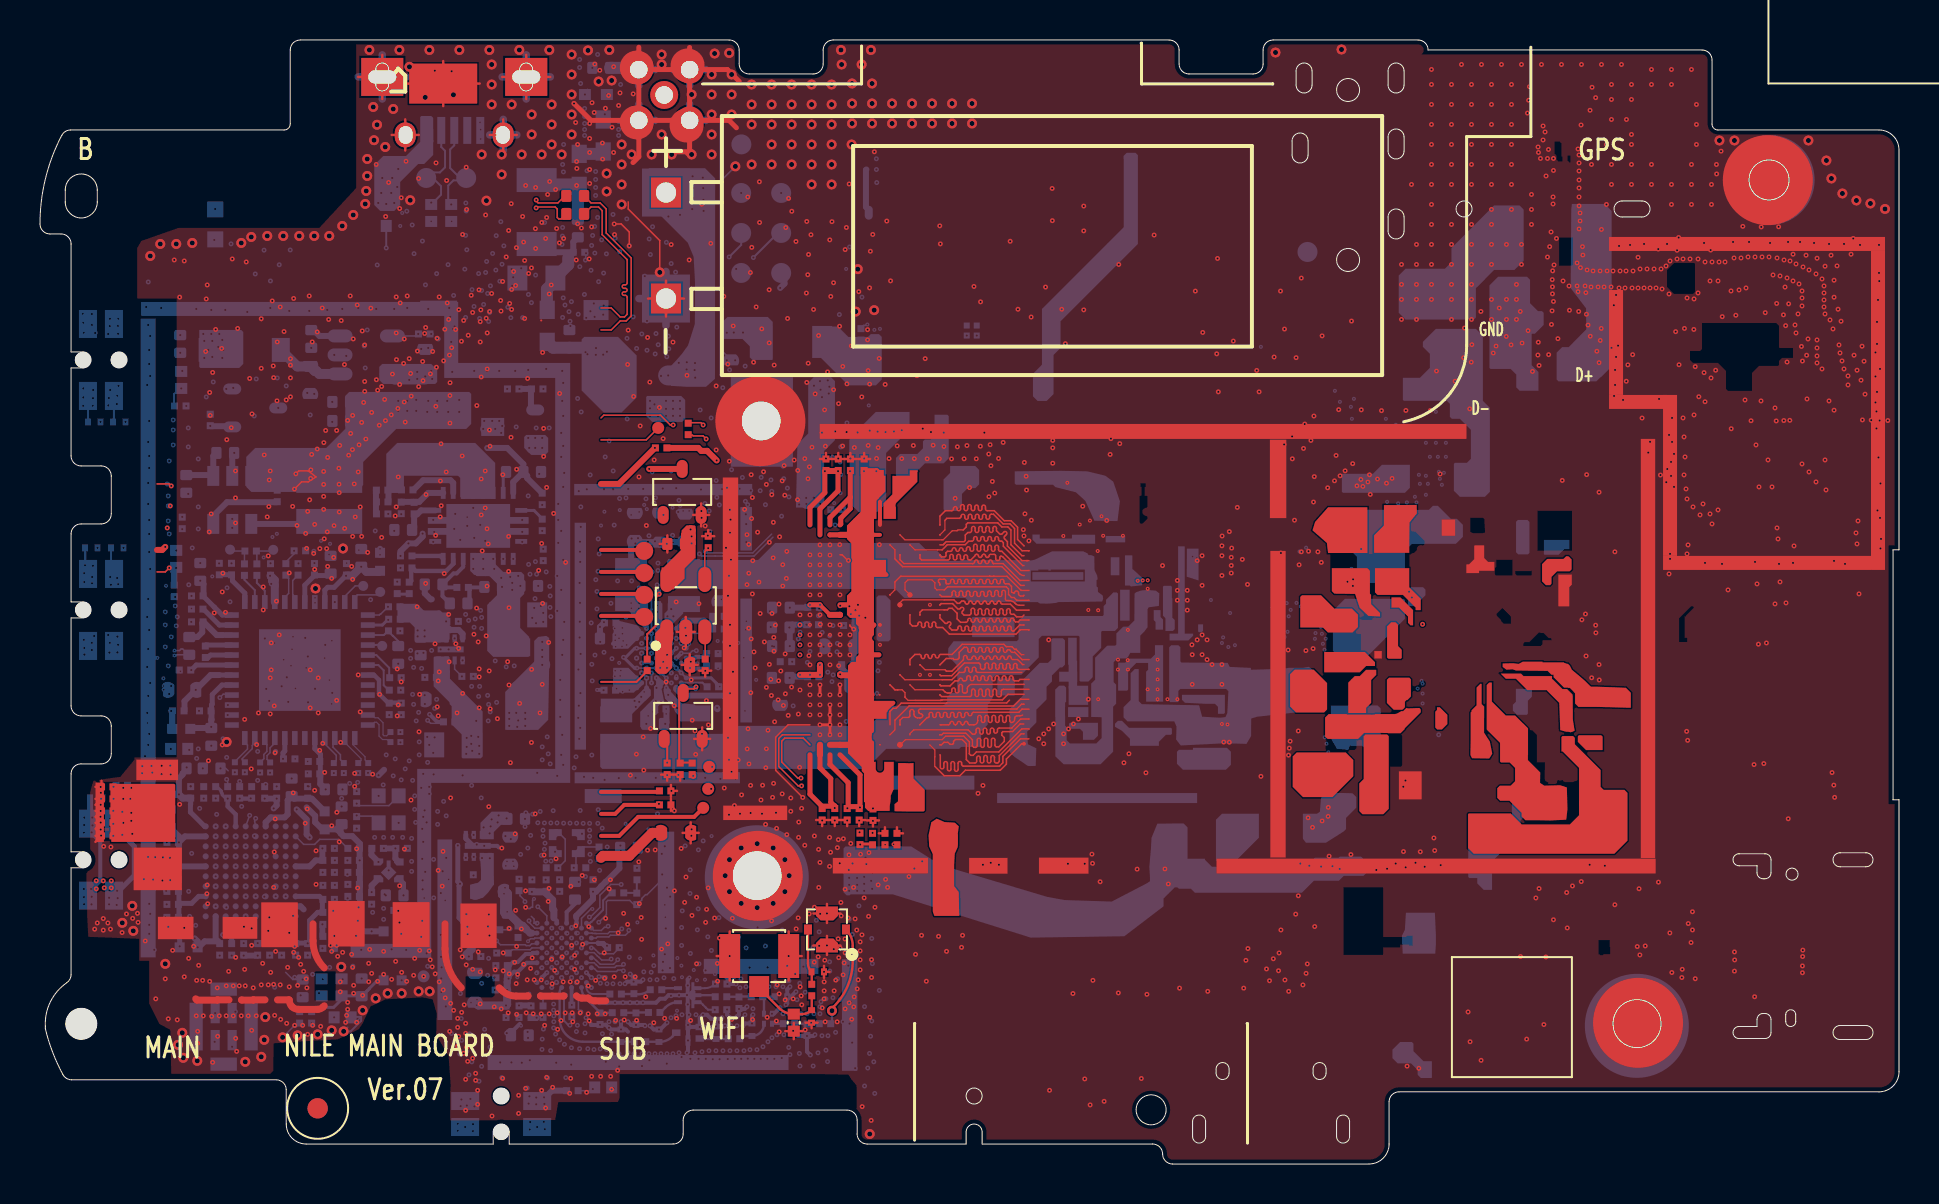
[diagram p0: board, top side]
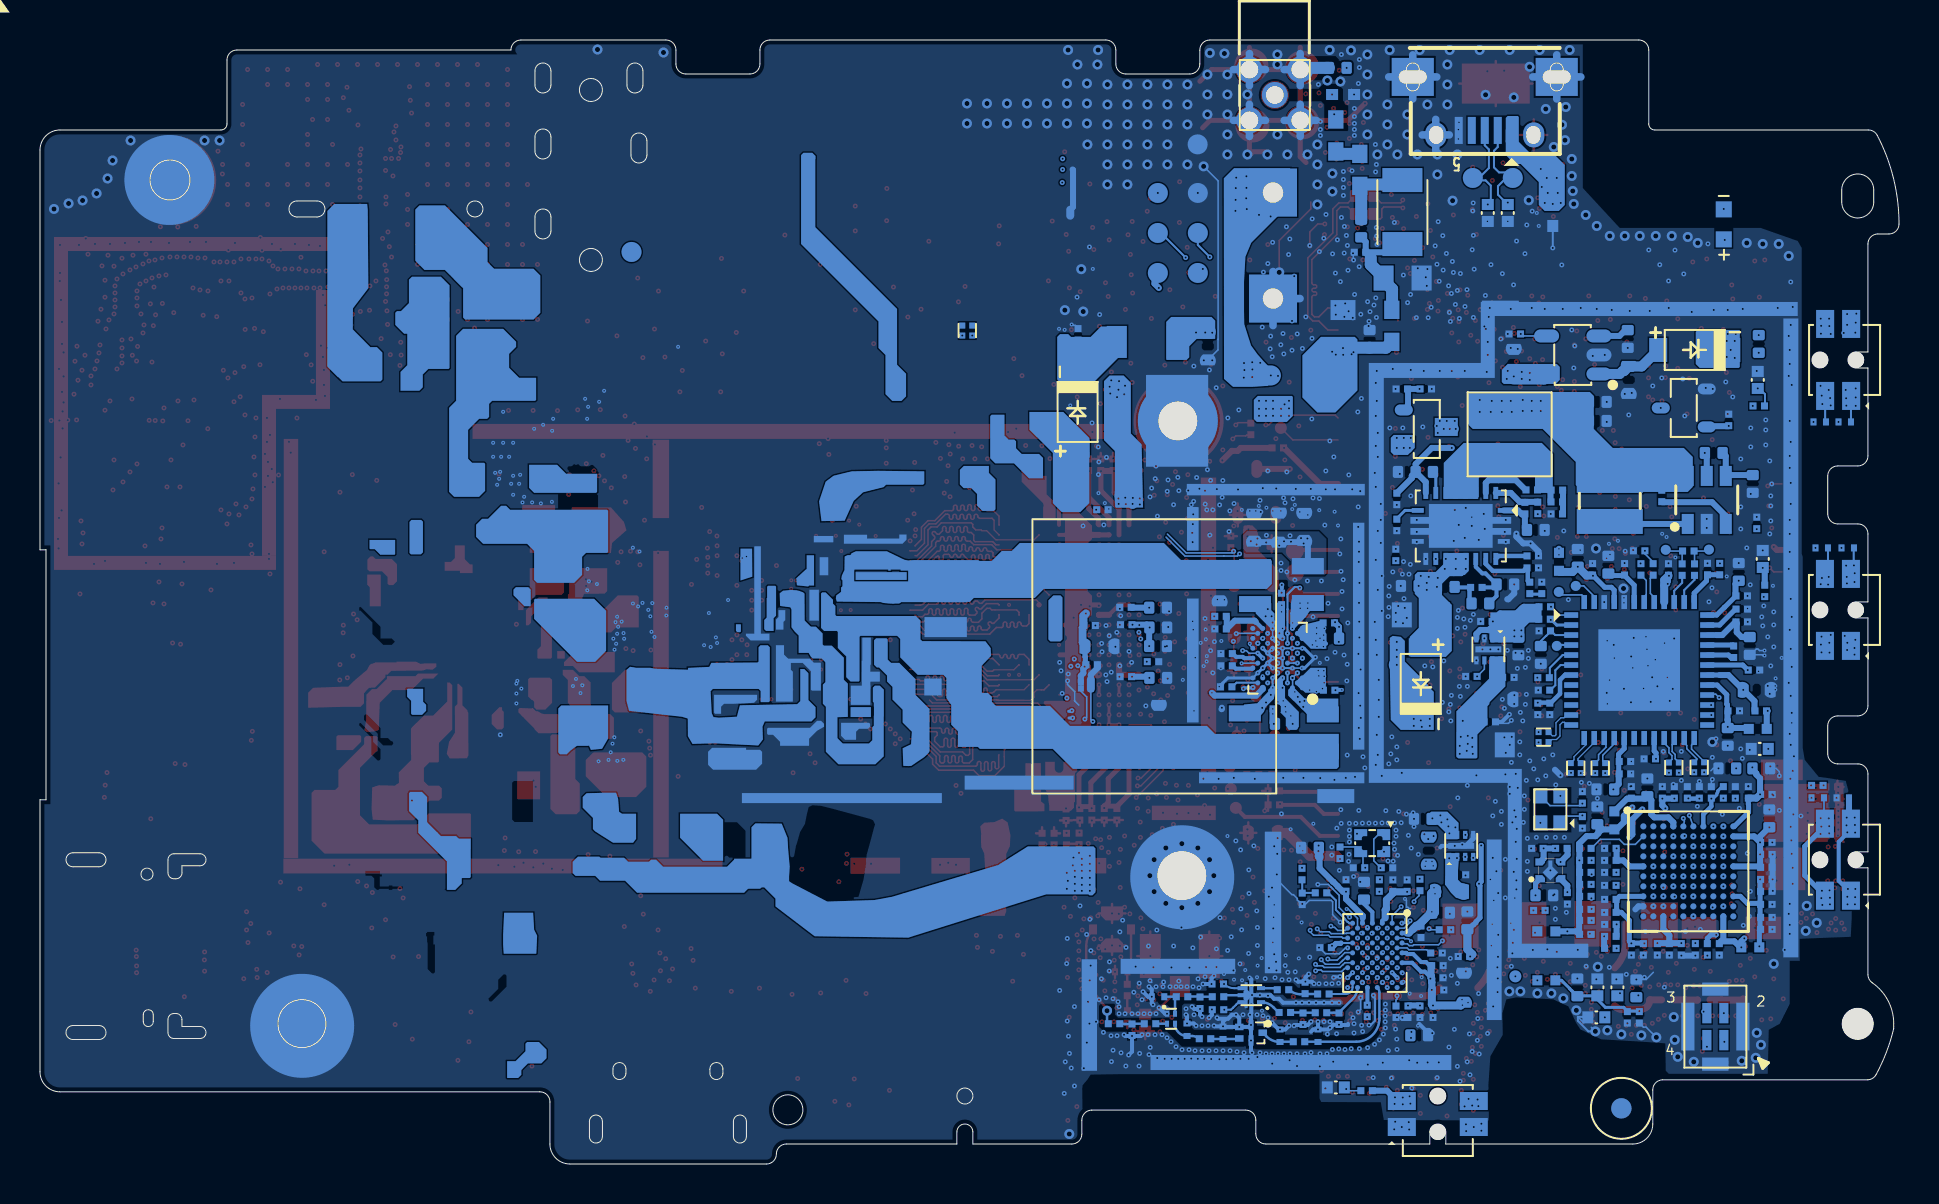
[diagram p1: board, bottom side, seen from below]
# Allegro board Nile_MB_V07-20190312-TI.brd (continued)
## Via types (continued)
v9: diameter 0.25, hole 0.1, INNER LAYER 8 to BOTTOM, 186 vias
v10: diameter 0.25, hole 0.1, TOP to INNER LAYER 3, 1406 vias
v11: diameter 0.5, hole 0.254, TOP to BOTTOM, 186 vias
v12: diameter 0.203, hole 0.076, TOP to INNER LAYER 3, 25 vias
v13: diameter 0.203, hole 0.076, TOP to INNER LAYER 2, 14 vias
v14: diameter 0.203, hole 0.076, INNER LAYER 8 to INNER LAYER 9, 26 vias
v15: diameter 0.203, hole 0.076, INNER LAYER 2 to INNER LAYER 3, 2 vias

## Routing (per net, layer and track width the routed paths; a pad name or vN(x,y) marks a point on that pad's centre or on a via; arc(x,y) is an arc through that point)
GND: length 2793.9
  TOP w0.06: 44.77,19.86 44.74,19.89 44.74,20.36 44.75,20.36 44.75,20.71 44.5,20.95 44.5,20.96
  TOP w0.064: 43.02,20.96 43.27,21.22 45.11,21.22 45.29,21.4 ; 45.11,30.71 44.9,30.71 44.89,30.71 43.76,30.71 43.5,30.96 ; 45.26,24.72 44.26,24.72 44.02,24.96 44,24.96 ; 45.15,23.72 43.75,23.72 43.5,23.96 ; 45.11,21.71 43.69,21.71 43.5,21.53 43.5,21.46 ; 42.75,30.26 42.75,30.72 42.5,30.96 ; 49.08,25.47 49.2,25.47 ; 43,24.46 43.25,24.22 45.11,24.22 ; 44.11,27.69 44.13,27.71 45.2,27.71 ; 42.5,21.46 42.75,21.71 42.75,22.2 42.76,22.21 ; 43.76,23.19 43.41,23.19 43.26,23.34 43.26,23.36 43.26,23.36 43.26,23.57 43.11,23.71 42.9,23.71 42.89,23.71 ; 43.5,28.46 43.26,28.71 43.26,29.07 43.4,29.21 44.61,29.21 44.75,29.07 44.75,28.81 44.85,28.71 45.23,28.71 ; 42.75,29.11 42.75,28.71 42.5,28.46 ; 46.17,31.71 45.9,31.71 45.86,31.67 45.62,31.67 45.17,31.22 45.11,31.22 45.11,31.22 43.25,31.22 43,31.46 ; 45.22,28.21 43.15,28.21 43,28.07 43,27.96 ; 45.25,32.19 45.25,31.71 45,31.46
  TOP w0.076: 29.41,48.11 29.41,47.76 30.99,46.18 v11(30.99,44.59) ; 49.45,21.76 49.1,21.76 47.95,20.61 46.83,20.61 46.66,20.44 46.55,20.44 46.47,20.51 46.47,21.11 46.19,21.4 45.29,21.4 ; 38.5,21.96 37.41,21.96 36.79,21.35 36.79,19.68 v5(38.14,18.33) ; v6(31.72,17.66) 31.72,17.77 31.69,17.8 31.58,17.96 ; 42.5,21.96 42.5,22.63 42.66,22.79 42.81,22.79 43.07,23.05 45.33,23.05 45.34,23.06 48.34,23.06 48.48,23.2 ; 49.45,29.18 49.01,29.18 48.17,30.02 47.68,30.02 47.67,30.03 arc(47.64,30.07) 47.62,30.11 47.62,30.12 arc(47.53,30.21) 47.45,30.12 47.45,30.11 arc(47.36,30.02) 47.27,30.11 47.27,30.12 arc(47.18,30.21) 47.09,30.12 47.09,30.11 arc(47,30.02) 46.91,30.11 46.91,30.12 arc(46.82,30.21) 46.73,30.12 46.73,30.11 arc(46.71,30.05) 46.65,30.02 43.2,30.02 43,30.22 43,30.46 ; 49.45,24.73 49.44,24.74 48.95,24.74 arc(48.89,24.76) 48.86,24.83 48.86,24.94 arc(48.77,25.03) 48.68,24.94 48.68,24.83 arc(48.59,24.74) 48.5,24.83 48.5,24.94 arc(48.41,25.03) 48.33,24.94 48.33,24.83 arc(48.24,24.74) 48.15,24.83 48.15,24.94 arc(48.06,25.03) 47.97,24.94 47.97,24.83 arc(47.88,24.74) 47.79,24.83 47.79,24.96 arc(47.7,25.05) 47.61,24.96 47.61,24.83 arc(47.53,24.74) 47.44,24.83 47.44,24.97 arc(47.35,25.06) 47.26,24.97 47.26,24.82 arc(47.23,24.76) 47.18,24.74 47.09,24.74 47.03,24.8 47.03,24.98 46.96,25.05 46.22,25.05 45.59,24.42 45.05,24.42 45,24.46 ; v6(40.69,26.75) 40.67,26.75 40.5,26.91 40.5,26.96 ; 49.2,27.45 49.12,27.36 48.83,27.36 48.71,27.49 48.59,27.49 arc(48.54,27.51) 48.52,27.57 48.52,27.68 arc(48.43,27.77) 48.34,27.68 48.34,27.54 arc(48.25,27.45) 48.16,27.54 48.16,27.68 arc(48.07,27.77) 47.98,27.68 47.98,27.54 arc(47.89,27.45) 47.81,27.54 47.81,27.68 arc(47.72,27.77) 47.63,27.68 47.63,27.54 arc(47.54,27.45) 47.45,27.54 47.45,27.68 arc(47.36,27.77) 47.27,27.68 47.27,27.54 arc(47.18,27.45) 47.09,27.54 47.09,27.68 arc(47.01,27.77) 46.92,27.68 46.92,27.54 arc(46.83,27.45) 46.74,27.54 46.74,27.71 arc(46.65,27.8) 46.56,27.71 46.56,27.54 arc(46.54,27.48) 46.47,27.45 46.21,27.45 46.13,27.53 arc(46.1,27.59) 46.13,27.64 46.17,27.69 arc(46.17,27.81) 46.05,27.81 46.01,27.78 arc(45.95,27.75) 45.88,27.78 45.63,28.02 45.07,28.02 45,27.96 ; v10(29.46,45.91) 29.46,46.61 29.06,47.01 v10(28.71,47.01) ; 46.17,31.71 46.32,31.86 46.32,31.99 46.4,32.06 47.89,32.06 48.1,31.86 48.4,31.86 48.56,31.71 48.56,30.97 49.11,30.42 49.2,30.42 ; 49.45,22.25 49.05,22.25 48.6,21.8 47.97,21.8 arc(47.91,21.78) 47.88,21.71 47.88,21.63 arc(47.79,21.55) 47.7,21.63 47.7,21.71 arc(47.61,21.8) 47.52,21.71 47.52,21.58 arc(47.43,21.5) 47.34,21.58 47.34,21.71 arc(47.26,21.8) 47.17,21.71 47.17,21.58 arc(47.08,21.5) 46.99,21.58 46.99,21.71 arc(46.9,21.8) 46.81,21.71 46.81,21.58 arc(46.79,21.52) 46.72,21.5 46.62,21.5 46.41,21.71 45.11,21.71 ; 49.1,24.59 46.89,24.59 arc(46.83,24.61) 46.8,24.67 46.8,24.76 arc(46.71,24.85) 46.62,24.76 46.62,24.67 arc(46.54,24.59) 46.45,24.67 46.45,24.76 arc(46.36,24.85) 46.27,24.76 46.27,24.67 arc(46.24,24.61) 46.18,24.59 45.97,24.59 45.6,24.22 45.11,24.22 ; 49.45,28.69 49.06,28.69 48.35,29.4 47.69,29.4 47.69,29.39 47.49,29.39 47.49,29.4 43.04,29.4 42.75,29.11 ; v6(14.83,10.93) 14.75,11.02 14.75,12.01 ; 45,24.96 45.32,25.28 45.66,25.28 45.71,25.23 45.89,25.23 45.96,25.31 45.96,25.59 46.22,25.84 46.32,25.84 arc(46.38,25.81) 46.4,25.75 46.4,25.67 arc(46.49,25.59) 46.58,25.67 46.58,25.75 arc(46.67,25.84) 46.75,25.75 46.75,25.67 arc(46.84,25.59) 46.93,25.67 46.93,25.75 arc(47.02,25.84) 47.11,25.75 47.11,25.67 arc(47.2,25.59) 47.29,25.67 47.29,25.75 arc(47.38,25.84) 47.47,25.75 47.47,25.67 arc(47.55,25.59) 47.64,25.67 47.64,25.75 arc(47.73,25.84) 47.82,25.75 47.82,25.67 arc(47.91,25.59) 48,25.67 48,25.75 arc(48.09,25.84) 48.18,25.75 48.18,25.67 arc(48.27,25.59) 48.35,25.67 48.39,25.72 48.49,25.72 48.53,25.67 arc(48.56,25.61) 48.62,25.59 48.74,25.59 48.75,25.58 49.12,25.22 49.45,25.22 ; 45.11,30.71 45.37,30.97 46.27,30.97 46.45,31.15 46.6,31.15 arc(46.66,31.17) 46.69,31.24 46.69,31.29 arc(46.78,31.38) 46.87,31.29 46.87,31.24 arc(46.96,31.15) 47.04,31.24 47.04,31.29 arc(47.13,31.38) 47.22,31.29 47.22,31.24 arc(47.31,31.15) 47.4,31.24 47.4,31.29 arc(47.49,31.38) 47.58,31.29 47.58,31.24 arc(47.67,31.15) 47.76,31.24 47.76,31.29 arc(47.84,31.38) 47.93,31.29 47.93,31.24 arc(47.96,31.17) 48.02,31.15 48.1,31.15 48.17,31.07 48.17,30.89 49.14,29.93 49.2,29.93 ; 49.45,30.67 49.12,30.67 48.73,31.05 48.73,31.78 48.5,32.01 48.16,32.01 47.68,32.49 47.58,32.49 arc(47.52,32.47) 47.49,32.41 47.49,32.33 arc(47.4,32.24) 47.31,32.33 47.31,32.41 arc(47.22,32.49) 47.13,32.41 47.13,32.33 arc(47.04,32.24) 46.96,32.33 46.96,32.41 arc(46.87,32.49) 46.78,32.41 46.78,32.33 arc(46.69,32.24) 46.6,32.33 46.6,32.41 arc(46.51,32.49) 46.42,32.41 46.42,32.33 arc(46.33,32.24) 46.24,32.33 46.24,32.41 arc(46.16,32.49) 46.07,32.41 46.07,32.37 45.99,32.29 45.35,32.29 45.25,32.19 ; 45,20.96 45.08,20.96 45.2,21.09 45.41,21.09 45.51,20.99 45.63,20.99 45.69,21.04 45.69,21.14 45.77,21.23 46.11,21.23 46.32,21.02 46.32,20.22 46.49,20.05 46.75,20.05 arc(46.81,20.08) 46.84,20.14 46.84,20.32 arc(46.93,20.41) 47.02,20.32 47.02,20.14 arc(47.11,20.05) 47.2,20.14 47.2,20.34 arc(47.29,20.43) 47.37,20.34 47.37,20.14 arc(47.46,20.05) 47.55,20.14 47.55,20.34 arc(47.64,20.43) 47.73,20.34 47.73,20.14 arc(47.76,20.08) 47.82,20.05 47.89,20.05 47.97,20.13 47.97,20.42 49.06,21.51 49.2,21.51 ; v10(12.79,34.51) 12.94,34.66 13.41,34.66 13.8,34.36 13.41,34.11 13.08,34.11 v10(12.72,33.75) ; 45,21.46 45.09,21.46 45.18,21.55 46.29,21.55 46.62,21.22 46.62,20.91 46.7,20.84 46.78,20.84 arc(46.84,20.86) 46.87,20.92 46.87,21.2 arc(46.96,21.29) 47.04,21.2 47.04,20.92 arc(47.13,20.84) 47.22,20.92 47.22,21.21 arc(47.31,21.3) 47.4,21.21 47.4,20.92 arc(47.49,20.84) 47.58,20.92 47.58,21.21 arc(47.67,21.3) 47.76,21.21 47.76,20.94 arc(47.78,20.88) 47.83,20.86 47.95,20.86 48.22,21.14 48.22,21.32 48.1,21.45 48.1,21.57 48.15,21.62 48.63,21.62 49.01,22.01 49.2,22.01 ; 49.45,27.7 48.83,27.7 48.53,28 48.12,28 arc(48.07,28.02) 48.04,28.07 arc(48.02,28.13) 47.97,28.15 47.94,28.15 arc(47.89,28.13) 47.86,28.07 arc(47.84,28.02) 47.79,28 47.76,28 arc(47.71,28.02) 47.69,28.07 arc(47.66,28.13) 47.61,28.15 47.59,28.15 arc(47.53,28.13) 47.51,28.07 arc(47.49,28.02) 47.43,28 47.41,28 arc(47.35,28.02) 47.33,28.07 arc(47.31,28.13) 47.26,28.15 47.23,28.15 arc(47.18,28.13) 47.15,28.07 arc(47.13,28.02) 47.08,28 47.05,28 arc(47,28.02) 46.98,28.07 arc(46.95,28.13) 46.9,28.15 46.87,28.15 arc(46.82,28.13) 46.8,28.07 arc(46.78,28.02) 46.72,28 46.7,28 arc(46.64,28.02) 46.62,28.07 arc(46.6,28.13) 46.54,28.15 46.52,28.15 arc(46.46,28.13) 46.44,28.07 arc(46.42,28.02) 46.37,28 46.34,28 arc(46.29,28.02) 46.26,28.07 arc(46.24,28.13) 46.19,28.15 46.09,28.15 45.98,28.04 45.87,28.04 45.7,28.21 45.22,28.21 ; 49.45,26.71 49.44,26.72 49.01,26.72 49.01,26.7 48.81,26.5 45.47,26.5 45.14,26.83 44.88,26.83 arc(44.82,26.86) 44.79,26.92 44.79,27.02 arc(44.71,27.11) 44.62,27.02 44.62,26.92 arc(44.53,26.83) 44.44,26.92 44.44,27.02 arc(44.35,27.11) 44.26,27.02 44.26,26.92 arc(44.17,26.83) 44.08,26.92 44.08,27.02 arc(43.99,27.11) 43.91,27.02 43.91,27.01 arc(43.88,26.94) 43.8,26.91 43.63,26.91 43.5,27.03 43.5,27.46 ; 42.76,22.21 43.46,22.91 48.7,22.91 49.03,23.24 49.45,23.24 ; 40,30.96 40,30.97 v10(39.99,30.97) ; 45.2,27.71 45.38,27.71 45.46,27.79 45.61,27.79 45.86,27.54 45.86,27.26 46.04,27.09 46.3,27.09 arc(46.37,27.11) 46.39,27.18 46.39,27.2 arc(46.48,27.29) 46.57,27.2 46.57,27.18 arc(46.66,27.09) 46.75,27.18 46.75,27.2 arc(46.84,27.29) 46.92,27.2 46.92,27.18 arc(47.01,27.09) 47.1,27.18 47.1,27.2 arc(47.19,27.29) 47.28,27.2 47.28,27.18 arc(47.37,27.09) 47.46,27.18 47.46,27.2 arc(47.55,27.29) 47.64,27.2 47.64,27.18 arc(47.72,27.09) 47.81,27.18 47.81,27.2 arc(47.9,27.29) 47.99,27.2 47.99,27.18 arc(48.08,27.09) 48.17,27.18 48.17,27.2 arc(48.26,27.29) 48.35,27.2 48.35,27.18 arc(48.44,27.09) 48.53,27.18 48.53,27.2 arc(48.62,27.29) 48.71,27.2 48.71,27.19 48.78,27.11 48.92,27.11 49.01,27.2 49.45,27.2 ; 49.2,30.92 48.89,31.23 48.89,31.84 48.56,32.17 48.22,32.17 47.72,32.67 47.37,32.67 arc(47.31,32.7) 47.28,32.76 47.28,32.86 arc(47.19,32.95) 47.1,32.86 47.1,32.76 arc(47.01,32.67) 46.93,32.76 46.93,32.86 arc(46.84,32.95) 46.75,32.86 46.75,32.76 arc(46.66,32.67) 46.57,32.76 46.57,32.89 arc(46.48,32.98) 46.39,32.89 46.39,32.76 arc(46.3,32.67) 46.21,32.76 46.21,32.89 arc(46.12,32.98) 46.04,32.89 46.04,32.76 arc(45.95,32.67) 45.86,32.76 45.86,32.79 arc(45.77,32.88) 45.68,32.79 45.68,32.76 arc(45.65,32.7) 45.59,32.67 45.28,32.67 45,32.4 45,31.96 ; 45,30.46 45,30.43 45.08,30.36 45.25,30.36 45.31,30.41 45.31,30.56 45.3,30.56 45.38,30.64 45.53,30.64 arc(45.6,30.67) 45.62,30.73 arc(45.71,30.82) 45.8,30.73 arc(45.89,30.64) 45.98,30.73 arc(46.07,30.82) 46.16,30.73 arc(46.24,30.64) 46.33,30.73 46.33,30.78 arc(46.42,30.87) 46.51,30.78 46.51,30.73 arc(46.6,30.64) 46.69,30.73 46.69,30.91 arc(46.78,31) 46.87,30.91 46.87,30.73 arc(46.96,30.64) 47.04,30.73 47.04,30.88 arc(47.13,30.97) 47.22,30.88 47.22,30.73 arc(47.31,30.64) 47.4,30.73 47.4,30.86 arc(47.49,30.95) 47.58,30.86 47.58,30.73 arc(47.67,30.64) 47.76,30.73 47.76,30.86 arc(47.84,30.94) 47.93,30.86 47.93,30.73 arc(47.96,30.67) 48.02,30.64 48.1,30.64 49.06,29.68 49.45,29.68 ; 12.46,8.22 12.45,8.21 ; 43,21.96 43,22.19 43.15,22.33 43.42,22.33 arc(43.48,22.36) 43.5,22.41 43.5,22.63 arc(43.6,22.73) 43.7,22.63 43.7,22.49 arc(43.71,22.45) 43.73,22.41 43.78,22.35 arc(43.83,22.32) 43.88,22.31 43.99,22.31 arc(44.01,22.31) 44.04,22.32 arc(44.11,22.34) 44.14,22.41 44.14,22.44 arc(44.11,22.49) 44.06,22.51 arc(44.01,22.52) 43.97,22.55 43.96,22.56 arc(43.94,22.59) 43.93,22.62 43.93,22.66 arc(43.96,22.73) 44.03,22.76 48.85,22.76 49.09,23 49.2,23 ; 49.2,23.99 46.6,23.99 arc(46.53,23.97) 46.47,23.93 46.4,23.86 arc(46.38,23.83) 46.37,23.8 46.37,23.63 arc(46.35,23.58) 46.29,23.55 46.22,23.55 arc(46.16,23.58) 46.13,23.64 46.13,23.9 arc(46.04,23.99) 45.95,23.9 45.95,23.64 arc(45.86,23.55) 45.77,23.64 45.77,23.72 arc(45.68,23.81) 45.6,23.72 45.6,23.64 arc(45.57,23.58) 45.51,23.55 45.41,23.55 arc(45.32,23.57) 45.25,23.62 45.15,23.72 ; 8.86,8.22 8.88,8.21 ; 45,28.46 45.09,28.38 45.52,28.38 arc(45.58,28.41) 45.61,28.47 45.61,28.58 arc(45.7,28.67) 45.79,28.58 45.79,28.47 arc(45.88,28.38) 45.97,28.47 45.97,28.57 arc(46.06,28.66) 46.14,28.57 46.14,28.47 arc(46.23,28.38) 46.32,28.47 46.32,28.57 arc(46.41,28.66) 46.5,28.57 46.5,28.47 arc(46.59,28.38) 46.68,28.47 46.68,28.55 arc(46.77,28.64) 46.86,28.55 46.86,28.47 arc(46.94,28.38) 47.03,28.47 47.03,28.55 arc(47.12,28.64) 47.21,28.55 47.21,28.47 arc(47.3,28.38) 47.39,28.47 47.39,28.57 arc(47.48,28.66) 47.57,28.57 47.57,28.47 arc(47.66,28.38) 47.74,28.47 47.74,28.6 arc(47.83,28.68) 47.92,28.6 47.92,28.47 arc(48.01,28.38) 48.1,28.47 48.1,28.6 arc(48.19,28.69) 48.28,28.6 48.28,28.25 arc(48.3,28.2) 48.35,28.18 48.45,28.18 arc(48.62,28.14) 48.76,28.05 48.79,28.02 arc(48.87,27.96) 48.96,27.95 49.2,27.95 ; 44,27.46 44,27.59 44.11,27.69 ; v10(40.43,30.18) 40.39,30.18 40.11,30.46 40,30.46 ; 10.05,8.21 10.08,8.21 ; 49.2,28.94 49.04,28.94 48.1,29.87 43.14,29.87 42.75,30.26 ; 27.41,8.32 27.41,8.3 ; 24.43,8.41 24.41,8.41 24.4,8.4 ; 11.28,8.21 11.25,8.21 ; 43,20.96 43.02,20.96 ; 49.45,24.23 49.01,24.23 48.94,24.16 48.75,24.16 arc(48.68,24.19) 48.66,24.25 48.66,24.33 arc(48.57,24.42) 48.48,24.33 48.48,24.25 arc(48.39,24.16) 48.3,24.25 48.3,24.33 arc(48.21,24.42) 48.12,24.33 48.12,24.25 arc(48.04,24.16) 47.95,24.25 47.95,24.33 arc(47.86,24.42) 47.77,24.33 47.77,24.25 arc(47.68,24.16) 47.59,24.25 47.59,24.33 arc(47.5,24.42) 47.41,24.33 47.41,24.25 arc(47.32,24.16) 47.24,24.25 47.24,24.33 arc(47.15,24.42) 47.06,24.33 47.06,24.25 arc(46.97,24.16) 46.88,24.25 46.88,24.33 arc(46.79,24.42) 46.7,24.33 46.7,24.25 arc(46.61,24.16) 46.52,24.25 46.52,24.33 arc(46.44,24.42) 46.35,24.33 46.35,24.25 arc(46.32,24.19) 46.26,24.16 46.18,24.16 arc(46.15,24.18) 46.13,24.21 arc(46.04,24.3) 45.95,24.21 arc(45.94,24.18) 45.9,24.16 45.76,24.16 45.51,23.91 45.06,23.91 45,23.96 ; 49.2,28.44 49.17,28.4 49.04,28.4 arc(48.97,28.44) 48.93,28.52 48.93,28.56 arc(48.83,28.66) 48.73,28.56 48.7,28.56 arc(48.64,28.57) 48.59,28.6 48.59,28.88 48.45,29.01 48.29,29.01 arc(48.23,29.04) 48.2,29.1 48.2,29.16 arc(48.11,29.24) 48.02,29.16 48.02,29.1 arc(47.93,29.01) 47.85,29.1 47.85,29.16 arc(47.76,29.24) 47.67,29.16 47.67,29.1 arc(47.58,29.01) 47.49,29.1 47.49,29.16 arc(47.4,29.24) 47.31,29.16 47.31,29.1 arc(47.22,29.01) 47.13,29.1 47.13,29.16 arc(47.05,29.24) 46.96,29.16 46.96,29.1 arc(46.87,29.01) 46.78,29.1 46.78,29.16 arc(46.69,29.24) 46.6,29.16 46.6,29.1 arc(46.51,29.01) 46.42,29.1 46.42,29.16 arc(46.33,29.24) 46.24,29.16 46.24,29.1 arc(46.16,29.01) 46.07,29.1 46.07,29.16 arc(45.98,29.24) 45.89,29.16 45.89,29.1 arc(45.8,29.01) 45.71,29.1 45.71,29.16 arc(45.62,29.24) 45.53,29.16 45.53,29.1 arc(45.51,29.04) 45.44,29.01 45.33,29.01 arc(45.31,29.04) 45.3,29.07 45.3,29.17 arc(45.28,29.22) 45.23,29.24 45.01,29.24 arc(44.98,29.24) 44.95,29.22 44.94,29.21 arc(44.92,29.15) 44.94,29.1 44.97,29.07 arc(45,29.03) 45,28.99 45,28.96 ; 10.66,8.22 10.68,8.21 ; 49.08,25.47 48.82,25.74 48.8,25.74 48.73,25.74 48.6,25.87 48.32,25.87 48.2,25.99 46.12,25.99 45.61,25.48 45.05,25.48 arc(44.98,25.46) 44.96,25.39 arc(44.87,25.31) 44.78,25.39 arc(44.69,25.48) 44.6,25.39 44.6,25.37 arc(44.51,25.28) 44.42,25.37 44.42,25.39 arc(44.34,25.48) 44.25,25.39 44.25,25.36 arc(44.16,25.27) 44.07,25.36 44.07,25.39 arc(44.04,25.46) 43.98,25.48 43.75,25.48 43.5,25.23 43.5,24.96 ; 41.97,23.46 42,23.46 ; 45,23.46 45.09,23.38 46.5,23.38 arc(46.56,23.4) 46.59,23.46 46.59,23.67 arc(46.68,23.76) 46.76,23.67 46.76,23.46 arc(46.85,23.38) 46.94,23.46 46.94,23.67 arc(47.03,23.76) 47.12,23.67 47.12,23.46 arc(47.21,23.38) 47.3,23.46 47.3,23.67 arc(47.39,23.76) 47.48,23.67 47.48,23.46 arc(47.56,23.38) 47.65,23.46 47.65,23.67 arc(47.74,23.76) 47.83,23.67 47.83,23.46 arc(47.86,23.4) 47.92,23.38 48,23.38 arc(48.05,23.4) 48.07,23.45 48.07,23.64 arc(48.08,23.68) 48.1,23.71 arc(48.13,23.73) 48.18,23.74 49.45,23.74 ; 49.2,23.49 48.41,23.49 48.12,23.21 45.11,23.21 45.1,23.2 45.06,23.2 45.05,23.19 43.76,23.19 ; 23.81,8.42 23.81,8.4 ; 11.85,8.21 11.88,8.21 ; 9.48,8.21 9.45,8.21 ; v10(39,29.47) 39,29.46 ; 11.06,42.18 v5(11.06,42.27) ; 26.8,8.41 26.83,8.41 ; 49.45,22.75 49.11,22.75 48.95,22.59 46.69,22.59 arc(46.63,22.56) 46.6,22.5 arc(46.51,22.41) 46.42,22.5 arc(46.33,22.59) 46.24,22.5 46.24,22.42 arc(46.15,22.33) 46.07,22.42 46.07,22.5 arc(45.98,22.59) 45.89,22.5 45.89,22.42 arc(45.8,22.33) 45.71,22.42 45.71,22.5 arc(45.62,22.59) 45.53,22.5 45.53,22.42 arc(45.44,22.33) 45.35,22.42 45.35,22.5 arc(45.27,22.59) 45.18,22.5 45.18,22.42 arc(45.09,22.33) 45,22.42 45,22.5 arc(44.91,22.59) 44.82,22.5 44.82,22.42 arc(44.73,22.33) 44.64,22.42 44.64,22.5 arc(44.55,22.59) 44.46,22.5 44.46,22.38 arc(44.45,22.34) 44.42,22.33 44.37,22.33 44,21.96 ; 45,27.46 45,27.3 45.26,27.05 arc(45.31,27.03) 45.36,27.05 45.4,27.09 arc(45.53,27.09) 45.53,26.96 45.49,26.92 arc(45.47,26.87) 45.49,26.82 45.6,26.7 45.82,26.7 arc(45.88,26.73) 45.9,26.78 45.9,26.82 arc(45.99,26.91) 46.08,26.82 46.08,26.74 arc(46.17,26.65) 46.26,26.74 46.26,26.82 arc(46.35,26.91) 46.43,26.82 46.43,26.74 arc(46.52,26.65) 46.61,26.74 46.61,26.82 arc(46.7,26.91) 46.79,26.82 46.79,26.74 arc(46.88,26.65) 46.97,26.74 46.97,26.82 arc(47.06,26.91) 47.15,26.82 47.15,26.74 arc(47.23,26.65) 47.32,26.74 47.32,26.82 arc(47.41,26.91) 47.5,26.82 47.5,26.74 arc(47.59,26.65) 47.68,26.74 47.68,26.82 arc(47.77,26.91) 47.86,26.82 47.86,26.74 arc(47.95,26.65) 48.03,26.74 48.03,26.82 arc(48.12,26.91) 48.21,26.82 48.21,26.74 arc(48.3,26.65) 48.39,26.74 48.39,26.82 arc(48.48,26.91) 48.57,26.82 48.57,26.74 arc(48.59,26.68) 48.66,26.65 48.69,26.65 49,26.96 49.2,26.96 ; 49.45,30.17 49.36,30.17 49.11,30.17 48.38,30.9 48.38,31.12 48.24,31.26 arc(48.21,31.33) 48.24,31.39 48.33,31.48 arc(48.33,31.61) 48.2,31.61 48.11,31.52 arc(48.05,31.49) 47.98,31.52 47.83,31.67 47.83,31.8 arc(47.74,31.88) 47.65,31.8 47.65,31.67 arc(47.56,31.58) 47.48,31.67 47.48,31.8 arc(47.39,31.88) 47.3,31.8 47.3,31.67 arc(47.21,31.58) 47.12,31.67 47.12,31.8 arc(47.03,31.88) 46.94,31.8 46.94,31.67 arc(46.85,31.58) 46.76,31.67 46.76,31.8 arc(46.68,31.88) 46.59,31.8 46.59,31.67 arc(46.56,31.61) 46.5,31.58 46.4,31.58 46.27,31.45 46.27,31.19 46.21,31.12 45.32,31.12 45.23,31.03 45.23,31.03 45.17,30.96 45,30.96 ; 42.5,23.96 42.76,23.71 42.89,23.71 ; 45.26,24.72 45.33,24.65 45.6,24.65 46.18,25.23 46.18,25.34 arc(46.27,25.43) 46.36,25.34 46.36,25.32 arc(46.39,25.25) 46.45,25.23 46.53,25.23 arc(46.59,25.25) 46.62,25.32 46.62,25.32 arc(46.7,25.41) 46.79,25.32 46.79,25.32 arc(46.88,25.23) 46.97,25.32 46.97,25.32 arc(47.06,25.41) 47.15,25.32 47.15,25.32 arc(47.24,25.23) 47.33,25.32 47.33,25.32 arc(47.42,25.41) 47.5,25.32 47.5,25.32 arc(47.59,25.23) 47.68,25.32 47.68,25.32 arc(47.77,25.41) 47.86,25.32 47.86,25.32 arc(47.95,25.23) 48.04,25.32 48.04,25.32 arc(48.13,25.41) 48.22,25.32 48.22,25.32 arc(48.3,25.23) 48.39,25.32 48.39,25.32 arc(48.48,25.41) 48.57,25.32 48.57,25.32 arc(48.6,25.25) 48.66,25.23 48.89,25.23 49.14,24.98 49.2,24.98 ; 45,20.46 45.02,20.45 45.02,19.85 arc(45.11,19.76) 45.2,19.85 45.2,20.04 arc(45.29,20.13) 45.38,20.04 45.38,19.75 arc(45.47,19.66) 45.56,19.75 45.56,20.04 arc(45.64,20.13) 45.73,20.04 45.73,19.73 arc(45.82,19.64) 45.91,19.73 45.91,20.04 arc(46,20.13) 46.09,20.04 46.09,19.98 arc(46.11,19.92) 46.18,19.9 47.98,19.9 48.15,20.06 48.15,20.38 49.03,21.26 49.45,21.26 ; 25,8.41 25.03,8.41 ; 26.23,8.41 26.2,8.41 ; 44,30.46 44,30.29 44.08,30.21 45.41,30.21 arc(45.47,30.23) 45.49,30.3 45.49,30.4 arc(45.58,30.49) 45.67,30.4 45.67,30.3 arc(45.76,30.21) 45.85,30.3 45.85,30.4 arc(45.94,30.49) 46.03,30.4 46.03,30.3 arc(46.12,30.21) 46.21,30.3 46.21,30.38 arc(46.29,30.46) 46.38,30.38 46.38,30.3 arc(46.41,30.23) 46.47,30.21 46.55,30.21 46.75,30.41 arc(46.77,30.47) 46.83,30.49 46.85,30.49 arc(46.91,30.47) 46.93,30.41 arc(46.95,30.36) 47.01,30.34 47.03,30.34 arc(47.09,30.36) 47.11,30.41 arc(47.13,30.47) 47.18,30.49 47.21,30.49 arc(47.26,30.47) 47.29,30.41 arc(47.31,30.36) 47.36,30.34 47.39,30.34 arc(47.44,30.36) 47.46,30.41 arc(47.49,30.47) 47.54,30.49 47.72,30.49 arc(47.77,30.47) 47.79,30.41 47.79,30.26 arc(47.82,30.21) 47.87,30.18 47.91,30.18 arc(47.97,30.21) 48,30.27 48,30.34 arc(48.01,30.38) 48.06,30.39 arc(48.11,30.38) 48.16,30.35 48.99,29.52 arc(49.09,29.45) 49.2,29.43 ; 45.23,28.71 45.38,28.86 48.33,28.86 48.43,28.75 48.43,28.48 48.59,28.33 48.71,28.33 48.84,28.19 49.45,28.19 ; 44.77,19.86 45.21,19.42 46,19.42 46.28,19.69 48.02,19.69 48.33,20 48.33,20.25 48.81,20.73 49.09,21.02 49.2,21.02 ; 45,21.96 45.05,21.96 45.43,21.96 arc(45.49,21.99) 45.51,22.05 arc(45.54,22.11) 45.6,22.13 45.61,22.13 arc(45.67,22.11) 45.69,22.05 arc(45.72,21.99) 45.78,21.96 45.78,21.96 arc(45.84,21.99) 45.87,22.05 arc(45.89,22.11) 45.95,22.13 45.96,22.13 arc(46.02,22.11) 46.05,22.05 arc(46.07,21.99) 46.13,21.96 46.14,21.96 arc(46.2,21.99) 46.22,22.05 arc(46.25,22.11) 46.31,22.13 46.32,22.13 arc(46.38,22.11) 46.4,22.05 arc(46.43,21.99) 46.49,21.96 46.69,21.96 arc(46.84,22.02) 46.9,22.17 46.9,22.35 arc(46.98,22.44) 47.07,22.35 47.07,22.17 arc(47.16,22.08) 47.25,22.17 47.25,22.35 arc(47.34,22.44) 47.43,22.35 47.43,22.17 arc(47.52,22.08) 47.61,22.17 47.61,22.35 arc(47.7,22.44) 47.79,22.35 47.79,22.17 arc(47.87,22.08) 47.96,22.17 47.96,22.35 arc(48.05,22.44) 48.14,22.35 48.14,22.17 arc(48.23,22.08) 48.32,22.17 48.32,22.35 arc(48.41,22.44) 48.5,22.35 48.5,22.17 arc(48.52,22.11) 48.59,22.08 arc(48.69,22.12) 48.74,22.23 48.74,22.28 arc(48.75,22.33) 48.78,22.38 arc(48.81,22.4) 48.86,22.41 48.99,22.41 arc(49.07,22.42) 49.14,22.45 ; 25.61,8.42 25.61,8.4
  TOP w0.1: 25.06,42.18 25.06,42.19
  TOP w0.12: 23.11,54.36 USB1.9 ; USB1.9 24.32,55.47 ; USB1.9 24.32,53.26 ; USB1.9 25.52,54.36 ; C6277.2 31.3,44.18 ; C6277.2 30.4,43.28 ; C6277.2 32.21,43.28 ; C6277.2 31.3,42.38 ; 37.44,9.17 v5(37.44,10.4) ; v5(37.44,10.4) 38.09,10.4 ; v5(37.44,10.4) 37.44,11.63 ; 2.77,17.06 C6362.1 2.77,16.76 ; 22.49,51.46 USB1.7 ; USB1.7 23.84,51.46 ; USB1.7 23.17,50.69 ; USB1.7 23.17,52.24 ; 31.37,30.58 C4608.2 ; C4608.2 31.37,31.44 ; C4608.2 30.99,31.01 ; 34.49,9.17 v5(34.49,10.4) ; v5(34.49,10.4) 34.49,11.63 ; v5(34.49,10.4) 33.84,10.4 ; USB1.8 18.32,54.36 ; USB1.8 15.91,54.36 ; USB1.8 17.12,53.26 ; USB1.8 17.12,55.47 ; 40.91,35.26 C134.2 ; C134.2 41.52,35.26 ; C134.2 41.21,35.56 ; 33.11,20.68 Q2712.2 ; Q2712.2 33.11,21.84 ; Q2712.2 33.52,21.26 ; Q2712.2 32.71,21.26 ; 31.36,19.17 R6655.1 ; R6655.1 31.67,19.47 ; R6655.1 31.06,19.47 ; 3.08,19.16 C6217.1 2.77,18.86 ; 41.65,16.88 C151.2 ; C151.2 41.96,17.18 ; C151.2 41.35,17.18 ; 20.16,52.9 CN3.1 ; CN3.1 21.99,54.03 ; CN3.1 18.34,54.03 ; CN3.1 20.16,55.16 ; 31.55,17.66 C6365.1 31.55,18.26 ; 39.11,16.9 C122.2 ; C122.2 38.81,17.2 ; C122.2 39.42,17.2 ; C4607.2 32.49,25.49 ; C4607.2 32.49,24.43 ; C4607.2 32.89,24.96 ; C4607.2 32.09,24.96 ; R6657.1 31.85,18.66 ; R6657.1 31.55,18.96 ; R6657.1 31.55,18.36 ; 38.68,12.53 v5(39.35,12.53) ; v5(39.35,12.53) 39.35,13.01 ; v5(39.35,12.53) 39.35,12.05 ; v5(39.35,12.53) 40.03,12.53 ; Q2711.2 33.06,33.04 ; Q2711.2 32.66,32.46 ; Q2711.2 33.47,32.46 ; Q2711.2 33.06,31.88 ; C65.2 39.61,35.26 ; C65.2 39.3,35.56 ; C65.2 39,35.26 ; 43.16,16.54 C6288.2 42.85,16.84 ; 38.58,6.79 L22.1 ; L22.1 38.28,7.07 ; L22.1 38.89,7.07 ; C9.2 40.05,17.2 ; C9.2 39.74,16.9 ; C9.2 39.44,17.2 ; v5(39.21,9.61) 39.21,9.91 ; v5(39.21,9.61) 39.21,9.31 ; v5(39.21,9.61) 39.48,9.61 ; 32.01,19.17 C437.1 31.71,19.47 ; 40.36,16.9 C139.2 40.06,17.2 ; 18.27,50.69 USB1.6 ; USB1.6 17.59,51.46 ; USB1.6 18.94,51.46 ; USB1.6 18.27,52.24 ; C6366.2 32.54,17.09 ; C6366.2 32.54,16.03 ; C6366.2 32.14,16.56 ; C6366.2 32.94,16.56 ; 39.35,10.45 v5(39.35,10.93) ; v5(39.35,10.93) 38.68,10.93 ; v5(39.35,10.93) 40.03,10.93 ; v5(39.35,10.93) 39.35,11.41 ; 40.23,35.26 C138.2 ; C138.2 40.53,35.56 ; C138.2 40.83,35.26 ; R4647.2 33.41,31.7 ; R4647.2 33.72,31.4 ; R4647.2 33.11,31.4 ; 31.84,26.61 U3702.2 ; U3702.2 32.29,27.36 ; U3702.2 32.29,25.86 ; U3702.2 32.75,26.61 ; 39.62,35.26 C123.2 ; C123.2 40.22,35.26 ; C123.2 39.92,35.56 ; 2.77,16.41 C6364.1 2.77,16.11 ; 37.27,6.64 D3865.2 ; D3865.2 37.69,6.24 ; D3865.2 38.12,6.64 ; D3865.2 37.69,7.05 ; 40.97,16.9 C131.2 41.27,17.2 ; 32.96,24.67 R4648.2 ; R4648.2 33.26,24.37 ; R4648.2 33.57,24.67 ; 2.77,18.26 C6361.1 2.77,17.96 ; 2.77,17.36 C6363.1 2.77,17.66 ; 42.25,16.84 C6289.2 41.95,16.54
  TOP w0.15: v5(39,23.96) 39,23.46 ; v6(39.5,22.96) v6(39.5,22.46) v6(39.5,21.96) ; v6(39.5,21.96) v6(39.5,21.46) ; v6(39.5,21.96) v6(39,21.96) ; v5(40,23.96) v5(40,23.46)
  TOP w0.2: 42,33.12 42,31.96
  TOP w0.25: 34.82,51.82 34.45,52.19 CON2.2 ; CON2.2 CON2.1 ; CON2.2 32.48,50.63 32.38,50.53 ; CON2.2 CON2.3 ; CON2.1 27.55,52.19 v10(26.7,53.04) ; CON2.1 CON2.4 ; CON2.1 29.94,50.37 29.65,50.08 ; 31.66,50.62 32.6,50.62 ; CON2.3 34.38,54.73 34.96,54.15 ; CON2.3 32.48,55.84 ; CON2.3 CON2.4 ; CON2.4 29.94,55.84
  TOP w0.35: 26.2,8.41 26.19,8.4 25.04,8.4 25.03,8.41 ; 13.65,12.01 13.65,11.16 arc(13.8,10.43) 14.21,9.81 ; 7.79,8.26 7.85,8.2 8.86,8.2 8.88,8.21 9.45,8.21 ; 22.96,8.81 23.07,8.71 arc(23.41,8.48) 23.81,8.4 24.4,8.4 24.4,8.41 ; 20.25,12.01 20.25,10.77 arc(20.46,9.71) 21.06,8.81 ; 28.29,8.16 27.75,8.16 arc(27.57,8.2) 27.41,8.3 27.1,8.3 arc(26.95,8.33) 26.83,8.41 ; 10.08,8.21 10.09,8.2 10.66,8.2 10.68,8.21 11.25,8.21 ; 14.21,7.91 14.15,7.84 arc(14.03,7.76) 13.88,7.73 12.93,7.73 arc(12.75,7.77) 12.6,7.87 arc(12.5,8.02) 12.46,8.2 12.45,8.21 11.88,8.21
  INNER LAYER 2 w0.076: 69.14,31.88 69.2,31.94 69.2,33.06 69.04,33.21 66.87,33.21 66.81,33.15 66.81,31.9 66.72,31.81 ; v5(16.54,42.8) 16.54,42.63 ; 71.42,29.96 71.42,28.54 71.57,28.39 71.57,27.75 71.67,27.65 71.7,27.65 71.86,27.49 71.86,27.19 71.86,27.19 v6(71.86,26.74) ; 69.64,25.01 69.54,25.11 68.4,25.11 68.22,24.93 67.13,24.93 66.36,24.16
  INNER LAYER 2 w0.376: 31.68,52.19 CON2.2 ; CON2.2 33.29,52.19 ; CON2.2 32.48,52.99 ; CON2.2 32.48,51.39 ; C6277.2 32.35,43.28 ; C6277.2 30.26,43.28 ; C6277.2 31.3,44.32 ; C6277.2 31.3,42.24 ; CON2.4 30.75,54.73 ; CON2.4 29.14,54.73 ; CON2.4 29.94,55.53 ; CON2.4 29.94,53.93 ; 15.91,54.36 USB1.8 ; USB1.8 18.32,54.36 ; USB1.8 17.12,53.26 ; USB1.8 17.12,55.47 ; HOLE1.1 38.02,14.42 ; HOLE1.1 35.86,16.57 ; HOLE1.1 33.71,14.42 ; HOLE1.1 35.86,12.27 ; USB1.6 18.27,52.24 ; USB1.6 18.94,51.46 ; USB1.6 18.27,50.69 ; USB1.6 17.59,51.46 ; 34.41,37.16 HOLE3.1 ; HOLE3.1 36.06,35.51 ; HOLE3.1 37.72,37.16 ; HOLE3.1 36.06,38.81 ; 29.14,52.19 CON2.1 ; CON2.1 29.94,51.39 ; CON2.1 29.94,52.99 ; CON2.1 30.75,52.19 ; CON2.3 33.29,54.73 ; CON2.3 31.68,54.73 ; CON2.3 32.48,55.53 ; CON2.3 32.48,53.93 ; USB1.9 25.52,54.36 ; USB1.9 23.11,54.36 ; USB1.9 24.32,53.26 ; USB1.9 24.32,55.47 ; USB1.7 23.84,51.46 ; USB1.7 23.17,52.24 ; USB1.7 23.17,50.69 ; USB1.7 22.49,51.46
  INNER LAYER 3 w0.06: 49.14,23.36 49.29,23.51 50.21,23.51 50.22,23.52 ; 50.21,23.74 50.02,23.92 49.33,23.92 49.23,23.83 48.9,23.83 48.56,23.49 ; 50.19,22.99 50.16,22.96 49.83,22.96 49.79,23 49.57,23 49.56,22.99 ; 50.44,23.24 50.19,23.24 50.06,23.38 49.4,23.38 49.23,23.21 49.2,23.21 ; 48.68,23.97 49.17,23.97 49.26,24.06 50.18,24.06 50.22,24.02
  INNER LAYER 3 w0.064: 45.99,27.57 45.68,27.26 45.15,27.26 44.95,27.46 ; 50.43,22.74 50.43,22.73 50.43,22.4 50.36,22.34 50.36,22.08 50.31,22.03 ; 41.41,30.72 41.41,30.86 41.8,31.25 42.13,31.25 42.33,31.05 48.25,31.05 48.79,30.5 48.89,30.5
  INNER LAYER 3 w0.07: 77.19,35.9 64.89,35.9 ; 77.27,36.1 64.78,36.1 64.78,36.09 ; 77.53,36.61 77.36,36.61 77.36,36.61 64.59,36.61 64.59,36.61 64.42,36.61 ; 77.45,36.41 64.51,36.41
  INNER LAYER 3 w0.075: v7(34.51,8.64) 34.55,8.64 34.95,9.04 35.12,9.04 35.19,9.11 35.2,9.11 35.35,9.26 ; 34,10.16 v10(33.87,10.03)
  INNER LAYER 3 w0.076: v3(19.55,25.02) 20.11,24.46 20.36,24.46 ; 49.01,30.06 49.01,30.11 48.97,30.11 48.25,30.83 42.19,30.83 42.1,30.74 42.01,30.74 41.95,30.79 41.95,30.94 v10(41.98,30.97) ; v10(8.42,20.17) 8.05,20.54 8.05,23.4 7.95,23.5 7.95,23.63 8.05,23.73 8.05,24.59 8.2,24.74 8.2,30.67 ; 32.01,19.45 v6(31.93,19.45) ; v7(40.36,26.34) 40.33,26.37 40.33,26.45 40.01,26.45 v6(40.01,26.48) ; v3(10.65,16.73) 10.65,16.06 ; 49.6,27.53 49.55,27.53 49.43,27.66 46.42,27.66 45.88,27.12 42.87,27.12 42.45,27.54 42.26,27.54 42,27.8 42,27.96 ; 13.1,19.53 13.29,19.72 13.29,19.91 13.1,20.1 v3(13.1,20.47) ; v3(36.46,22.66) 36.37,22.66 ; 36.37,22.66 36.37,22.74 36.37,22.74 36.37,23.01 35.84,23.01 35.71,22.88 35.71,22.84 35.67,22.8 35.67,22.54 35.71,22.5 35.71,22.38 35.71,22.38 35.71,21.23 35.47,20.99 35.47,20.92 35.3,20.92 35.2,20.83 35.2,20.69 35.3,20.6 35.47,20.6 35.47,20.26 34.15,18.94 34.15,18.61 33.75,18.21 33.66,18.21 33.33,18.55 33.33,20.56 33.18,20.71 32.89,20.71 32.86,20.68 32.93,20.62 32.93,20.58 32.95,20.55 32.95,20.42 32.93,20.39 32.93,18.52 32.91,18.51 33.22,18.21 33.22,17.53 33.03,17.35 33.03,16.75 v7(32.96,16.68) 32.31,17.33 32.31,19.86 34.47,22.01 34.47,22.86 35.01,23.41 35.01,24.33 35.17,24.48 35.17,24.81 35.46,25.11 v7(35.46,25.41) ; 36.37,22.66 36.37,22.33 36.37,22.33 36.37,20.4 36.12,20.15 36.12,20.12 35.84,19.85 35.84,18.54 34.32,17.01 v7(33.97,16.67) ; 48.73,27.9 46.22,27.9 45.99,27.68 45.99,27.57 ; v7(32.93,34.16) 32.79,34.01 32.79,32.58 33,32.37 33,30.45 32.62,30.06 32.51,30.06 32.07,30.51 32.07,33.78 32.06,33.79 32.06,34.52 32.25,34.71 32.25,35.72 32.06,35.91 32.06,37.56 ; 42.66,26.6 42.24,27.02 42.05,27.02 42.03,27.04 40.98,27.04 40.84,27.18 39.85,27.18 39.39,26.72 38.73,26.72 38.5,26.95 v12(38.5,26.96) ; v3(9.95,20.02) 10.31,20.02 v10(10.56,19.76) 10.56,19.61 11.05,19.12 ; 49.73,24.97 49.71,24.99 48.7,24.99 48.64,25.05 48.19,25.05 48.12,24.98 47.41,24.98 47.3,24.87 46.38,24.87 45.9,25.35 44.91,25.35 44.41,24.85 42.3,24.85 42.03,24.58 42.03,24.57 42.01,24.55 42.01,24.46 ; 35.48,8.59 34.87,7.97 31.3,7.97 31.18,8.08 30.52,8.08 30.47,8.13 ; v10(16.23,40.96) 16.23,40.83 16.07,40.67 ; v7(39.16,25.37) 39.23,25.3 39.34,25.3 v6(39.5,25.46) ; v7(41.15,9.59) 41.15,10.06 49.28,18.18 49.39,18.18 49.67,18.46 49.76,18.46 49.96,18.67 49.97,18.67 50.34,19.04 50.34,20.19 50.76,20.6 50.82,20.6 51.29,21.08 51.29,21.13 51.48,21.31 51.48,21.58 51.71,21.81 51.71,21.85 51.84,21.97 51.93,21.97 51.93,22.2 ; v1(17.86,29.12) 17.53,29.12 v3(17.46,29.06) ; v10(11.75,20.57) 12,20.32 12,19.92 11.2,19.12 11.05,19.12 ; 50.44,22.75 50.43,22.74 ; 42,27.46 42.05,27.46 42.18,27.34 42.37,27.34 42.79,26.92 45.97,26.92 46.51,27.46 49.34,27.46 49.5,27.3 49.7,27.3 49.85,27.44 50.19,27.44 50.19,27.45 ; 33.56,22.69 33.41,22.54 33.41,22.28 33.59,22.11 33.67,22.11 33.52,21.96 v10(33.43,21.96) 32.51,21.05 32.51,21.42 v10(32.75,21.66) ; v10(32.56,24.21) 32.56,23.61 32.26,23.31 ; 49.7,30.42 49.53,30.59 49.53,30.64 49.52,30.64 49.52,30.66 48.48,31.7 39.15,31.7 38.67,31.22 38.67,30.79 v10(39,30.46) ; 50.31,22.03 48.9,20.62 39.22,20.62 38.74,21.1 38.74,22.22 v10(38.5,22.46) ; 42.28,30.28 42.46,30.47 47.94,30.47 47.98,30.43 47.98,30.37 ; 50.44,29.18 49.4,29.18 48.87,29.71 48.8,29.71 48.57,29.94 48.3,29.94 48.21,29.85 47.49,29.85 47.49,29.85 41.1,29.85 40.44,30.51 40.35,30.51 40.12,30.29 39.95,30.29 39.63,29.96 v10(39,29.96) ; v10(38.5,28.46) 38.55,28.46 38.65,28.37 44.92,28.37 45.09,28.2 48.77,28.2 48.98,27.99 49.11,27.86 49.61,27.86 49.78,27.7 50.44,27.7 ; v3(40.97,26.55) 40.89,26.55 40.7,26.75 v6(40.69,26.75) ; v10(39,21.46) 39.24,21.7 40.7,21.7 41.34,21.06 48.76,21.06 49.95,22.25 ; 10.76,18.82 11.05,19.12 ; 10.76,18.82 10.91,18.66 ; 10.76,18.82 10.52,18.82 10.52,18.86 9.58,18.86 9.25,19.19 v7(9.25,19.22) ; 32.06,23.95 32.06,23.81 31.87,23.61 ; v7(29.73,13.86) 29.74,13.85 v7(30.69,13.85) ; 38.98,28.96 39.22,28.72 45.06,28.72 45.23,28.56 48.96,28.56 49.19,28.33 49.29,28.33 ; 38.98,28.96 38.85,29.09 38.71,29.09 38.6,29.2 38.41,29.2 38.24,29.04 38.24,28.39 38.26,28.37 38.26,28.36 38.4,28.22 38.58,28.22 38.58,28.22 38.62,28.22 38.71,28.13 38.83,28.13 38.88,28.18 38.88,28.18 38.91,28.2 39.1,28.2 39.13,28.18 40.78,28.18 40.81,28.2 41,28.2 41.03,28.18 41.06,28.18 41.11,28.22 41.58,28.22 41.63,28.18 41.71,28.18 ; 38.98,28.96 v10(39,28.96) ; v3(9.73,16.78) 8.48,16.78 8.28,16.98 ; 30.47,8.13 30.54,8.13 ; 30.47,8.13 30.3,8.31 30.3,8.37 30.23,8.43 30.14,8.43 v3(30.14,8.44) ; v7(40.34,25.1) 40.3,25.1 40,25.4 v6(40,25.46) ; v10(38.73,12.84) 37.72,12.84 37.42,12.54 37.37,12.54 37.21,12.38 35.02,12.38 34.94,12.46 33.67,12.46 33.63,12.43 v10(32.6,12.43) 32.08,11.9 31.31,11.9 30.26,10.85 29.73,10.85 ; v6(38.45,25.42) 38.26,25.22 37.62,25.22 37.59,25.19 37.59,25.12 37.41,24.95 37.16,24.95 36.98,25.12 36.98,25.38 37.16,25.55 37.16,25.75 36.68,26.22 36.68,28.55 v6(36.75,28.62) ; v3(41.7,25.52) 42,25.83 v12(42,25.96) 42.14,26.09 47.77,26.09 47.81,26.14 48.02,26.14 ; 42.02,24.96 42.12,24.96 42.22,25.06 44.32,25.06 44.82,25.56 45.99,25.56 46.47,25.08 47.22,25.08 47.32,25.19 48.04,25.19 48.11,25.25 48.73,25.25 48.79,25.2 49.62,25.2 49.67,25.24 49.88,25.24 50.14,24.98 50.19,24.98 ; 41.77,21.22 41.62,21.37 ; 32.26,23.31 32.19,23.23 32.14,23.23 32.21,23.31 32.26,23.31 ; 48.69,29.28 48.69,29.28 48.63,29.33 48.53,29.33 48.53,29.33 40.52,29.33 40.15,29.7 39.23,29.7 v10(39,29.47) ; 41.91,30.22 41.41,30.72 41.15,30.72 41.06,30.82 40.18,30.82 40.08,30.72 39.77,30.72 v10(39.5,30.45) ; 42,21.96 42.07,21.96 42.18,21.85 48.78,21.85 49.26,22.33 49.26,22.68 49.56,22.99 ; v7(39.64,13.35) 40.2,13.9 40.9,13.9 ; v10(38.5,23.46) 38.52,23.48 38.52,23.58 38.79,23.85 39.26,23.85 39.27,23.86 47.58,23.86 48.25,24.52 48.7,24.52 48.78,24.6 49.39,24.6 49.47,24.52 50.15,24.52 50.19,24.48 ; v7(39.63,12.8) 39.32,12.48 39.32,12.42 38.2,11.3 v10(33.97,11.3) 31.45,11.3 31.08,10.93 v10(31.08,10.75) 31.08,10.47 30.57,9.96 30.05,9.96 29.73,10.28 29.73,10.85 ; v7(39.33,27.25) 39.05,26.96 39,26.96 39,26.98 v6(39.02,26.98) ; v10(38.5,23.96) 38.59,24.05 39.18,24.05 39.19,24.06 47.5,24.06 48.16,24.73 48.62,24.73 48.69,24.8 49.48,24.8 49.55,24.73 50.44,24.73 ; 41.71,28.18 41.88,28.18 41.91,28.2 44.87,28.2 44.97,28.1 ; 41.71,28.18 41.71,27.97 41.76,27.92 41.76,27.62 41.71,27.57 41.71,27.41 v6(41.65,27.34) 41.78,27.2 42.09,27.2 42.11,27.18 42.3,27.18 42.72,26.76 46.03,26.76 46.58,27.31 49.16,27.31 49.25,27.21 49.25,27.21 ; v7(38.72,26.25) 38.72,26.25 38.72,26.26 38.5,26.04 38.5,25.97 v6(38.5,25.97) ; 48.96,26.13 48.95,26.13 48.61,26.47 48.3,26.47 48.24,26.53 47.86,26.53 47.57,26.25 42.22,26.25 v12(42,26.46) ; v10(39.99,30.97) 40.42,31.39 48.36,31.39 49.22,30.53 49.22,30.52 49.23,30.51 49.23,30.32 49.62,29.93 50.19,29.93 ; v3(9.23,18.04) 9.91,17.36 10.36,17.36 ; 11.06,42.29 11.06,42.25 11,42.25 11,42.24 v6(10.99,42.24) ; 50.19,28.44 49.73,28.44 49.44,28.73 49.21,28.73 49.08,28.86 48.49,28.86 48.32,29.03 40.04,29.03 39.83,29.23 38.91,29.23 38.68,29.46 v10(38.5,29.46) ; 47.06,25.36 46.55,25.36 46.2,25.71 44.75,25.71 44.3,25.26 41.91,25.26 41.67,25.02 41.67,24.77 41.7,24.75 41.7,24.49 41.67,24.47 41.67,24.23 41.15,24.23 41.15,24.22 40.96,24.22 40.93,24.25 40.5,24.25 40.47,24.22 40.22,24.22 40.21,24.23 39.9,24.23 39.88,24.25 39.16,24.25 39.11,24.2 38.33,24.2 38.2,24.07 38.2,24.02 38.17,23.99 38.17,23.28 38.24,23.2 38.68,23.2 38.94,23.46 v10(38.99,23.46) 39.09,23.46 39.34,23.71 ; v6(31.36,19.45) 31.96,20.05 31.96,20.21 34.16,22.41 34.16,23.01 34.29,23.14 v7(34.29,24.04) 34.86,24.61 34.86,27.11 35.97,28.21 v7(36.21,28.21) ; v10(39,30.96) 39.59,31.55 48.42,31.55 49.37,30.59 49.37,30.58 49.38,30.57 49.38,30.38 49.58,30.17 49.95,30.17 ; v10(38.5,22.96) 38.67,22.96 38.91,23.2 39.69,23.2 39.84,23.35 48.06,23.35 48.68,23.97 ; 48.23,30.2 48.23,30.19 48.1,30.05 47.33,30.05 47.29,30.01 41.22,30.01 40.57,30.66 40.24,30.66 40.01,30.44 39.84,30.44 39.61,30.2 38.74,30.2 v10(38.5,29.96) ; 13.86,24.62 14.69,25.44 14.75,25.44 14.88,25.3 15.36,25.3 16.9,26.85 16.9,27.68 ; v10(40,29.46) 40.29,29.18 48.39,29.18 48.56,29.01 49.15,29.01 49.28,28.88 49.5,28.88 49.7,28.69 50.44,28.69 ; 16.71,47.25 18.61,47.25 v7(19.05,47.69) 19.05,48.01 19.41,48.37 20.33,48.37 20.75,47.95 20.75,47.33 20.25,46.83 20.18,46.83 19.91,46.56 17.53,46.56 ; v10(33.87,10.03) 33.85,10.01 v10(32.83,10.01) 32.4,10.01 31.43,9.04 v7(31.43,9) 31.27,8.83 31.26,8.83 31.21,8.89 30.96,8.89 30.91,8.83 30.9,8.83 30.83,8.76 27.89,8.76 27.27,9.38 27.27,9.57 26.57,10.27 26.51,10.27 ; 49.95,22.73 49.91,22.77 49.63,22.77 49.46,22.6 49.46,22.24 48.87,21.65 42.21,21.65 42.02,21.46 42,21.46 ; 48.56,23.49 48.22,23.15 40.19,23.15 v10(40,22.96) ; 31.32,35.63 31.32,36.31 31.32,36.31 31.27,36.31 31.27,36.28 v10(31.16,36.28) ; 48.87,32.38 48.69,32.38 48.49,32.18 40.38,32.18 40.08,31.88 38.83,31.88 38.43,31.49 38.43,30.53 38.5,30.46 v6(38.5,30.46) ; 50.19,22.5 50.19,22.16 48.85,20.81 41.26,20.81 40.61,21.46 v10(40,21.46) ; 31.26,35.57 v7(31.11,35.57) ; 49.96,24.27 49.94,24.24 49.23,24.24 49.11,24.12 48.54,24.12 47.96,23.54 39.58,23.54 v10(39.5,23.46) ; v10(40.43,30.18) 40.43,30.12 40.89,29.65 48.33,29.65 48.39,29.71 48.48,29.71 ; v7(29.29,15.25) 29.29,15.16 29.15,15.16 28.58,14.59 28.58,14.45 27.36,14.45 26.8,13.89 v10(26.54,13.89) 26.52,13.87 26.12,13.87 26.02,13.77 26,13.77 25.73,13.5 25.5,13.5 25.32,13.68 25.32,14.1 25.54,14.32 v7(25.54,14.55) 25.99,14.55 26.35,14.91 28.11,14.91 28.33,15.13 28.39,15.13 30.12,16.86 30.26,16.86 31.58,18.17 v6(31.58,18.66) ; 49.2,23.21 49.19,23.2 49.18,23.2 48.52,22.54 40.82,22.54 40.51,22.22 39.24,22.22 v10(39,22.46) ; 41.01,15.03 v10(40.63,15.03) ; v10(38.5,28.96) 38.5,28.96 38.5,28.81 38.73,28.57 45,28.57 45.17,28.4 48.86,28.4 49.2,28.07 49.7,28.07 49.86,27.9 50.15,27.9 ; 42.41,9.84 42.22,10.03 42.22,10.7 49.4,17.88 49.52,17.88 49.8,18.16 49.9,18.16 51.28,19.54 51.28,20.06 51.61,20.39 51.61,20.74 51.83,20.97 51.83,21.23 51.93,21.33 51.93,21.76 ; v7(40.84,25.51) 40.8,25.46 v6(40.5,25.46) ; v10(39,22.96) 39.25,22.72 40.4,22.72 40.63,22.94 48.49,22.94 49.06,23.52 49.09,23.52 49.25,23.69 49.89,23.69 49.92,23.72 ; 49.95,28.19 49.85,28.29 49.67,28.29 49.38,28.58 49.15,28.58 49.02,28.71 48.43,28.71 48.26,28.88 39.59,28.88 v10(39.5,28.96) ; v3(7.88,15.78) 8.08,15.78 8.33,15.53 10.03,15.53 10.68,16.18 ; v10(40,22.46) 40.4,22.46 40.67,22.74 48.5,22.74 49.12,23.36 49.14,23.36 ; 29.73,10.85 29.73,12 v10(30.06,12.33) ; v10(40,21.96) 40.58,21.96 40.97,22.35 48.56,22.35 49.25,23.05 49.34,23.05 49.47,23.17 49.94,23.17 ; 50.19,29.43 49.84,29.43 49.77,29.5 49.3,29.5 48.94,29.86 48.88,29.86 48.12,30.62 42.28,30.62 42.12,30.46 42,30.46 ; 38.96,10.3 38.84,10.3 38.71,10.17 38.62,10.17 38.51,10.07 37.55,10.07 37.46,10.16 34,10.16 ; 42.6,26.44 42.18,26.86 41.99,26.86 41.97,26.88 40.92,26.88 40.77,27.03 40.44,27.03 arc(40.38,27) 40.35,26.94 40.35,26.8 arc(40.27,26.71) 40.18,26.8 40.18,26.94 arc(40.15,27) 40.09,27.03 39.91,27.03 39.75,26.87 39.75,26.32 39.65,26.22 39.58,26.22 39.5,26.3 39.5,26.46 v12(39.5,26.46) ; v6(40.5,25.96) 40.5,25.97 40.74,26.21 41.06,26.21 41.29,26.44 v3(41.42,26.44) ; 44.6,24.23 44.1,24.23 44.1,24.22 42.41,24.22 42.4,24.23 42.18,24.23 42.18,24.3 42.24,24.37 42.24,24.58 42.36,24.7 44.51,24.7 45.01,25.2 45.84,25.2 45.94,25.1 45.94,24.67 46.02,24.59 ; 50.19,28.94 50.19,28.94 49.66,28.94 49.57,29.03 49.34,29.03 48.88,29.49 40.78,29.49 40.31,29.96 v10(40,29.96) ; 50.44,23.74 50.21,23.74 ; v3(7.2,21.76) 7.01,21.76 7.01,29.66 7.21,29.86 ; 42.99,21.39 48.61,21.39 48.71,21.5 48.81,21.5 48.93,21.5 49.61,22.18 49.61,22.2 49.63,22.22 49.63,22.42 49.7,22.49 49.7,22.5 ; 7.21,29.86 7.26,29.91 ; 7.21,29.86 7.21,35.53 v7(6.73,36.01) ; 25.45,16.52 25.42,16.52 25.37,16.47 24.67,16.47 24.38,16.18 v7(24.38,15.96) ; 15.43,39.94 15.39,39.98 v10(15.22,39.98) ; 42.87,22.11 42.84,22.08 42.84,22.03 47.69,22.03 ; 26.43,9.52 26.5,9.45 26.5,9.47 26.06,9.91 25.23,9.91 v7(25,10.14) 25,10.76 v7(24.89,10.87) ; v7(38.75,25.67) 39,25.92 v6(39,25.96) ; v7(27.75,11.08) 28.3,10.53 28.3,10.29 27.89,9.88 27.89,9.63 28.17,9.35 28.79,9.35 28.86,9.42 30.77,9.42 32.05,10.7 38.52,10.7
  INNER LAYER 3 w0.1: 5.93,38.01 5.93,37.52 5.86,37.45 ; 18.85,43.35 18.91,43.35 19.86,44.31 20.01,44.31 20.31,44.61 ; 13.86,24.62 13.86,19.36 ; 13.86,19.36 14.56,18.66 14.56,17.87 v10(14.84,17.59) 14.84,19.25 14.39,19.7 14.39,23.3 15.22,24.14 v7(15.27,24.14) ; 13.86,19.36 13.86,19.12 ; v3(16.46,24.3) 16.46,24.44 16.6,24.58 16.6,24.59 16.78,24.78 16.8,24.78 18.25,26.23 18.25,28.27 v3(17.46,29.06) ; 15.71,44.51 15.71,44.75 17.53,46.56 ; v3(13.96,30.36) 13.47,29.87 13.15,29.87 12.81,30.21 12.81,31.76 12.88,31.83 12.88,31.84 13.58,32.54 13.58,35.43 13.91,35.75 13.91,36.28 14.31,36.69 14.31,38.52 15,39.2 15,39.59 15.21,39.8 15.3,39.8 16.07,40.58 16.07,40.67 ; v10(18.86,27.86) 18.71,27.71 19.15,27.27 19.35,27.27 19.45,27.17 19.45,26.75 19.28,26.58 ; 7.87,34.43 8.3,34.43 ; 7.29,41.53 7.35,41.59
  INNER LAYER 3 w0.15: v3(18.55,21.92) 18.78,21.69 18.78,21.03 18.68,20.93 18.68,20.82 18.48,20.62 18.37,20.62 17.62,19.87 v3(16.95,19.87) ; 41.62,21.37 41.62,21.51 v6(41.55,21.58) ; 30,22.37 30,22.52 29.51,23.01 29.51,23.06 29.41,23.17 28.82,23.17 28.46,22.81 28.46,22.26 28.61,22.11 28.61,21.26 27.91,20.56 27.81,20.56 v10(24.76,17.51)
  INNER LAYER 3 w0.2: 13.47,37.27 13.47,38.89 13.58,39 13.58,40.29 14.2,40.92 ; 13.47,37.27 12.74,36.54 12.74,35.04 v3(12.66,34.96) v3(12.66,34.11) v3(12.66,33.36) 12.31,33.01 v7(12.31,31.25) ; 13.47,37.27 13.47,37.01 13.44,36.98 13.44,36.67 13.47,36.64 ; v7(44.83,24.57) 44.83,24.51 44.79,24.46 v12(44.5,24.46) v12(44,24.46)
  INNER LAYER 3 w0.25: v12(44.5,27.96) v6(44,27.96) 43.76,27.96 ; 42.5,24.46 v12(44,24.46)
  INNER LAYER 3 w0.3: v6(23.81,9.02) 24.43,9.02 v7(24.44,9.01) ; v6(22.01,9.61) 22.01,9.75 v7(22.18,9.91) ; v3(13.96,30.36) 13.86,30.36 13.23,30.98 13.23,31.48 v10(13.29,31.53) 13.58,31.83 13.63,31.83 14.18,32.38 14.18,35.13 v10(14.38,35.33) v10(14.98,35.93) 18.13,39.08 18.13,39.13 v10(18.54,39.53) v10(19.14,40.13) v10(19.64,40.63) v10(21.18,42.18) v10(23.14,44.13) v10(24.79,45.78) v10(25.29,46.28) 27.48,48.48 27.48,52.35 v10(27.71,52.58) ; v7(24.58,3.02) 24.86,2.74 ; 15.14,42.87 15.29,42.71 15.29,42.41 v6(15.06,42.18)
  INNER LAYER 3 w0.305: 44.95,27.46 v6(44.5,27.46)
  INNER LAYER 3 w0.376: USB1.6 18.94,51.46 ; USB1.6 18.27,52.24 ; USB1.6 18.27,50.69 ; USB1.6 17.59,51.46 ; USB1.8 18.32,54.36 ; USB1.8 17.12,55.47 ; USB1.8 17.12,53.26 ; USB1.8 15.91,54.36 ; 30.26,43.28 C6277.2 ; C6277.2 31.3,44.32 ; C6277.2 31.3,42.24 ; C6277.2 32.35,43.28 ; CON2.2 32.48,52.99 ; CON2.2 31.68,52.19 ; CON2.2 32.48,51.39 ; CON2.2 33.29,52.19 ; 34.41,37.16 HOLE3.1 ; HOLE3.1 36.06,38.81 ; HOLE3.1 36.06,35.51 ; HOLE3.1 37.72,37.16 ; CON2.3 33.29,54.73 ; CON2.3 31.68,54.73 ; CON2.3 32.48,53.93 ; CON2.3 32.48,55.53 ; USB1.9 25.52,54.36 ; USB1.9 24.32,55.47 ; USB1.9 23.11,54.36 ; USB1.9 24.32,53.26 ; HOLE1.1 38.02,14.42 ; HOLE1.1 35.86,12.27 ; HOLE1.1 33.71,14.42 ; HOLE1.1 35.86,16.57 ; CON2.1 30.75,52.19 ; CON2.1 29.94,51.39 ; CON2.1 29.14,52.19 ; CON2.1 29.94,52.99 ; CON2.4 30.75,54.73 ; CON2.4 29.14,54.73 ; CON2.4 29.94,53.93 ; CON2.4 29.94,55.53 ; USB1.7 23.84,51.46 ; USB1.7 22.49,51.46 ; USB1.7 23.17,52.24 ; USB1.7 23.17,50.69
  INNER LAYER 4 w0.076: v7(41.15,9.59) 41.15,9.61 41.17,9.61 41.33,9.45
  INNER LAYER 4 w0.25: 31.23,54.73 CON2.4 ; 31.23,54.73 CON2.3 ; 31.23,54.73 31.23,55.59 31.22,55.6 ; CON2.4 CON2.1 ; CON2.4 29.94,55.13 29.28,55.78 29.21,55.71 v11(28.47,55.71) ; CON2.4 28.19,54.73 27.78,55.13 ; v3(28.33,51.38) 28.33,51.63 28.89,52.19 CON2.1 ; 32.54,54.73 CON2.3 ; 32.54,54.73 34.22,53.05 33.36,52.19 CON2.2 ; 32.54,54.73 32.93,54.73 v11(33.73,55.53) ; CON2.3 CON2.2 ; v7(32.91,49.83) 32.48,50.26 CON2.2 ; CON2.1 31.97,52.19 ; CON2.1 29.94,50.37 29.65,50.08 ; 68.09,22.6 67.68,22.6 ; CON2.2 31.97,52.19 ; 31.97,52.19 31.2,51.42
  INNER LAYER 4 w0.3: 34.68,37.96 34.06,37.96 ; 36.86,38.55 36.86,38.66 37.32,39.12 ; 34.53,38.99 34.98,38.55 35.26,38.55 ; 34.46,37.16 34.27,37.16 34,36.89 ; 37.45,37.96 38.2,37.96
  INNER LAYER 4 w0.376: USB1.7 23.84,51.46 ; USB1.7 23.17,50.69 ; USB1.7 23.17,52.24 ; USB1.7 22.49,51.46 ; 17.59,51.46 USB1.6 ; USB1.6 18.27,50.69 ; USB1.6 18.94,51.46 ; USB1.6 18.27,52.24 ; 23.11,54.36 USB1.9 ; USB1.9 25.52,54.36 ; USB1.9 24.32,53.26 ; USB1.9 24.32,55.47 ; USB1.8 17.12,55.47 ; USB1.8 15.91,54.36 ; USB1.8 18.32,54.36 ; USB1.8 17.12,53.26 ; 30.26,43.28 C6277.2 ; C6277.2 31.3,44.32 ; C6277.2 31.3,42.24 ; C6277.2 32.35,43.28
  INNER LAYER 4 w0.4: 85.41,4.91 85.61,5.11 85.61,6.58 80.3,6.58 79.86,7.02 ; 85.25,17.47 85.61,17.11 85.61,15.22 84.32,15.22 83.47,14.38
  INNER LAYER 5 w0.06: 25.89,14.39 26.08,14.2 26.08,13.82
  INNER LAYER 5 w0.076: 24.63,5.98 23.58,5.98 23.48,5.88 22.41,5.88 21.25,7.04 21.25,8.67 19.08,10.83 18.78,10.83 v3(18.5,11.12) ; 24.63,5.98 24.18,6.43 ; 24.63,5.98 24.78,5.83 25.13,5.83 25.35,6.05 28.82,6.05 28.83,6.03 29,6.2 29,6.2 29.17,6.36 v7(29.33,6.36) ; v7(38.72,26.25) 38.72,26.17 39.02,25.87 40.56,25.87 40.68,25.99 ; v3(28.15,6.62) 27.95,6.42 27.25,6.42 ; 27.25,6.42 v3(27.25,6.57) ; 27.25,6.42 25.65,6.42 25.45,6.62 24.88,6.62 24.83,6.57 24.35,6.57 23.85,7.07 v7(23.6,7.07) 23.23,7.43 23.23,9.73 23.14,9.83 v7(23.14,9.99) 23.18,9.99 23.48,10.29 23.48,11.34 23.45,11.37 23.45,11.94 22.98,12.42 22.98,13.18 23.17,13.37 23.9,13.37 24.75,12.52 v7(24.75,12.47) ; v7(33.66,41.02) 33.66,41.12 33.31,41.46 32.34,41.46 31.99,41.11 31.51,41.11 ; 8.51,17.91 9.11,17.91 9.11,18.03 9.23,18.03 v3(9.23,18.04) 9.31,18.11 9.31,18.26 9.46,18.26 9.56,18.16 9.56,18.08 ; 29.91,16.51 29.87,16.47 ; 29.87,16.47 29.79,16.47 ; 29.87,16.47 29.85,16.45 v7(29.18,16.45) ; 20.9,17.5 19.05,17.5 19.06,17.51 19.06,17.65 18.91,17.5 16.97,17.5 ; 20.9,17.5 32.15,17.5 32.41,17.76 33.36,17.76 33.76,17.36 33.65,17.36 v7(32.96,16.68) 33.02,16.68 33.03,16.66 ; 20.9,17.5 20.79,17.61 ; 15.82,17.5 15.79,17.5 15.73,17.44 15.54,17.44 15.48,17.5 12.51,17.5 ; 15.82,17.5 15.77,17.55 15.65,17.55 15.65,17.59 ; 15.82,17.5 16.97,17.5 ; 31.48,24.3 31.48,23.81 ; 31.48,23.81 32.58,22.71 32.62,22.71 32.88,22.45 32.88,22.91 35.78,22.91 35.85,22.97 36.1,22.97 36.11,22.96 36.14,22.96 36.18,22.91 36.19,22.91 36.19,22.91 36.42,22.91 42.05,17.28 ; 31.48,23.81 31.35,23.81 ; 37.85,31.55 35.56,29.26 35.56,27.81 35.17,27.41 ; v7(9.25,19.22) 9.95,18.52 11.05,18.52 11.31,18.26 12.01,18.26 12.51,17.76 12.51,17.5 ; 30.64,13.85 29.74,13.85 v7(29.73,13.86) ; 32.37,40.21 32.37,40.13 32.19,39.96 31.94,39.96 31.84,40.06 31.59,40.06 31.49,39.96 31.24,39.96 31.23,39.96 31.03,40.16 30.26,40.16 v7(30.26,40.31) ; 37.76,35.19 37.23,34.65 37.23,34.62 36.93,34.31 34.92,34.31 34.28,34.95 31.54,34.95 30.68,34.09 25.15,34.09 24.06,35.18 22.36,35.18 22.34,35.16 22.11,35.16 22.09,35.18 21.09,35.18 ; v3(18.83,24.13) 18.94,24.13 19.2,23.87 25.2,23.87 27.86,21.22 36.45,21.22 36.7,20.97 36.7,20.92 ; 35.17,27.41 35.06,27.41 34.31,28.16 34.31,28.91 v3(34.27,28.96) ; 35.17,27.41 35.17,27.36 35.96,26.56 ; v7(31.11,35.57) 31.85,35.57 32.1,35.81 34.09,35.81 34.99,34.91 36.55,34.91 36.56,34.9 36.81,34.9 37.55,35.64 ; v7(36.21,28.21) 36.41,28.01 36.41,27.48 37.97,27.48 38.17,27.69 38.25,27.69 38.23,27.67 ; 12.51,17.5 12.46,17.44 10.23,17.44 10.18,17.5 10.14,17.5 ; 39.53,27.05 v7(39.33,27.25) ; 27.79,20.38 24.81,20.38 24.63,20.57 22.4,20.57 22.15,20.82 22.05,20.82 22,20.87 22,22.27 21.2,23.07 19.1,23.07 18.95,22.92 18.75,22.92 v3(18.4,22.57) 18.4,22.47 17.95,22.02 17.95,20.47 ; 27.79,20.38 29.41,20.38 ; 27.79,20.38 25.06,23.11 23.46,23.11 23.21,22.86 ; 19.01,19.67 19.13,19.54 21.75,19.54 21.91,19.71 21.91,19.76 ; 19.01,19.67 18.95,19.62 16.95,19.62 ; 19.01,19.67 19.45,20.12 20.12,20.12 20.59,20.59 21.03,20.59 21.86,19.76 21.91,19.76 ; v7(40.34,25.1) 40.44,25 42.13,25 arc(42.19,24.97) 42.22,24.91 42.22,24.83 arc(42.31,24.74) 42.39,24.83 42.39,24.91 arc(42.48,25) 42.57,24.91 42.57,24.83 arc(42.66,24.74) 42.75,24.83 42.75,24.91 arc(42.83,25) 42.92,24.91 42.92,24.83 arc(43.01,24.74) 43.1,24.83 43.1,24.91 arc(43.12,24.97) 43.19,25 ; 10.14,17.5 9.92,17.5 9.56,17.86 9.56,18.08 ; 10.14,17.5 9.56,18.08 ; 30.31,36.28 29.73,36.28 v7(29.45,36.01) 27.19,36.01 27.07,36.12 ; v3(19.55,25.02) 20.23,24.34 22.33,24.34 22.4,24.28 25.36,24.28 28.05,21.58 36.53,21.58 ; 31.51,41.11 31.49,41.14 31.09,41.14 ; 31.51,41.11 31.41,41.11 ; 8.16,37.47 8.16,37.24 v3(8.18,37.24) ; v7(41.15,9.59) 41.15,9.61 41.3,9.61 41.49,9.42 ; 33.03,16.66 33.62,16.66 HOLE1.1 ; 33.03,16.66 33.1,16.73 33.67,16.73 33.87,16.93 34.08,16.93 34.28,16.73 v7(34.78,16.73) 35.48,16.73 v7(35.67,16.92) ; 29.23,5.68 29.05,5.51 28.46,5.51 28.38,5.43 25.48,5.43 25.35,5.31 25.23,5.18 22.58,5.18 22.46,5.31 22.24,5.31 21.15,6.39 ; 16.95,19.62 16.4,19.62 16.2,19.82 16.13,19.82 15.75,20.19 15.75,20.27 v3(15.65,20.37) ; 16.95,19.62 v3(16.95,19.87) ; v7(27.75,11.08) 27.95,11.08 28.9,10.13 28.9,9.38 28.66,9.14 26.9,9.14 26.32,8.56 ; v3(35.01,22.68) 35.04,22.68 35.59,22.14 36.72,22.14 41.89,16.97 ; v7(21.63,40.43) 19.15,40.43 18.01,41.56 v3(17.01,41.56) ; 37.42,35.94 36.86,35.39 36.86,35.39 36.69,35.22 35.2,35.22 34.45,35.96 34.38,35.96 34.27,36.07 34.27,36.07 34.22,36.11 31.97,36.11 31.93,36.07 31.24,36.07 31.23,36.08 31.1,36.08 31.08,36.07 30.96,36.07 ; 35.26,37.96 34.68,37.96 34.46,37.75 34.46,37.55 ; 35.26,37.96 35.26,38.07 ; 35.26,37.96 35.38,38.07 35.93,38.07 36.09,37.92 36.09,37.18 HOLE3.1 ; 29.41,20.38 36.45,20.38 ; 29.41,20.38 29.33,20.46 ; 41.6,13.57 36.2,18.97 36.18,18.97 36.17,18.98 19.55,18.98 19.51,19.02 13.43,19.02 12.81,19.64 12.81,19.73 12.54,19.99 12.54,20.13 12.25,20.42 10.55,20.42 10.35,20.22 ; 16.21,17.66 16.81,17.66 16.97,17.5 ; 20.35,46.25 22.78,46.25 23.31,46.78 39.05,46.78 39.38,46.45 ; v7(39.16,25.37) 39.27,25.48 40.39,25.48 40.72,25.15 ; 38.16,31.23 38.16,30.96 37.16,29.96 ; 23.21,15.51 22.79,15.09 ; v7(32.88,44.02) 33.19,43.71 34.91,43.71 35.39,43.24 35.86,43.24 v7(36.22,42.88) 36.22,43.01 36.66,43.46 ; 21.91,19.76 36.23,19.76 41.77,14.22 ; 38.72,32.09 38.65,32.03 36.01,32.03 36.01,32.52 v7(35.08,33.45) 35.49,33.86 37.27,33.86 38.12,34.71 ; v7(38.75,25.67) 38.77,25.68 40.59,25.68 40.74,25.83 42.19,25.83 arc(42.24,25.81) 42.26,25.76 arc(42.29,25.7) 42.34,25.68 42.36,25.68 arc(42.42,25.7) 42.44,25.76 arc(42.46,25.81) 42.52,25.83 42.54,25.83 arc(42.59,25.81) 42.62,25.76 arc(42.64,25.7) 42.69,25.68 42.72,25.68 arc(42.77,25.7) 42.79,25.76 arc(42.81,25.81) 42.87,25.83 42.89,25.83 arc(42.95,25.81) 42.97,25.76 arc(42.99,25.7) 43.05,25.68 43.07,25.68 arc(43.12,25.7) 43.14,25.76 arc(43.17,25.81) 43.22,25.83 ; 38.35,42.6 37.32,42.6 36.67,41.96 32.16,41.96 31.96,41.76 19.76,41.76 19.34,42.19 18.24,42.19 18.21,42.16 15.61,42.16 15.01,41.56 v3(14.71,41.56) 13.06,41.56 9.51,38.01 9.51,37.81 8.96,37.26 ; 41.62,12.8 35.96,18.46 17.93,18.46 17.92,18.45 17.72,18.45 17.71,18.46 12.61,18.46 12.11,18.96 11.66,18.96 11.51,19.11 11.49,19.11 10.99,19.62 10.3,19.62 9.95,19.97 v3(9.95,20.02) ; v7(30.69,13.85) 30.69,13.47 29.79,12.57 29.79,8.44 28.91,7.55 28.91,7.54 28.9,7.54 28.9,7.45 28.88,7.43 28.88,7.36 ; 7.14,37.98 6.76,37.6 6.8,37.56 6.8,37.36 6.66,37.22 6.47,37.22 6.43,37.26 6.25,37.09 ; 34.82,10.43 29.72,15.54 29.59,15.54 29.59,15.53 28.38,15.53 28.33,15.49 28.33,15.48 28.32,15.48 28.16,15.31 27.77,15.31 27.77,15.32 v7(27.14,15.32) 26.45,16.02 v7(25.75,16.02) 25.52,16.02 25.2,15.69 24.66,15.69 v7(24.38,15.96) ; 44.99,27.23 44.65,26.89 39.79,26.89 39.72,26.82 39.72,26.59 39.93,26.38 40.32,26.38 v7(40.36,26.34) ; v7(33.57,15.68) 33.57,16.34 33.91,16.67 v7(33.97,16.67) ; v3(17.86,10.36) 18.29,9.93 19.23,9.93 20.68,8.48 20.68,6.86 20.85,6.7
  INNER LAYER 5 w0.1: v3(9.73,16.78) 9.86,16.66 9.86,16.56 10.01,16.41 10.2,16.6 10.72,16.6 10.96,16.84 28.12,16.84 28.13,16.85 29.57,16.85 v7(31.34,15.08) 35.25,11.17 ; 15.11,44.56 15.04,44.48 13.89,44.48 ; 9.3,38.77 13.41,42.87 15.14,42.87 ; 9.3,38.77 9.3,38.6 8.34,37.63 8.34,37.39 v3(8.18,37.24) ; 9.3,38.77 9.25,38.71 ; v7(27.11,13.86) 26.83,13.58 26.83,12.71 ; v3(16.46,24.3) 15.76,24.3 15.17,24.89 9.48,24.89 9.41,24.82 9.41,24.76 9.27,24.61 9.2,24.61 6.91,22.32 6.91,20.91 v3(6.98,20.83) ; 5.81,28.31 5.89,28.31 6.39,28.81 ; 19,26.95 19,26.96 19.01,26.96 20.09,26.96 20.7,26.35 27.05,26.35 27.1,26.41 27.1,26.44 27.3,26.64 ; HOLE1.1 38.56,11.72 ; 20.35,46.25 v3(18.26,44.16) ; v7(6.73,36.01) 6.73,37.57 6.76,37.6 ; v7(30.69,13.85) 30.64,13.85 ; 26.08,13.82 26.08,11.62 ; 26.83,12.71 v7(26.94,12.71) ; 26.83,12.71 26.83,10.91 26.57,10.64 26.31,10.64 26.08,10.87 26.08,11.51 ; v7(27.14,15.32) 27.78,15.96 27.89,16.07 28.4,16.07 28.52,15.96 29.76,15.96 34.95,10.76 ; 6.54,34.29 6.67,34.42 6.76,34.42 ; 25.55,14.36 25.17,14.36 25.01,14.52 25.01,14.72 25.12,14.83 25.27,14.83 v7(25.54,14.55) ; v7(8.16,33.66) 8.16,33.68 7.7,34.14 ; 13.89,44.48 11.46,42.06 11.46,41.96 9.81,40.31 9.26,40.31 9.26,40.1 7.14,37.98 ; 13.89,44.48 14.1,44.7
  INNER LAYER 5 w0.102: 26.08,11.62 26.08,11.51
  INNER LAYER 5 w0.2: 9.23,32.68 9.29,32.68 9.29,32.6 9.48,32.6 9.69,32.38 9.69,32.32 13.62,32.32 ; v7(25.27,12.43) 26.08,11.62
  INNER LAYER 5 w0.3: 14.81,44.56 15.89,44.56 15.93,44.6
  INNER LAYER 5 w0.376: 29.14,52.19 CON2.1 ; CON2.1 29.94,51.39 ; CON2.1 29.94,52.99 ; CON2.1 30.75,52.19 ; 17.12,53.26 USB1.8 ; USB1.8 17.12,55.47 ; USB1.8 18.32,54.36 ; USB1.8 15.91,54.36 ; C6277.2 32.35,43.28 ; C6277.2 30.26,43.28 ; C6277.2 31.3,44.32 ; USB1.9 25.52,54.36 ; USB1.9 24.32,53.26 ; USB1.9 24.32,55.47 ; USB1.9 23.11,54.36 ; CON2.3 33.29,54.73 ; CON2.3 32.48,55.53 ; CON2.3 31.68,54.73 ; CON2.3 32.48,53.93 ; 18.27,50.69 USB1.6 ; USB1.6 17.59,51.46 ; USB1.6 18.27,52.24 ; USB1.6 18.94,51.46 ; CON2.2 32.48,52.99 ; CON2.2 31.68,52.19 ; CON2.2 33.29,52.19 ; CON2.2 32.48,51.39 ; HOLE3.1 37.72,37.16 ; HOLE3.1 36.06,38.81 ; HOLE3.1 34.41,37.16 ; CON2.4 29.94,55.53 ; CON2.4 30.75,54.73 ; CON2.4 29.14,54.73 ; CON2.4 29.94,53.93 ; 23.17,50.69 USB1.7 ; USB1.7 22.49,51.46 ; USB1.7 23.17,52.24 ; USB1.7 23.84,51.46
  INNER LAYER 6 w0.076: v7(37.46,12.31) 36.74,13.03 v11(36.66,13.03) ; v11(34.48,15.22) 34.03,15.22 v7(33.57,15.68) ; v7(33.32,14.85) 33.75,14.42 v11(34.26,14.42) ; v7(34.78,16.73) 35.06,16.45 v11(35.06,15.81) ; v7(35.67,16.92) 35.86,16.73 v11(35.86,16.02) ; HOLE1.1 36.25,14.81 v7(38.32,14.81)
  INNER LAYER 6 w0.376: 29.14,54.73 CON2.4 ; CON2.4 29.94,55.53 ; CON2.4 30.75,54.73 ; CON2.4 29.94,53.93 ; 23.17,50.69 USB1.7 ; USB1.7 23.17,52.24 ; USB1.7 23.84,51.46 ; USB1.7 22.49,51.46 ; 30.26,43.28 C6277.2 ; C6277.2 32.35,43.28 ; C6277.2 31.3,44.32 ; C6277.2 31.3,42.24 ; 31.68,52.19 CON2.2 ; CON2.2 32.48,52.99 ; CON2.2 33.29,52.19 ; CON2.2 32.48,51.39 ; CON2.3 32.48,55.53 ; CON2.3 31.68,54.73 ; CON2.3 32.48,53.93 ; CON2.3 33.29,54.73 ; USB1.9 24.32,55.47 ; USB1.9 25.52,54.36 ; USB1.9 23.11,54.36 ; USB1.9 24.32,53.26 ; USB1.8 18.32,54.36 ; USB1.8 17.12,55.47 ; USB1.8 15.91,54.36 ; USB1.8 17.12,53.26 ; 18.27,50.69 USB1.6 ; USB1.6 17.59,51.46 ; USB1.6 18.94,51.46 ; USB1.6 18.27,52.24 ; HOLE3.1 36.06,38.81 ; HOLE3.1 34.41,37.16 ; HOLE3.1 36.06,35.51 ; HOLE3.1 37.72,37.16 ; CON2.1 30.75,52.19 ; CON2.1 29.94,51.39 ; CON2.1 29.14,52.19 ; CON2.1 29.94,52.99
  INNER LAYER 7 w0.076: 29.35,34.76 28.99,35.12 28.99,38.84 30.26,40.11 v7(30.26,40.31) ; 32.1,25.93 32.1,17.61 32.59,17.13 33.16,17.13 33.79,16.5 ; v7(33.97,16.67) 33.9,16.67 33.79,16.56 33.79,16.5 ; 30.64,28.31 30.46,28.31 30.46,34.17 31.55,35.27 31.55,35.27 31.26,35.57 v7(31.11,35.57) ; 20.2,46.83 20.27,46.83 20.64,47.21 20.64,48.47 20.49,48.62 20.47,48.62 20.29,48.8 ; v7(29.45,36.01) 29.45,35.99 29.64,35.8 29.99,35.8 30.31,36.12 30.31,36.44 30.49,36.61 30.74,36.61 30.75,36.6 30.99,36.6 31.13,36.46 31.13,36.26 30.99,36.12 30.86,36.12 30.54,35.8 30.46,35.8 30.6,35.66 30.6,35.46 29.99,34.85 29.99,26.09 30.03,26.06 30.03,25.68 29.99,25.65 29.99,15.91 29.33,15.25 v7(29.29,15.25) ; 22.86,47.56 22.86,47.81 ; HOLE1.1 33.79,16.5 ; 31.51,27.16 31.62,27.05 31.62,26.41 ; 29.45,29.57 29.31,29.57
  INNER LAYER 7 w0.1: v3(18.83,24.13) 18.83,24.54 18.34,25.03 18.13,25.03 v7(18.08,25.08) ; v11(15.06,9.86) 15.06,9.92 17.43,12.29 17.43,12.83 v3(18.73,14.13)
  INNER LAYER 7 w0.376: 32.48,51.39 CON2.2 ; CON2.2 31.68,52.19 ; CON2.2 32.48,52.99 ; CON2.2 33.29,52.19 ; 17.12,53.26 USB1.8 ; USB1.8 18.32,54.36 ; USB1.8 17.12,55.47 ; USB1.8 15.91,54.36 ; 22.49,51.46 USB1.7 ; USB1.7 23.17,50.69 ; USB1.7 23.84,51.46 ; USB1.7 23.17,52.24 ; HOLE3.1 37.72,37.16 ; HOLE3.1 36.06,38.81 ; HOLE3.1 34.41,37.16 ; HOLE3.1 36.06,35.51 ; 29.94,53.93 CON2.4 ; CON2.4 30.75,54.73 ; CON2.4 29.94,55.53 ; CON2.4 29.14,54.73 ; C6277.2 31.3,44.32 ; C6277.2 31.3,42.24 ; C6277.2 32.35,43.28 ; C6277.2 30.26,43.28 ; CON2.1 29.94,52.99 ; CON2.1 29.94,51.39 ; CON2.1 29.14,52.19 ; CON2.1 30.75,52.19 ; USB1.9 25.52,54.36 ; USB1.9 24.32,55.47 ; USB1.9 23.11,54.36 ; USB1.9 24.32,53.26 ; CON2.3 32.48,55.53 ; CON2.3 33.29,54.73 ; CON2.3 32.48,53.93 ; CON2.3 31.68,54.73 ; 17.59,51.46 USB1.6 ; USB1.6 18.94,51.46 ; USB1.6 18.27,52.24 ; USB1.6 18.27,50.69
  INNER LAYER 7 w0.6: 77.03,38.99 76.84,38.99 75.33,37.48 75.33,34.89 76.61,33.61
  INNER LAYER 8 w0.075: v9(34.38,9) 34.53,8.85 34.53,8.64 v7(34.51,8.64)
  INNER LAYER 8 w0.076: v3(36.46,22.66) 36.91,22.66 v2(37.11,22.86) 37.38,22.86 37.57,22.67 37.76,22.67 38.11,23.02 38.49,23.02 38.65,22.86 ; v2(38.41,22.91) 38.46,22.86 38.65,22.86 ; 4.8,14.09 4.73,14.02 4.61,14.02 4.61,14.28 4.59,14.31 4.59,14.36 ; 22.86,11.11 23.04,11.29 23.3,11.29 23.31,11.28 23.46,11.28 23.47,11.27 23.54,11.27 23.56,11.24 23.7,11.24 ; 22.86,11.11 22.86,11.09 22.81,11.04 22.72,11.04 v7(22.51,10.83) 22.53,10.83 v1(22.8,10.56) 23.19,10.56 23.34,10.71 23.35,10.71 23.42,10.78 v7(24.5,10.78) ; 22.86,11.11 22.77,11.2 22.77,11.49 22.77,11.49 22.77,11.69 22.79,11.72 22.79,11.77 22.9,11.88 v2(22.9,12.41) 23.01,12.3 23.43,12.3 23.6,12.47 23.6,13.11 23.63,13.14 23.59,13.18 v2(23.59,13.34) 23.68,13.34 23.95,13.6 23.95,13.86 23.6,14.2 v7(23.32,14.2) 23.75,14.63 24.1,14.63 24.22,14.51 24.22,14.07 24.22,14.01 24.25,13.98 24.25,13.46 24.01,13.22 24.01,13.09 23.9,12.98 23.9,12.33 23.67,12.1 23.67,12.07 23.65,12.05 v2(23.65,11.43) 23.7,11.38 23.7,11.24 ; v14(27.51,13.2) 27.83,13.2 28.69,14.06 v14(28.69,14.28) ; v1(31.82,24.8) 31.83,24.8 v8(32.07,24.56) 32.24,24.56 32.31,24.64 v7(32.4,24.64) ; 29.51,23.18 29.93,23.6 29.93,23.81 29.94,23.82 ; 29.51,23.18 29.91,23.18 30.44,22.65 30.44,22.61 ; 29.51,23.18 29.22,23.18 ; v3(18.55,21.92) 18.66,21.81 18.66,20.86 ; v1(6.32,14.23) 6.32,14.4 5.63,15.08 5.36,14.81 v1(5.31,14.81) ; 18.66,20.86 18.41,20.62 18.1,20.62 17.75,20.97 17.75,21.77 18.09,22.1 18.09,22.43 ; 18.66,20.86 19,20.86 21.34,23.2 21.34,24.48 21.2,24.62 20.93,24.62 20.56,24.26 20.36,24.46 ; v7(12.31,31.25) 12.26,31.21 12.26,30.76 ; 36.09,28.21 v7(36.21,28.21) ; 36.09,28.21 36.27,28.04 ; 36.09,28.21 35.84,28.21 ; 30.1,22.59 29.81,22.59 29.22,23.18 ; v2(32.86,23.16) 32.66,23.16 32.5,23.32 32.5,23.37 ; v2(32.27,27) 32.3,27.03 32.4,27.03 ; 41.74,26.1 40.99,26.1 40.67,26.42 40.67,26.56 40.62,26.61 40.67,26.66 40.67,26.68 41,27.01 41.16,27.01 41.26,26.91 ; 23.7,11.24 23.71,11.25 24.2,11.25 24.31,11.36 24.53,11.36 24.89,10.99 v7(24.89,10.87) ; 8.44,23.31 8.42,23.28 8.19,23.28 7.45,22.55 7.45,21.86 7.46,21.85 7.46,21.67 7.45,21.66 7.45,21.52 7.85,21.12 8.5,21.12 8.7,21.32 9.1,21.32 v1(9.15,21.27) 9.3,21.41 9.34,21.41 9.52,21.58 9.52,21.63 9.65,21.77 9.65,23.1 9.23,23.52 9.14,23.52 9.09,23.56 8.9,23.56 8.9,23.62 v2(8.86,23.62) ; v7(33.52,24) 33.52,23.88 33.49,23.85 31.14,23.85 31.08,23.91 31.06,23.91 30.3,24.67 29.99,24.67 v8(29.86,24.8) 29.86,24.6 29.97,24.49 ; 9.03,14.88 9.03,14.51 9.05,14.49 9.05,14.28 9.03,14.26 9.03,14.13 v1(8.78,13.88) ; 12.27,30.71 12.27,30.71 12.26,30.76 ; 12.27,30.71 12.26,30.76 ; 12.27,30.71 12.19,30.71 12.06,30.58 12.06,30.39 12.19,30.26 12.29,30.26 ; v2(32.6,22.47) 33.04,22.47 v7(33.15,22.58) 32.21,22.58 31.88,22.25 ; v1(6.76,27.91) 7.11,28.26 7.11,28.66 8.24,29.78 8.49,29.78 8.62,29.65 v8(8.62,29.38) 8.88,29.38 8.9,29.4 10.88,29.4 v1(11.53,30.04) ; v3(13.96,30.36) 14.1,30.22 14.1,29.87 13.92,30.05 v1(13.72,30.05) ; v9(29.84,13.01) 29.8,13.01 29.56,13.25 v14(29.36,13.25) ; 39.56,22.86 40.02,22.86 40.13,22.76 40.54,22.76 41.06,22.24 41.06,22.23 41.23,22.07 41.42,22.07 41.6,22.25 41.6,22.77 41.16,23.21 40.31,23.21 40.05,23.47 36,23.47 35.86,23.61 35.46,23.61 35.11,23.96 35.11,24.56 v8(34.77,24.9) 34.39,24.9 v7(34.1,25.2) ; 39.56,22.86 38.65,22.86 ; 39.56,22.86 v2(39.61,22.91) ; v14(29.41,14.04) 29.24,13.87 29.08,13.87 27.68,12.47 27.14,12.47 v14(26.9,12.23) 26.79,12.23 26.71,12.14 ; v7(25.54,14.55) 25.58,14.51 26.11,14.51 26.25,14.37 26.25,13.54 26.15,13.44 26.15,12.85 ; v1(35.06,48.56) 35.72,47.9 v7(38.69,47.9) ; v2(14.4,20.62) 14.35,20.56 14.35,20.54 14.37,20.5 14.38,20.46 14.38,20.42 14.38,20.38 14.36,20.34 14.35,20.33 14.35,20.12 14.4,20.07 14.4,19.42 14.51,19.31 15.5,19.31 ; v1(18.34,47.65) 19.01,47.65 v7(19.05,47.69) ; 29.22,23.18 28.78,23.18 ; v2(32.3,45.01) 32.92,45.63 36.61,45.63 36.76,45.48 v7(36.85,45.48) 38.98,43.35 v9(41.1,43.35) ; 31.23,9.62 31.34,9.62 v1(31.69,9.27) 32.03,8.93 v1(32.39,8.93) 32.87,8.93 33.12,9.18 ; 31.23,9.62 v2(29.83,9.62) 29.53,9.32 v9(27.57,9.32) ; 31.23,9.62 31.23,10.36 30.87,10.72 29.84,10.72 v1(29.47,10.34) 29.47,10.33 29.48,10.33 29.48,10.33 29.48,10.33 29.48,10.31 v2(29.5,10.31) ; v2(40.86,21.86) 40.76,21.76 40.26,21.76 40,22.02 34.81,22.02 34.79,22.05 34.73,22.05 33.96,22.82 v1(33.86,22.82) 33.75,22.82 33.6,22.96 33.2,22.96 33.07,23.09 33.07,23.37 32.5,23.37 ; v14(30.53,15.32) 30.47,15.26 30.09,15.26 30.06,15.23 30.04,15.23 ; v7(9.25,19.22) 9.29,19.18 9.29,18.82 9.34,18.87 10.53,18.87 10.6,18.94 10.6,19.89 11.13,20.42 11.55,20.42 11.86,20.11 11.86,19.79 11.8,19.74 v2(11.8,19.25) 11.8,19.17 12,18.97 ; v1(24.62,14.23) 24.57,14.18 24.57,13.81 24.88,13.5 24.95,13.5 24.99,13.46 25.02,13.46 25.15,13.33 25.15,13.23 25.29,13.09 25.45,13.09 25.45,12.13 25.37,12.05 v14(25.29,12.05) 25.29,12.41 v7(25.27,12.43) ; v8(31.37,25.72) 31.33,25.72 31.33,25.74 31.35,25.77 v8(31.57,25.55) 31.64,25.55 v7(31.82,25.36) ; 26.15,12.85 26.15,12.48 v14(26.07,12.41) ; 26.15,12.85 26.15,12.86 v14(26.15,12.93) ; v3(9.23,18.04) 9.23,17.63 9.51,17.36 9.51,17.13 9.73,17.13 v3(9.73,16.78) 9.89,16.63 9.89,16.12 10.02,15.98 10.02,15.79 9.88,15.65 9.78,15.65 v1(9.78,15.38) 9.53,15.63 9.08,15.63 8.98,15.53 8.48,15.53 v2(8.38,15.63) ; 41.72,25.55 v3(41.7,25.52) ; 32.5,23.37 30.96,23.37 30.9,23.43 30.88,23.43 30.49,23.82 29.94,23.82 ; 33,27.62 32.4,27.03 ; 33,27.62 33.59,28.22 v8(33.73,28.22) 33.75,28.23 v8(34.08,28.23) ; 33,27.62 32.89,27.73 v2(32.89,27.75) ; 32.4,27.03 32.4,26.6 32.13,26.33 ; 21.3,13.05 21.3,12.88 21.03,12.61 ; v8(31.82,25.79) 31.97,25.79 v7(32.11,25.65) 32.43,25.65 32.86,26.09 32.86,26.85 33.72,27.7 34.76,27.7 v8(35.32,27.14) ; 33.12,9.18 33.22,9.28 33.22,9.78 31.74,11.26 29.44,11.26 v9(29,10.82) 28.91,10.82 28.67,10.58 28.08,10.58 27.84,10.81 27.58,10.81 v8(27.57,10.81) 27.57,10.81 v8(27.08,10.81) ; 33.12,9.18 33.24,9.18 v7(33.3,9.11) ; v8(31.32,25.3) 31.32,25.3 v1(30.82,25.3) 30.82,25.25 v7(30.61,25.04) 30.68,25.04 30.83,24.9 v1(30.83,24.8) ; 30.69,13.96 31.21,13.96 32.96,12.21 ; 15.5,19.31 16.58,19.31 16.71,19.44 v1(16.93,19.44) 16.73,19.64 16.73,19.96 16.86,20.09 16.86,21.09 16.68,21.27 16.28,21.27 15.65,20.64 v3(15.65,20.37) 15.65,19.47 15.5,19.31 ; v7(36.21,27.16) 35.77,26.72 v8(35.29,26.72) ; 19.4,25.47 19.38,25.47 v7(19.11,25.21) 19.01,25.11 18.46,25.11 18.32,24.97 18.32,24.81 18.29,24.81 18.11,24.64 18.11,24.56 17.99,24.56 17.85,24.42 17.85,24.22 17.99,24.08 18.23,24.08 18.31,24.16 18.59,24.16 18.62,24.13 18.62,24.1 18.8,24.1 v3(18.83,24.13) ; v3(41.42,26.44) 41.65,26.44 41.73,26.51 ; 12.29,30.26 12.31,29.73 v2(12.35,29.73) 12.31,30.26 12.29,30.26 ; v2(27.11,14.68) 26.73,14.3 26.73,13.25 27.17,12.8 27.17,12.62 27.04,12.48 26.79,12.48 26.72,12.4 26.72,12.22 26.71,12.21 26.71,12.14 ; 18.33,23.04 18.4,22.97 v3(18.4,22.57) ; 26.71,12.14 26.6,12.04 26.6,11.86 v8(26.58,11.84) ; v1(10.72,16.41) 10.55,16.24 10.55,15.62 v1(10.78,15.38) 10.68,15.38 10.43,15.13 10.41,15.13 10.39,15.12 10.07,15.12 10.03,15.08 10.03,15.01 10.05,14.99 10.05,14.67 10.08,14.63 10.98,14.63 11.13,14.78 11.35,14.78 11.54,14.97 11.67,14.97 12.13,15.43 12.19,15.43 12.38,15.63 ; v1(22.76,25.16) 23.6,24.32 26.65,24.32 27.2,23.77 ; v3(40.97,26.55) 41.17,26.74 ; 29.94,23.82 29.75,23.82 29.32,24.25 29.32,24.43 29.3,24.45 29.3,25.41 29.62,25.73 29.78,25.73 v8(29.84,25.79) ; 10.11,17.56 10.11,17.51 10.26,17.35 10.26,17.31 10.65,16.91 v3(10.65,16.73) 11.33,17.41 11.33,18.03 11.13,18.23 10.88,18.23 10.72,18.07 10.7,18.07 10.64,18.02 10.1,18.02 9.98,17.9 9.98,17.68 10.11,17.56
  INNER LAYER 8 w0.1: v7(26.76,36.86) 25.91,36.86 24.66,38.11 22.69,38.11 21.66,37.09 21.66,36.71 21.41,36.46 18.11,36.46 v2(18.01,36.36) ; v7(25,10.14) 25.08,10.06 v8(25.35,10.06) 25.42,10.13 25.75,10.13 25.82,10.06 v1(25.84,10.06) ; v1(26.58,9.32) 26.58,9.04 26.41,8.87 26.41,8.73 26.32,8.65 26.32,8.56 ; v7(29.73,13.86) 29.66,13.93 29.66,14.44 ; v3(16.23,16.43) 16.54,16.12 16.54,14.6 16.96,14.18 v2(16.98,14.18) ; v3(6.98,11.33) 7.43,10.88 7.43,10.08 7.98,9.53 10.38,9.53 10.78,9.93 v2(10.88,9.93) ; v2(13.28,9.33) 13.28,8.93 12.61,8.26 9.52,8.26 9.52,7.39 v3(9.06,6.92) ; v1(17.31,45.81) 18.26,44.86 v3(18.26,44.16) ; v14(28.15,12.83) 28.12,12.86 28.07,12.86 ; v8(25.34,10.57) 25.04,10.87 v7(24.89,10.87) ; v14(29.97,15.23) 30.69,14.5 30.69,13.96 ; v7(25.96,24.91) 26.01,24.86 26.71,24.86 27.36,24.21 27.36,23.71 27.89,23.18 28.78,23.18 ; 13.13,17.18 14.63,17.18 15.13,17.68 ; 13.13,17.18 13.18,17.23 ; 13.13,17.18 12.18,16.23 12.18,16.18 11.44,15.44 11.35,15.44 11.3,15.38 v1(10.78,15.38) ; 14.98,16.58 13.71,16.58 13.69,16.61 13.37,16.61 13.35,16.58 13.33,16.58 12.38,15.63 ; 5.67,20.35 5.63,20.39 v1(5.25,20.39) ; v7(27.75,11.08) 27.57,10.9 v8(27.57,10.81) ; 6.54,20.39 v3(6.98,20.83) ; v3(19.15,13.07) 20.04,13.96 v7(20.07,13.96) 19.88,14.15 v7(19.88,16.58) ; v9(25.1,7.33) 25.23,7.46 25.23,8.17 25.35,8.29 25.35,8.52 25.61,8.77 25.63,8.77 25.73,8.87 25.73,8.89 25.84,9 25.84,9.09 v1(25.82,9.09)
  INNER LAYER 8 w0.102: v14(29.97,15.23) 30.04,15.23 30.08,15.27 30.14,15.27 30.14,15.3 30.04,15.41 29.89,15.41 29.54,15.06 29.54,14.44 ; v14(28.69,14.28) 28.75,14.34 29.15,14.34 29.34,14.53 29.43,14.44 29.54,14.44 ; 29.54,14.44 29.66,14.44 ; 29.54,14.44 29.54,14.17 v14(29.41,14.04) ; v7(30.69,13.85) 30.69,13.96
  INNER LAYER 8 w0.15: v3(10.28,12.94) 10.28,13.38 v1(10.29,13.38) ; v2(11.67,9.36) 11.66,9.36 11.66,9.42 11.8,9.56 12.12,9.56 ; v11(11.26,7.35) 10.95,7.35 9.83,6.23 9.59,6.23 v7(9.01,5.66) ; 34.75,32.72 35.07,32.72 ; 20.92,32.93 20.55,32.57 20.43,32.57 20.69,32.31 20.69,32.17 ; 22.56,23.06 22.71,23.21 v1(26.01,23.21) 26.24,23.21 28.49,20.96 38.51,20.96 42.76,16.71 42.86,16.71 43.06,16.51 45.5,16.51 ; v1(33.86,22.82) 33.73,22.95 33.41,22.95 33.41,23.11 v2(33.31,23.21) ; 41.74,26.1 41.81,26.17 41.89,26.09 41.89,26.03 v2(41.81,26.03) ; 17.38,10.52 17.59,10.74 v1(17.58,10.74) ; v1(22.41,22.16) 22.71,22.16 22.78,22.08 22.78,21.93 23.43,21.28 23.93,21.28 24.31,20.91 v2(24.56,20.91) 26.13,20.91 27.78,19.26 37.76,19.26 ; v7(9.88,7.24) 9.84,7.27 9.81,7.27 9.81,6.95 ; v7(34.1,25.2) 34.1,25.4 v8(33.91,25.59) ; v7(34.29,24.04) 34.16,24.04 v8(34,23.88) ; 17.01,10.16 15.99,10.16
  INNER LAYER 8 w0.2: v8(27.86,23.71) 27.86,23.91 27.91,23.96 v3(27.91,24.11) ; v7(24.75,12.47) 24.85,12.37 24.85,12.19 24.87,12.17 v8(24.87,12.04) ; v7(30.61,29.16) 30.66,29.16 v9(30.86,28.96) ; v1(25.75,15.62) v7(25.75,16.02) ; v1(27.1,16.52) 26.75,16.52 v7(26.7,16.47)
  INNER LAYER 8 w0.22: v1(10.72,16.41) 10.76,16.41 10.78,16.43 10.78,16.6 v3(10.65,16.73) ; v1(8.78,14.88) 9.28,14.88 v1(9.78,15.38)
  INNER LAYER 8 w0.25: v7(21.77,13.39) 21.34,13.39 21.34,13.74 ; v7(22.08,16.2) 22.06,16.2 v1(21.84,15.98) ; v1(8.78,13.88) 6.53,13.88 v1(6.31,13.66)
  INNER LAYER 8 w0.3: 32.3,34.69 32.3,34.61 32.68,34.23 32.83,34.23 32.83,34.19 ; 8.91,20.66 8.66,20.92 v1(8.56,20.92) ; v1(18.4,15.78) v3(19.04,15.78) ; 32.83,34.19 32.94,34.19 32.94,34.16 v7(32.93,34.16) ; 32.83,34.19 32.83,34.08 33,33.91 33.24,33.91 v7(33.24,33.81) ; v1(21.26,1.85) 21.26,3.16 v7(21.18,3.24) ; v2(16.98,14.18) 17.28,13.88 17.28,13.38 16.87,12.97 v1(16.58,12.97) ; v1(28.01,26.11) 28.01,26.46 v3(27.96,26.46) ; v1(6.48,17.73) 6.38,17.73 5.78,17.13 5.78,16.18 6.32,15.65 v1(6.32,15.48) 6.92,14.88 v1(8.78,14.88) ; v7(8.55,10.23) 8.59,10.27 8.59,10.29 8.72,10.42 v1(8.98,10.42) ; v2(13.28,14.83) v3(12.83,14.83) ; v1(24.43,29.98) 24.13,29.98 v2(24.02,30.09) ; v7(35.08,33.45) 35.39,33.14 v1(35.39,32.97) ; v3(16.23,16.43) 15.9,16.77 v1(15.83,16.77) ; v2(30.86,22.16) 30.56,22.16 v7(30.51,22.21) ; v3(11.98,12.48) 11.78,12.68 v1(11.78,12.88) ; v1(21.68,14.43) 21.91,14.2 ; v2(8.38,15.63) 8.03,15.63 v3(7.88,15.78) ; v7(20.26,22.73) 19.9,22.36 19.75,22.36 20.17,22.78 20.27,22.78 ; v3(17.73,17.68) 17.94,17.48 v1(17.94,17.06) ; v3(16.95,19.87) 16.93,19.84 v1(16.93,19.44) 16.57,19.08 16.33,19.08 16.33,18.83 16.76,18.41 v1(16.93,18.41) ; v3(13.07,19.82) 13.1,19.82 13.36,19.56 v8(13.37,19.56) ; v2(10.88,9.93) 11.37,10.42 v1(11.48,10.42) ; v8(13.38,20.13) 13.38,20.19 v3(13.1,20.47) ; v1(14.75,13.96) 14.75,13.95 v3(14.98,14.18) ; v3(8.45,24.57) 8.45,24.47 8.36,24.37 v2(8.36,24.26) ; v7(34.46,33.46) 34.32,33.46
  INNER LAYER 8 w0.35: v2(21.57,12.67) 21.57,12.78 21.3,13.05 v7(20.83,13.05)
  INNER LAYER 8 w0.376: USB1.6 18.94,51.46 ; USB1.6 18.27,52.24 ; USB1.6 18.27,50.69 ; USB1.6 17.59,51.46 ; USB1.7 23.84,51.46 ; USB1.7 22.49,51.46 ; USB1.7 23.17,52.24 ; USB1.7 23.17,50.69 ; 24.32,53.26 USB1.9 ; USB1.9 23.11,54.36 ; USB1.9 24.32,55.47 ; USB1.9 25.52,54.36 ; CON2.1 30.75,52.19 ; CON2.1 29.94,51.39 ; CON2.1 29.14,52.19 ; CON2.1 29.94,52.99 ; 31.68,52.19 CON2.2 ; CON2.2 32.48,52.99 ; CON2.2 32.48,51.39 ; CON2.2 33.29,52.19 ; 30.26,43.28 C6277.2 ; C6277.2 32.35,43.28 ; C6277.2 31.3,42.24 ; C6277.2 31.3,44.32 ; CON2.4 30.75,54.73 ; CON2.4 29.94,53.93 ; CON2.4 29.94,55.53 ; 34.41,37.16 HOLE3.1 ; HOLE3.1 37.72,37.16 ; HOLE3.1 36.06,38.81 ; CON2.3 32.48,55.53 ; CON2.3 31.68,54.73 ; CON2.3 33.29,54.73 ; CON2.3 32.48,53.93 ; USB1.8 17.12,55.47 ; USB1.8 17.12,53.26 ; USB1.8 18.32,54.36 ; USB1.8 15.91,54.36
  INNER LAYER 8 w0.4: v3(8.94,20.61) 8.94,20.64 8.91,20.66 v2(8.41,20.66)
  INNER LAYER 9 w0.076: v1(9.78,15.38) 9.78,15.43 9.63,15.58 9.03,15.58 ; 9.33,16.48 9.33,16.28 9.48,16.13 10.03,16.13 ; 9.33,16.48 9.58,16.73 9.58,17.13 9.23,17.48 v1(8.83,17.48) ; 9.33,16.48 9.23,16.38 9.13,16.48 9.08,16.48 ; v1(9.33,19.23) 9.28,19.18 8.68,19.18 8.52,19.02 8.52,18.79 8.53,18.77 8.53,17.78 v1(8.83,17.48) ; 9.08,16.48 8.93,16.63 8.63,16.63 8.53,16.73 8.53,17.18 v1(8.83,17.48) ; 9.08,16.48 9.03,16.43 9.03,15.58 ; v2(35.41,26.21) 35.55,26.35 ; 10.03,16.13 v1(10.28,15.88) v1(10.78,15.38) ; 10.03,16.13 10.03,17.83 v1(10.08,17.88) 10.93,17.88 11.38,17.43 11.38,17.07 v1(10.72,16.41) 10.72,16.35 10.95,16.12 11.5,16.12 11.78,15.83 ; v8(31.32,24.8) 30.83,24.8 v1(30.83,24.8) ; v1(29.3,27.36) 29.38,27.36 29.38,26.32 29.84,25.87 v8(29.84,25.79) ; 35.55,30.74 36.8,31.99 ; v1(31.34,40.37) v2(30.91,40.31) ; v1(36.5,27.64) 36.53,27.64 36.51,27.66 ; v1(8.78,15.38) 8.98,15.58 9.03,15.58 ; v1(27.94,12.09) 27.73,12.09 v1(27.47,12.35) ; v8(29.86,24.8) v4(30.33,24.8) 30.83,24.8 ; v8(35.25,22.66) v2(35.56,22.66)
  INNER LAYER 9 w0.1: 30.28,25.79 v1(30.33,25.79) v1(30.83,25.79) 30.82,25.79 v1(30.82,25.3) 31.32,25.3 v8(31.32,25.3) ; v8(31.32,25.3) 31.33,25.3 v8(31.57,25.05) ; v8(31.32,25.3) 31.32,25.67 v8(31.37,25.72) 31.74,25.72 v8(31.82,25.79) ; v8(31.32,25.3) 31.57,25.54 v8(31.57,25.55) ; v8(31.32,24.8) U11.26 v8(31.57,25.05) ; v8(31.57,25.05) v1(31.82,24.8) 31.83,24.8 v8(32.07,24.56)
  INNER LAYER 9 w0.15: v1(24.25,17.26) 23.73,17.78 23.73,17.78 23.18,17.78 23.08,17.88 22.93,17.88 21.34,19.48 21.34,19.52 21.22,19.63 21.18,19.63 21.03,19.78 21.03,22.24 21.4,22.61 v1(22.51,22.61)
  INNER LAYER 9 w0.2: v1(21.84,15.98) 21.84,15.99 22.03,16.18 22.03,16.53 21.73,16.83 20.89,16.83 v1(20.31,17.41) ; v8(25.34,10.57) 25.36,10.57 v4(25.59,10.81) ; v1(26.92,8.32) 27.17,8.07 v2(27.17,8.01)
  INNER LAYER 9 w0.25: 12.53,14.63 13.13,14.63
  INNER LAYER 9 w0.3: v1(3.13,18.31) 3.16,18.31 3.51,17.96 5.11,17.96 v1(5.46,18.31) ; v2(18.32,28.7) v2(18.32,29.13) 18.32,29.31 18.03,29.61 v1(18.03,29.81) ; v1(10.88,10.42) v2(10.88,9.93) ; v2(30.86,22.16) 31.01,22.01 v1(31.26,22.01) ; v1(2.88,30.81) 3.01,30.81 5.76,28.06 6.57,28.06 6.72,27.91 v1(6.76,27.91) ; v1(3.03,37.11) 3.43,37.52 4.1,37.52 5.09,38.51 ; v1(12.28,14.38) 12.53,14.63 ; 13.13,14.63 13.13,14.68 v2(13.28,14.83) ; v1(40.19,26.93) 40.19,26.8 v2(39.93,26.54) ; v2(17.73,23.48) 17.95,23.7 v1(18.04,23.7) 18.42,23.7 v1(18.64,23.48) ; v2(24.02,30.09) 23.86,30.26 v1(23.66,30.26) 23.66,30.05 ; v2(6.21,38.51) 6.56,38.51 6.71,38.36 ; v1(8.78,15.38) 8.63,15.38 v2(8.38,15.63) ; v1(18.03,30.41) 18.03,30.63 ; v2(7.93,28.04) 7.58,28.4 v1(7.58,28.41) ; v1(17.43,14.68) 16.98,14.23
  INNER LAYER 9 w0.376: 32.48,53.93 CON2.3 ; CON2.3 33.29,54.73 ; CON2.3 32.48,55.53 ; CON2.3 31.68,54.73 ; 35.86,12.27 HOLE1.1 ; HOLE1.1 38.02,14.42 ; HOLE1.1 33.71,14.42 ; HOLE1.1 35.86,16.57 ; CON2.4 29.94,55.53 ; CON2.4 30.75,54.73 ; CON2.4 29.94,53.93 ; CON2.4 29.14,54.73 ; USB1.7 23.17,52.24 ; USB1.7 23.84,51.46 ; USB1.7 22.49,51.46 ; USB1.7 23.17,50.69 ; 24.32,53.26 USB1.9 ; USB1.9 23.11,54.36 ; USB1.9 24.32,55.47 ; USB1.9 25.52,54.36 ; 32.48,51.39 CON2.2 ; CON2.2 32.48,52.99 ; CON2.2 33.29,52.19 ; CON2.2 31.68,52.19 ; HOLE3.1 36.06,38.81 ; HOLE3.1 37.72,37.16 ; HOLE3.1 36.06,35.51 ; HOLE3.1 34.41,37.16 ; 29.94,51.39 CON2.1 ; CON2.1 29.94,52.99 ; CON2.1 30.75,52.19 ; CON2.1 29.14,52.19 ; USB1.6 18.94,51.46 ; USB1.6 17.59,51.46 ; USB1.6 18.27,50.69 ; USB1.6 18.27,52.24 ; 31.3,42.24 C6277.2 ; C6277.2 30.26,43.28 ; C6277.2 31.3,44.32 ; USB1.8 17.12,55.47 ; USB1.8 17.12,53.26 ; USB1.8 18.32,54.36 ; USB1.8 15.91,54.36
  INNER LAYER 9 w1: 41.36,27.7 41.36,30.9
  BOTTOM w0.064: 22.77,9.92 22.86,9.83 22.86,9.79
  BOTTOM w0.076: v8(29.86,24.8) 30.33,24.8 U11.24 ; v1(41.58,24.16) 41.58,23.98 41.22,23.62 41.22,23.15 41.01,22.94 ; v1(27.25,53.48) 27.38,53.61 27.38,53.74 ; v1(13.13,9.23) 12.64,9.23 12.28,9.58 ; C374.1 7.42,25.47 ; 7.42,25.47 7.14,25.75 7.05,25.75 6.98,25.68 v8(6.72,25.68) ; 7.42,25.47 6.82,25.47 6.82,25.43 v8(6.72,25.43) ; v11(15.18,6.63) 15.39,6.84 ; v1(9.03,19.78) 9.29,19.78 9.41,19.67 ; v8(21.36,32.35) 21.36,32.31 21.38,32.3 21.38,31.95 ; v1(27.04,7.61) 26.92,7.73 v1(26.92,8.32) 26.83,8.41 ; 27.29,45.53 27.29,45.22 v1(27.27,45.2) ; v1(5.98,19.41) 5.98,19.62 6.15,19.78 C6371.2 ; 30.95,14.49 30.95,14.41 30.95,14.41 30.95,14.07 30.36,13.47 30.28,13.47 30.09,13.28 30.09,13.2 30.01,13.12 29.98,13.12 29.84,12.99 C280.2 29.84,12.95 29.73,12.95 29.49,13.18 28.39,13.18 28.32,13.11 28.32,12.47 v1(27.94,12.09) ; v1(9.33,19.23) 9.38,19.18 9.38,18.9 ; U18.19 v8(25.35,10.06) ; v4(24.7,13.26) 24.7,13.26 24.63,13.19 24.63,12.84 24.57,12.84 24.5,12.78 24.42,12.78 ; 33.96,23.86 33.92,23.95 ; v8(24.87,12.04) 24.85,12.04 U18.1 24.7,12.04 24.71,12.05 24.71,12.25 24.57,12.39 ; 29.84,25.79 U11.45 ; U18.78 v8(27.57,10.81) 27.68,10.81 27.77,10.72 27.77,10.72 27.92,10.57 27.93,10.57 27.99,10.51 28.68,10.51 28.99,10.82 ; 41.05,41.8 41.19,41.94 41.29,41.94 41.33,41.98 v8(41.37,41.98) ; v11(34.77,49.89) 34.05,49.17 34.05,41.24 34.05,41.24 34.05,40.71 34.55,40.22 C6283.1 ; C6274.1 20.1,22.04 19.53,22.04 v1(19.38,22.18) ; 12.98,7.02 12.96,7.02 12.78,6.84 12.65,6.84 v11(12.13,6.33) ; v1(30.83,25.79) U11.48 ; v8(24.82,9.54) 24.84,9.56 U18.6 ; 37.37,9.08 v1(37.45,9.17) ; v1(27.47,12.35) 27.52,12.35 28,12.83 28,13.44 28.33,13.77 28.33,13.78 28.39,13.85 28.41,13.85 28.54,13.98 v1(29.06,13.98) ; v1(24.86,1.85) 24.86,1.86 ; U11.17 32.31,24.31 ; 16.06,7.36 15.76,7.06
  BOTTOM w0.1: v1(30.83,24.8) U11.24 ; v1(30.83,24.8) U11.26 ; v1(30.83,24.8) U11.36 ; D32.2 15.58,7.36 16.06,7.36 16.06,7.16 15.53,6.63 v11(15.18,6.63) ; D37.2 v1(17.31,45.81) ; v1(26.28,8.44) 26.28,8.36 26.2,8.28 26.2,7.17 26.42,6.95 v1(26.5,6.95) ; U11.36 U11.37 ; U11.36 v1(30.83,25.79) v1(30.33,25.79) 29.84,25.79 v8(29.84,25.79) ; v1(35.06,48.56) 35.13,48.56 ; U11.17 U11.22
  BOTTOM w0.15: v1(32.78,23.77) 32.78,23.77 32.74,23.81 U11.6 ; v8(31.82,25.79) v8(31.57,25.55) ; v8(31.57,25.55) 31.33,25.79 31.33,25.72 v8(31.37,25.72) ; v8(31.57,25.55) U11.37 v8(31.32,25.3) 31.33,25.3 v8(31.57,25.05) ; U11.22 31.82,24.8 v1(31.82,24.8) v8(31.57,25.05) ; v9(27.95,9.37) 27.96,9.36 28.18,9.36 28.21,9.33 v9(28.27,9.33) ; 33.96,23.86 33.82,24 33.82,24.05 33.56,24.31 U11.17 ; v8(29.86,24.8) 29.72,24.8 v1(29.18,25.34) 29.29,25.34 29.74,25.79 v8(29.84,25.79) ; v4(27.33,9.57) v9(27.57,9.32) ; v8(32.07,24.56) 32.07,24.55 ; v8(31.32,24.8) U11.26 v8(31.57,25.05)
  BOTTOM w0.2: v1(35.65,7.47) 35.6,7.42 v1(35.6,7.03) 35.27,7.03 v1(35.15,6.92) ; v1(32.99,6.85) 32.99,7.3 v1(33.15,7.47) 33.35,7.47 33.55,7.27 34.05,7.27 v1(34.1,7.32) ; v1(32.99,6.85) 33.78,6.85 L28.2 ; v1(32.99,6.85) 32.5,6.85 v1(32.4,6.95) ; U19.9 22.86,15.91 22.93,15.83 ; C6274.1 19.86,22.11 v1(19.48,22.48) ; 28,6.95 27.55,6.95 27.55,7.01 ; v1(34.25,6.92) 34.22,6.89 v1(33.8,6.89) 33.8,7.12 33.7,7.22 ; v1(30.5,6.92) 30.69,6.73 v1(30.95,6.73) 31.02,6.73 v1(31.35,7.07) ; v1(30.15,9.22) 30.06,9.12 v1(29.68,9.12) ; v1(38.35,6.4) 38.69,6.4 v1(38.75,6.47) ; v1(38.35,6.4) 38.35,5.62 v9(38.52,5.45) ; v1(38.35,6.4) 37.92,6.4 v1(37.85,6.47) ; v1(29.05,6.73) v1(29.05,7.12) ; v1(29.05,6.73) 29.29,6.73 29.4,6.62 ; v1(29.05,6.73) 28.54,6.73 v1(28.45,6.82) 28.44,6.82 28.29,6.97 v9(28,6.97) ; U22.2 31.43,8.44 31.25,8.27 31,8.27 30.8,8.07 v1(30.15,8.07) v1(29.85,8.07) v1(29.5,8.07) v1(29.15,8.07) v1(28.75,8.07) v1(28.35,8.07) v1(28,8.07) ; U22.2 32.39,7.53 v1(32.45,7.47) 32.4,7.42 v1(32.4,6.95) ; U22.2 32.39,9.24 v4(32.47,9.32) ; v1(29.68,9.12) 29.36,9.12 v1(29.25,9.02) ; v1(29.68,9.12) 29.68,9.33 v9(29.51,9.5) ; v1(36.6,7.52) 36.7,7.52 v1(37,7.82) ; v1(32.4,6.95) v1(32.4,6.18) 32.4,5.62 v1(32.35,5.57) ; v1(37.37,8.37) 37.37,8.73 v1(37.5,8.87) ; v1(37.37,8.37) 37.37,8.03 v1(37.3,7.97) ; v1(37.37,8.37) 37.55,8.37 v1(37.8,8.62) ; 23.99,7.01 23.69,6.7 23.5,6.7 v1(23.34,6.54) ; U18.49 v8(26.58,11.84) ; v1(35.35,7.87) 35.24,7.75 v1(34.95,7.75) 34.95,7.47 v1(34.85,7.37) ; v1(29.4,7.12) 29.57,6.95 v1(29.8,6.95) 30.22,6.95 v1(30.25,6.92) ; v1(34.25,9.42) 34.38,9.29 v9(34.38,9) 34.8,9 v9(34.8,9) ; 33.92,23.95 v8(34,23.88) ; v1(34.5,7.32) 34.36,7.46 v9(34.36,7.73) ; v9(30.86,28.96) G18.1 ; v4(25.35,9.57) v4(25.1,9.32)
  BOTTOM w0.25: U19.5 21.29,16.27 21.66,15.91 U19.9
  BOTTOM w0.3: 19.59,28.24 19.53,28.24 19.24,28.53 v1(19.24,28.98) ; v1(33.86,22.82) 33.86,22.76 33.88,22.74 ; 41.33,49.73 41.3,49.71 41.3,47.86 41.44,47.72 ; U6838.J1 13.03,12.88 13.18,12.73 ; v1(24.83,7.32) 24.82,7.3 24.55,7.3 ; v1(10.18,10.42) v1(10.88,10.42) ; R61.1 40.41,24.47 40.06,24.82 40.06,24.97 ; 17.2,19.72 v1(16.93,19.44) ; 6.32,13.63 v1(6.32,14.23) v1(6.32,15.48) ; v1(19.13,31.52) 19.13,31.37 18.79,31.03 v1(18.42,31.03) 18.03,30.64 v1(18.03,30.41)
  BOTTOM w0.376: CON2.1 30.75,52.19 ; CON2.1 29.94,52.99 ; CON2.1 29.14,52.19 ; CON2.1 29.94,51.39 ; CON2.3 32.48,55.53 ; CON2.3 31.68,54.73 ; CON2.3 32.48,53.93 ; CON2.3 33.29,54.73 ; USB1.9 25.52,54.36 ; USB1.9 24.32,53.26 ; USB1.9 23.11,54.36 ; USB1.9 24.32,55.47 ; 29.95,43.28 C6277.2 ; C6277.2 31.3,44.63 ; C6277.2 31.3,41.93 ; USB1.7 23.17,52.24 ; USB1.7 22.49,51.46 ; USB1.7 23.84,51.46 ; USB1.7 23.17,50.69 ; 29.94,53.93 CON2.4 ; CON2.4 30.75,54.73 ; CON2.4 29.94,55.53 ; 15.91,54.36 USB1.8 ; USB1.8 17.12,53.26 ; USB1.8 18.32,54.36 ; USB1.8 17.12,55.47 ; 31.68,52.19 CON2.2 ; CON2.2 32.48,51.39 ; CON2.2 32.48,52.99 ; CON2.2 33.29,52.19
  BOTTOM w0.4: 41.44,47.43 41.44,47.72
  BOTTOM w0.6: R6547.1 29.86,54.81 CON2.4
  vias: v1(4.91,17.4) v1(5.28,17.48) v1(5.31,42.86) v1(5.36,38.96) v1(5.36,27.36) v1(5.36,24.86) v1(5.36,22.56) v1(5.31,19.66) v1(5.38,16.18) v1(5.36,15.51) v1(5.31,14.01) v1(5.41,41.96) v1(5.46,40.71) v1(5.46,40.01) v1(5.46,37.16) v1(5.41,36.11) v1(5.46,35.41) v1(5.46,34.81) v1(5.41,34.06) v1(5.41,33.01) v1(5.46,32.21) v1(5.46,31.51) v1(5.46,30.61) v1(5.41,28.26) v1(5.46,26.71) v1(5.41,25.76) v1(5.41,23.41) v1(5.46,21.51) v1(5.41,20.96) v1(5.43,19.27) v1(5.41,16.86) v1(5.46,13.01) v1(5.46,11.96) v1(5.46,11.51) v1(5.51,41.41) v1(5.51,39.41) v1(5.51,29.76) v1(5.51,24.06) v1(5.51,12.51) v1(5.71,10.71) v1(5.98,17.68) v1(6.06,42.81) v1(6.26,27.61) v1(6.26,26.96) v1(6.26,25.86) v1(6.28,18.43) v1(6.28,12.33) v1(6.36,34.01) v1(6.33,18.48) v1(6.33,16.08) v1(6.33,12.98) v1(6.33,11.73) v1(6.46,35.16) v1(6.41,33.41) v1(6.41,32.91) v1(6.41,32.16) v1(6.46,31.51) v1(6.41,24.91) v1(6.46,23.51) v1(6.43,19.88) v1(6.56,26.36) v1(6.56,23.91) v1(6.66,36.71) v1(6.66,35.96) v1(6.81,30.69) v1(6.86,27.36) v1(6.81,26.91) v1(7.11,39.66) v1(7.11,32.36) v1(7.41,36.81) v1(7.41,35.86) v1(7.41,33.51) v1(7.44,28.97) v1(7.46,20.71) v1(7.43,13.63) v1(7.48,12.38) v1(7.56,27.11) v1(7.53,18.9) v1(7.53,18.88) v1(7.58,15.53) v1(7.61,30.81) v1(7.78,11.93) v1(7.81,42.76) v1(7.83,20.28) v1(7.91,35.26) v1(7.91,32.86) v1(7.91,31.76) v1(7.95,22.66) v1(7.91,20.76) v1(7.98,17.78) v1(8.01,30.05) v1(8.31,38.36) v1(8.56,42.71) v1(8.56,37.51) v1(8.66,39.11) v1(8.78,12.88) v1(9.26,42.71) v1(9.31,38.76) v1(9.35,28.82) v1(9.33,20.33) v1(9.5,28.12) v1(9.55,46.02) v1(9.58,30.04) v1(9.66,38.81) v1(9.61,32.26) v1(9.61,31.81) v1(9.98,19.13) v1(9.93,11.73) v1(10.36,42.61) v1(10.68,11.63) v1(10.76,44.51) v1(10.71,37.41) v1(10.81,39.26) v1(10.88,20.63) v1(10.88,19.18) v1(11.2,45.7) v1(11.24,26.28) v1(11.28,18.98) v1(11.31,23.76) v1(11.46,23.16) v1(11.52,44.16) v1(11.51,42.81) v1(11.78,20.63) v1(11.73,8.84) v1(11.86,39.31) v1(11.83,18.88) v1(11.96,44.97) v1(12.08,23.89) v1(12.08,10.43) v1(12.31,38.91) v1(12.34,24.34) v1(12.51,45.71) v1(12.46,42.66) v1(12.41,23.11) v1(12.58,19.28) v1(12.68,11.63) v1(12.78,10.43) v1(12.73,9.33) v1(13.29,30.7) v1(13.26,26.31) v1(13.36,38.56) v1(13.39,25.38) v1(13.4,23.09) v1(13.38,18.9) v1(13.38,10.43) v1(13.46,42.66) v1(13.43,18.88) v1(13.56,40.81) v1(13.51,37.46) v1(13.58,7.03) v1(13.69,30.65) v1(13.63,9.48) v1(13.71,38.51) v1(13.75,23.77) v1(14.13,9.23) v1(14.26,25.96) v1(14.36,42.71) v1(14.48,9.83) v1(14.61,38.11) v1(14.61,37.11) v1(14.61,23.56) v1(14.71,40.46) v1(14.74,28.1) v1(14.75,15.78) v1(14.75,15.18) v1(14.75,14.58) v1(14.75,13.23) v1(14.75,12.58) v1(14.75,11.98) v1(15.08,18.28) v1(15.08,17.88) v1(15.11,42.76) v1(15.13,18.73) v1(15.13,9.23) v1(15.31,40.41) v1(15.48,19.03) v1(15.65,9.89) v1(15.88,19.08) v1(15.83,18.65) v1(15.91,42.81) v1(16.06,10.71) v1(16.08,9.28) v1(16.21,40.91) v1(16.26,39.81) v1(16.36,41.71) v1(16.53,28.22) v1(16.63,12.58) v1(16.76,31.66) v1(16.73,16.33) v1(16.81,42.76) v1(17.16,18.96) v1(17.18,16.33) v1(17.18,12.78) v1(17.18,12.23) v1(17.11,10.61) v1(17.23,13.48) v1(17.29,13.43) v1(17.31,20.46) v1(17.41,32.51) v1(17.46,22.45) v1(17.66,19.41) v1(17.63,16.33) v1(17.71,42.76) v1(17.71,31.66) v1(17.76,20.26) v1(17.91,25.02) v1(18.01,26.66) v1(18.06,22.45) v1(18.06,19.21) v1(18.13,16.33) v1(18.26,19.76) v1(18.31,10.71) v1(18.36,42.81) v1(18.46,20.16) v1(18.54,25.68) v1(18.54,25.28) v1(18.58,16.28) v1(18.58,15.13) v1(18.58,14.63) v1(18.61,46.96) v1(18.7,45.52) v1(18.68,24.83) v1(18.68,22.98) v1(18.64,19.18) v1(18.74,18.41) v1(18.73,17.73) v1(18.79,17.08) v1(18.88,25.53) v1(18.81,22.16) v1(18.93,22.58) v1(18.96,21.11) v1(18.96,20.46) v1(19.06,40.76) v1(19.09,24.78) v1(19.06,18.81) v1(19.12,46.15) v1(19.18,25.56) v1(19.16,19.51) v1(19.16,17.36) v1(19.11,16.76) v1(19.16,16.11) v1(19.13,14.18) v1(19.13,13.73) v1(19.27,43.96) v1(19.25,24.33) v1(19.23,23.44) v1(19.25,23) v1(19.23,17.68) v1(19.26,14.61) v1(19.26,11.71) v1(19.36,21.36) v1(19.39,20.08) v1(19.33,17.08) v1(19.31,11.06) v1(19.33,10.53) v1(19.38,9.88) v1(19.41,42.76) v1(19.41,40.81) v1(19.46,20.96) v1(19.46,18.86) v1(19.46,18.51) v1(19.56,41.51) v1(19.59,25.68) v1(19.66,32.21) v1(19.66,31.11) v1(19.66,20.56) v1(19.68,19.48) v1(19.68,15.23) v1(19.71,31.61) v1(19.73,22.78) v1(19.73,21.33) v1(19.84,44.52) v1(19.84,23.23) v1(19.89,17.63) v1(19.89,16.98) v1(19.91,41.26) v1(20.04,25.73) v1(20.08,9.83) v1(20.18,18.13) v1(20.29,7.88) v1(20.41,44.97) v1(20.31,15.31) v1(20.46,42.81) v1(20.43,25.73) v1(20.51,42.36) v1(20.56,41.11) v1(20.56,40.46) v1(20.57,6.53) v1(20.68,43.43) v1(20.66,41.76) v1(20.61,39.61) v1(20.73,41.88) v1(20.76,32.51) v1(20.71,31.76) v1(20.73,26.28) v1(20.84,25.73) v1(20.89,2.01) v1(20.89,1.66) v1(20.92,27.13) v1(20.99,5.5) v1(21.01,31.21) v1(21.02,8.53) v1(21.06,7.28) v1(21.08,6.18) v1(21.13,25.18) v1(21.13,19.43) v1(21.29,42.33) v1(21.29,27.48) v1(21.36,31.91) v1(21.43,27.18) v1(21.48,6.51) v1(21.61,43.72) v1(21.59,23.88) v1(21.58,18.93) v1(21.58,12.62) v1(21.7,42.88) v1(21.66,32.81) v1(21.71,26.84) v1(21.67,24.38) v1(21.66,9.63) v1(21.66,1.98) v1(21.64,1.64) v1(21.71,39.66) v1(21.71,31.31) v1(21.76,27.26) v1(21.98,42.28) v1(21.98,23.88) v1(21.93,23.38) v1(22.09,43.68) v1(22.01,31.96) v1(22.04,27.68) v1(22.09,27.33) v1(22.09,26.78) v1(22.06,18.31) v1(22.05,10.4) v1(22.08,9.03) v1(22.08,4.88) v1(22.18,42.98) v1(22.28,44.58) v1(22.21,32.71) v1(22.26,31.16) v1(22.21,15.91) v1(22.23,6.74) v1(22.33,45.13) v1(22.38,43.53) v1(22.36,39.66) v1(22.39,23.43) v1(22.38,9.43) v1(22.48,42.58) v1(22.43,42.13) v1(22.43,22.98) v1(22.46,12.51) v1(22.43,10.28) v1(22.5,5.85) v1(22.52,43.91) v1(22.63,45.53) v1(22.79,44.7) v1(22.77,9.92) v1(22.73,9.33) v1(22.74,8.7) v1(22.82,46.42) v1(22.84,23.08) v1(23,44.14) v1(22.96,39.66) v1(23.04,47.12) v1(23.11,44.99) v1(23.2,45.91) v1(23.3,7.3) v1(23.39,42.84) v1(23.36,38.76) v1(23.31,24.86) v1(23.59,44.75) v1(23.54,42.32) v1(23.66,44.34) v1(23.61,43.91) v1(23.76,39.66) v1(23.71,24.91) v1(23.81,36.86) v1(24.07,44.79) v1(24.04,15.48) v1(24.09,5.07) v1(24.14,42.32) v1(24.11,32.21) v1(24.11,31.61) v1(24.11,31.11) v1(24.29,17.56) v1(24.25,16.87) v1(24.39,15.8) v1(24.36,3.8) v1(24.42,43.48) v1(24.41,39.71) v1(24.41,33.41) v1(24.5,29.49) v1(24.5,1.72) v1(24.57,43.07) v1(24.54,16.43) v1(24.52,2.09) v1(24.61,27.31) v1(24.64,17.49) v1(24.78,44.45) v1(24.77,30.12) v1(24.75,28.27) v1(24.71,27.81) v1(24.8,27.04) v1(24.81,36.81) v1(24.84,29.49) v1(24.86,19.56) v1(24.89,17.07) v1(24.96,34.51) v1(24.91,28.91) v1(25.04,27.9) v1(25.01,17.63) v1(25.07,15.44) v1(25.18,38.76) v1(25.11,32.96) v1(25.11,31.66) v1(25.16,30.76) v1(25.16,27.56) v1(25.16,27.11) v1(25.11,20.86) v1(25.11,20.21) v1(25.15,16.7) v1(25.15,16.39) v1(25.17,6.75) v1(25.11,6.25) v1(25.2,2.11) v1(25.23,47.08) v1(25.22,17.06) v1(25.25,16.05) v1(25.22,15.74) v1(25.29,15.15) v1(25.28,14.22) v1(25.25,1.73) v1(25.31,39.76) v1(25.31,29.61) v1(25.36,21.36) v1(25.46,36.81) v1(25.5,28.88) v1(25.5,27.83) v1(25.41,20.51) v1(25.51,28.41) v1(25.54,27.37) v1(25.51,20.01) v1(25.54,17.06) v1(25.55,15.16) v1(25.66,17.67) v1(25.68,8) v1(25.68,7.7) v1(25.69,7.41) v1(25.69,7.12) v1(25.68,6.81) v1(25.78,6.5) v1(25.86,29.41) v1(25.86,27.66) v1(25.86,19.41) v1(25.85,17.06) v1(25.81,5.07) v1(25.91,33.01) v1(25.91,32.21) v1(25.91,31.06) v1(25.98,6.21) v1(26.11,45.98) v1(26.06,36.56) v1(26.06,35.36) v1(26.06,31.66) v1(26.06,28.71) v1(26.01,24.21) v1(26.01,22.36) v1(26.06,20.46) v1(26.09,9.32) v1(26.18,50.98) v1(26.14,49.98) v1(26.18,49.61) v1(26.14,46.83) v1(26.12,46.4) v1(26.16,43.31) v1(26.14,42.33) v1(26.11,39.66) v1(26.16,39.06) v1(26.11,38.16) v1(26.16,37.41) v1(26.16,35.91) v1(26.16,33.86) v1(26.16,30.21) v1(26.16,26.21) v1(26.11,25.46) v1(26.11,21.46) v1(26.16,19.96) v1(26.18,17.05) v1(26.25,42.95) v1(26.21,34.56) v1(26.21,27.11) v1(26.22,5.99) v1(26.45,42.62) v1(26.5,42.14) v1(26.5,17.05) v1(26.57,43.12) v1(26.52,41.91) v1(26.59,7.34) v1(26.57,5.82) v1(26.8,20.37) v1(26.71,19.81) v1(26.88,38.28) v1(26.83,17.05) v1(26.83,9.07) v1(26.87,6.94) v1(26.82,6.63) v1(26.98,55.23) v1(26.98,54.83) v1(27,44.87) v1(26.91,42.49) v1(26.94,33.65) v1(27,31.12) v1(27,30.62) v1(26.98,29.06) v1(27,28.06) v1(26.99,27.12) v1(26.98,26.33) v1(26.92,24.73) v1(26.94,22.92) v1(26.91,22.31) v1(26.96,21.26) v1(26.98,5.77) v1(27.04,54.03) v1(27.04,32.86) v1(27.04,31.86) v1(27.01,30.11) v1(27.03,25.51) v1(27.02,23.55) v1(27.01,21.81) v1(27.01,17.68) v1(27.2,19.36) v1(27.16,17.04) v1(27.23,52.78) v1(27.23,52.38) v1(27.23,52.03) v1(27.23,51.73) v1(27.23,51.43) v1(27.3,45.54) v1(27.23,43.48) v1(27.27,14.38) v1(27.3,7.32) v1(27.25,7.02) v1(27.25,6.56) v1(27.35,49.67) v1(27.32,42.31) v1(27.34,33.74) v1(27.39,5.77) v1(27.48,17.04) v1(27.48,16.7) v1(27.48,16.39) v1(27.48,16.11) v1(27.5,15.49) v1(27.59,45.93) v1(27.55,44.69) v1(27.52,42.64) v1(27.56,27.06) v1(27.59,24.99) v1(27.59,20.45) v1(27.52,15.14) v1(27.64,46.43) v1(27.7,43.03) v1(27.61,24.16) v1(27.66,19.31) v1(27.7,5.73) v1(27.79,49.63) v1(27.79,49.23) v1(27.79,48.83) v1(27.79,48.43) v1(27.73,46.88) v1(27.75,45.55) v1(27.73,42.36) v1(27.79,29.22) v1(27.75,25.45) v1(27.89,55.48) v1(27.88,47.33) v1(27.9,29.64) v1(27.85,28.63) v1(27.85,27.76) v1(27.89,17.04) v1(27.93,44.12) v1(27.91,31.26) v1(27.96,30.51) v1(27.91,17.72) v1(27.98,14.69) v1(28.09,46.21) v1(28.01,5.76) v1(28.18,44.55) v1(28.18,42.93) v1(28.16,42.47) v1(28.2,33.74) v1(28.2,25.59) v1(28.11,16.8) v1(28.12,6.52) v1(28.26,35.36) v1(28.23,19.21) v1(28.32,45.51) v1(28.36,15.86) v1(28.36,15.45) v1(28.35,9.02) v1(28.33,5.73) v1(28.46,36.16) v1(28.45,7.12) v1(28.55,28.04) v1(28.6,25.27) v1(28.58,6.5) v1(28.6,5.52) v1(28.66,47.48) v1(28.66,34.66) v1(28.66,33.74) v1(28.65,9.02) v1(28.77,46.29) v1(28.75,7.12) v1(28.93,52.13) v1(28.93,51.73) v1(28.93,51.43) v1(28.98,45.62) v1(28.98,33.28) v1(28.94,19.3) v1(29,9.02) v1(28.95,5.52) v1(29.04,53.98) v1(29.34,47.26) v1(29.35,41.29) v1(29.46,45.93) v1(29.41,33.76) v1(29.66,42.36) v1(29.7,5.52) v1(29.78,19.31) v1(29.83,40.78) v1(30.09,41.51) v1(30.1,5.52) v1(30.16,33.76) v1(30.21,29.21) v1(30.24,44.4) v1(30.35,42.16) v1(30.35,40.69) v1(30.46,46.26) v1(30.5,9.22) v1(30.45,5.52) v1(30.52,45.48) v1(30.63,46.87) v1(30.61,34.61) v1(30.61,29.61) v1(30.8,41.53) v1(30.76,40.51) v1(30.79,19.31) v1(30.75,5.52) v1(30.88,17.51) v1(30.85,9.22) v1(30.91,40.97) v1(31.05,5.52) v1(31.2,9.32) v1(31.32,46.09) v1(31.35,5.52) v1(31.42,41.4) v1(31.44,40.76) v1(31.56,45.03) v1(31.55,8.42) v1(31.55,7.32) v1(31.65,5.52) v1(31.78,44.6) v1(31.8,7.42) v1(31.84,41.85) v1(31.91,32.61) v1(31.96,8.45) v1(31.95,5.57) v1(32.1,7.47) v1(32.21,19.26) v1(32.31,23.83) v1(32.26,15.91) v1(32.35,8.45) v1(32.39,7.98) v1(32.5,13.53) v1(32.51,14.71) v1(32.8,7.47) v1(32.75,5.57) v1(32.92,15.71) v1(32.91,12.76) v1(33.05,33.73) v1(33.1,5.62) v1(33.16,16.16) v1(33.25,33.03) v1(33.26,19.31) v1(33.5,31.63) v1(33.45,5.67) v1(33.8,5.67) v1(33.81,34.18) v1(33.85,33.34) v1(33.97,32.96) v1(33.95,12.32) v1(34.02,19.26) v1(34.14,38.82) v1(34.11,33.75) v1(34.15,5.67) v1(34.25,26.77) v1(34.23,26.12) v1(34.34,40.19) v1(34.31,24.56) v1(34.48,39.71) v1(34.42,34.19) v1(34.46,31.45) v1(34.42,25.67) v1(34.5,5.67) v1(34.58,34.72) v1(34.61,32.71) v1(34.55,6.92) v1(34.69,33) v1(34.7,27.28) v1(34.7,9.37) v1(34.76,40.19) v1(34.78,19.27) v1(34.85,6.92) v1(34.85,5.67) v1(34.98,33.77) v1(34.92,11.35) v1(35,8.82) v1(35.12,34.33) v1(35.2,5.67) v1(35.26,39.9) v1(35.27,33.14) v1(35.29,32.49) v1(35.3,8.87) v1(35.25,7.47) v1(35.31,32) v1(35.34,31.56) v1(35.32,31.1) v1(35.31,10.81) v1(35.5,5.72) v1(35.6,8.87) v1(35.65,7.77) v1(35.9,8.87) v1(35.85,5.72) v1(36.06,34.34) v1(36.15,8.87) v1(36.15,5.87) v1(36.28,32.97) v1(36.27,10.9) v1(36.4,6.12) v1(36.45,8.87) v1(36.55,34.21) v1(36.54,26.86) v1(36.61,25.9) v1(36.57,24.28) v1(36.6,6.32) v1(36.7,25.88) v1(36.8,8.87) v1(36.85,6.47) v1(37.08,32.4) v1(37.15,34.9) v1(37.19,34.27) v1(37.15,8.87) v1(37.15,7.52) v1(37.2,6.47) v1(37.37,33.8) v1(37.45,33.36) v1(37.45,7.52) v1(37.53,10.9) v1(37.55,6.47) v1(37.66,22.91) v1(37.75,7.52) v1(37.85,8.22) v1(38.05,7.52) v1(38.37,25.09) v1(38.35,7.52) v1(38.5,25.64) v1(38.65,10.83) v1(38.7,7.52) v1(38.96,27.77) v1(38.92,27.42) v1(38.96,26.97) v1(38.96,24.92) v1(38.98,24.37) v1(39,7.87) v1(39,7.52) v1(39.05,8.12) v1(39.1,6.42) v1(39.11,26.59) v1(39.18,25.87) v1(39.3,8.27) v1(39.39,24.6) v1(39.4,6.42) v1(39.49,26.42) v1(39.6,24.13) v1(39.63,35.34) v1(39.65,26.93) v1(39.66,24.46) v1(39.65,8.32) v1(39.76,31.96) v1(39.78,6.58) v1(39.87,26.04) v1(39.85,25.62) v1(40,8.22) v1(40.04,35.86) v1(40.01,35.11) v1(40.03,34.48) v1(40.15,7.12) v1(40.35,37.06) v1(40.48,45.86) v1(40.41,10.67) v1(40.8,31.91) v1(41.23,7.87) v1(41.48,5.53) v1(41.55,24.5) v1(41.59,11.28) v1(41.59,7.15) v1(41.53,6.39) v1(41.62,10.02) v1(41.69,5.11) v1(41.91,24.66) v1(41.85,23.53) v1(41.97,25.08) v1(69.94,21.46) v2(4.91,17.4) v2(5.31,42.86) v2(5.36,38.96) v2(5.36,27.36) v2(5.36,24.86) v2(5.36,22.56) v2(5.31,19.66) v2(5.31,14.01) v2(5.41,41.96) v2(5.46,40.71) v2(5.46,40.01) v2(5.46,37.16) v2(5.41,36.11) v2(5.46,35.41) v2(5.46,34.81) v2(5.41,34.06) v2(5.41,33.01) v2(5.46,32.21) v2(5.46,31.51) v2(5.46,30.61) v2(5.41,28.26) v2(5.46,26.71) v2(5.41,25.76) v2(5.41,23.41) v2(5.41,20.96) v2(5.43,19.27) v2(5.46,13.01) v2(5.46,11.51) v2(5.51,41.41) v2(5.51,29.76) v2(5.51,24.06) v2(5.65,20.6) v2(5.98,17.68) v2(6.06,42.81) v2(6.28,18.43) v2(6.28,12.33) v2(6.36,34.01) v2(6.33,18.48) v2(6.33,16.08) v2(6.33,11.73) v2(6.46,35.16) v2(6.43,19.88) v2(6.66,36.71) v2(7.05,22.57) v2(7.11,39.66) v2(7.11,32.36) v2(7.41,36.81) v2(7.41,35.86) v2(7.41,33.51) v2(7.46,20.71) v2(7.43,13.63) v2(7.61,30.81) v2(7.69,26.26) v2(7.78,26.72) v2(7.83,20.28) v2(7.91,35.26) v2(7.91,32.86) v2(7.91,31.76) v2(7.95,22.66) v2(7.91,20.76) v2(8.06,30.96) v2(8.18,18.93) v2(8.31,38.36) v2(8.37,26.56) v2(8.56,42.71) v2(8.56,37.51) v2(8.53,19.78) v2(8.66,39.11) v2(8.73,27.01) v2(9.26,42.71) v2(9.31,38.76) v2(9.66,38.81) v2(9.61,32.26) v2(9.61,31.81) v2(10.36,42.61) v2(10.58,19) v2(10.71,37.41) v2(10.81,39.26) v2(10.88,20.63) v2(10.88,19.18) v2(11.12,8.84) v2(11.31,23.76) v2(11.46,23.16) v2(11.51,8.91) v2(11.51,42.81) v2(11.78,20.63) v2(11.73,8.84) v2(11.86,39.31) v2(11.88,18.88) v2(12.06,30.07) v2(12.08,10.43) v2(12.28,9.33) v2(12.31,38.91) v2(12.41,23.11) v2(12.58,19.28) v2(12.61,18.67) v2(12.78,10.43) v2(12.73,9.33) v2(12.98,6.96) v2(13.29,30.7) v2(13.26,26.31) v2(13.36,38.56) v2(13.38,18.88) v2(13.38,10.43) v2(13.56,40.81) v2(13.51,37.46) v2(13.63,9.48) v2(13.71,38.51) v2(14.23,9.53) v2(14.36,42.71) v2(14.48,9.83) v2(14.61,38.11) v2(14.61,37.11) v2(14.61,23.56) v2(14.71,40.46) v2(14.74,28.1) v2(14.75,15.78) v2(14.75,15.18) v2(14.75,12.58) v2(14.75,11.98) v2(14.9,20.82) v2(15.08,18.28) v2(15.11,42.76) v2(15.13,18.73) v2(15.13,17.83) v2(15.23,9.38) v2(15.31,40.41) v2(15.48,19.03) v2(15.65,9.89) v2(15.88,19.08) v2(15.83,18.65) v2(15.91,42.81) v2(16.06,23.59) v2(16.21,40.91) v2(16.26,39.81) v2(16.36,41.71) v2(16.62,25.12) v2(16.63,12.58) v2(16.76,31.66) v2(16.73,16.33) v2(16.81,42.76) v2(17.16,18.96) v2(17.18,16.33) v2(17.18,12.78) v2(17.18,12.23) v2(17.23,13.48) v2(17.33,25.26) v2(17.31,20.46) v2(17.41,32.51) v2(17.46,22.45) v2(17.66,19.41) v2(17.63,16.33) v2(17.71,42.76) v2(17.71,31.66) v2(17.76,20.26) v2(18.01,26.66) v2(18.06,22.45) v2(18.13,16.33) v2(18.26,19.76) v2(18.31,10.71) v2(18.36,42.81) v2(18.46,20.16) v2(18.54,25.68) v2(18.54,25.28) v2(18.58,16.28) v2(18.58,15.13) v2(18.58,14.63) v2(18.7,45.52) v2(18.68,24.83) v2(18.68,22.98) v2(18.64,19.18) v2(18.74,18.41) v2(18.73,17.73) v2(18.79,17.08) v2(18.88,25.53) v2(18.81,22.16) v2(18.86,18.11) v2(18.93,22.58) v2(18.96,21.11) v2(18.96,20.46) v2(19.06,40.76) v2(19.09,24.78) v2(19.06,18.81) v2(19.12,46.15) v2(19.18,25.56) v2(19.11,18.46) v2(19.21,18.11) v2(19.16,17.36) v2(19.11,16.76) v2(19.16,16.11) v2(19.13,14.18) v2(19.13,13.73) v2(19.27,43.96) v2(19.25,24.33) v2(19.23,23.44) v2(19.25,23) v2(19.23,17.68) v2(19.26,14.61) v2(19.26,11.71) v2(19.34,51.05) v2(19.36,21.36) v2(19.31,11.06) v2(19.33,10.53) v2(19.38,9.88) v2(19.41,42.76) v2(19.41,40.81) v2(19.46,20.96) v2(19.46,18.86) v2(19.46,18.51) v2(19.56,41.51) v2(19.59,25.68) v2(19.66,32.21) v2(19.66,31.11) v2(19.66,20.56) v2(19.68,15.23) v2(19.71,31.61) v2(19.73,22.78) v2(19.73,21.33) v2(19.84,44.52) v2(19.84,23.23) v2(19.89,17.63) v2(19.89,16.98) v2(19.91,41.26) v2(20.04,25.73) v2(20.06,11.76) v2(20.08,9.83) v2(20.41,44.97) v2(20.31,15.31) v2(20.46,49.91) v2(20.46,42.81) v2(20.43,25.73) v2(20.51,42.36) v2(20.68,43.43) v2(20.73,41.88) v2(20.76,32.51) v2(20.71,31.76) v2(20.84,25.73) v2(20.92,27.13) v2(21.01,31.21) v2(21.02,13.43) v2(21.08,6.18) v2(21.13,25.18) v2(21.11,4.86) v2(21.29,42.33) v2(21.28,27.83) v2(21.29,27.48) v2(21.36,31.91) v2(21.43,27.18) v2(21.61,43.72) v2(21.59,23.88) v2(21.7,42.88) v2(21.66,32.81) v2(21.71,26.84) v2(21.67,24.38) v2(21.71,31.31) v2(21.76,27.26) v2(21.89,25.44) v2(21.98,42.28) v2(21.98,23.88) v2(22.09,43.68) v2(22.01,31.96) v2(22.04,27.68) v2(22.09,27.33) v2(22.09,26.78) v2(22.05,10.4) v2(22.08,9.03) v2(22.08,4.88) v2(22.18,42.98) v2(22.2,9.92) v2(22.28,44.58) v2(22.21,32.71) v2(22.26,31.16) v2(22.21,15.91) v2(22.37,45.79) v2(22.33,45.13) v2(22.38,43.53) v2(22.38,9.43) v2(22.44,47.25) v2(22.48,42.58) v2(22.43,42.13) v2(22.46,12.51) v2(22.43,10.28) v2(22.63,45.53) v2(22.79,44.7) v2(22.73,26.19) v2(22.8,14.12) v2(22.77,9.92) v2(22.73,9.33) v2(22.74,8.7) v2(22.82,46.42) v2(23,44.14) v2(22.93,24.07) v2(23.04,47.12) v2(23.11,44.99) v2(23.01,42.36) v2(23.2,45.91) v2(23.39,46.51) v2(23.39,42.84) v2(23.31,24.86) v2(23.59,44.75) v2(23.54,42.32) v2(23.68,44.48) v2(23.66,44.34) v2(23.61,43.91) v2(23.78,43.18) v2(23.71,24.91) v2(23.88,45.18) v2(23.81,36.86) v2(23.95,42.78) v2(23.98,23.76) v2(24.07,44.79) v2(24.04,15.48) v2(24.09,5.07) v2(24.14,42.32) v2(24.11,32.21) v2(24.11,31.61) v2(24.11,31.11) v2(24.31,48.04) v2(24.36,3.8) v2(24.42,43.48) v2(24.41,33.41) v2(24.5,29.49) v2(24.57,43.07) v2(24.51,20.61) v2(24.54,16.43) v2(24.6,15.04) v2(24.65,42.63) v2(24.61,27.31) v2(24.78,44.45) v2(24.77,30.12) v2(24.75,28.27) v2(24.71,27.81) v2(24.8,27.04) v2(24.83,44.18) v2(24.81,36.81) v2(24.84,29.49) v2(24.89,17.07) v2(24.96,34.51) v2(24.91,28.91) v2(24.92,15.16) v2(24.99,3.76) v2(25.04,27.9) v2(25.07,23.78) v2(25.07,15.44) v2(25.09,4.74) v2(25.11,32.96) v2(25.11,31.66) v2(25.16,30.76) v2(25.16,27.56) v2(25.16,27.11) v2(25.11,20.86) v2(25.11,20.21) v2(25.15,16.7) v2(25.15,16.39) v2(25.23,47.08) v2(25.28,43.82) v2(25.22,17.06) v2(25.25,16.05) v2(25.22,15.74) v2(25.29,15.15) v2(25.28,14.22) v2(25.38,45.23) v2(25.31,29.61) v2(25.46,36.81) v2(25.5,28.88) v2(25.5,27.83) v2(25.41,20.51) v2(25.51,28.41) v2(25.54,27.37) v2(25.51,20.01) v2(25.54,17.06) v2(25.55,15.16) v2(25.7,46.65) v2(25.68,8) v2(25.68,7.7) v2(25.69,7.41) v2(25.69,7.12) v2(25.68,6.81) v2(25.78,6.5) v2(25.86,29.41) v2(25.86,27.66) v2(25.85,17.06) v2(25.81,5.07) v2(25.86,3.48) v2(25.91,33.01) v2(25.91,32.21) v2(25.91,31.06) v2(25.98,6.21) v2(26.11,45.98) v2(26.06,36.56) v2(26.06,20.46) v2(26.18,50.98) v2(26.14,49.98) v2(26.18,49.61) v2(26.14,46.83) v2(26.12,46.4) v2(26.16,43.31) v2(26.14,42.33) v2(26.16,37.41) v2(26.16,35.91) v2(26.16,19.96) v2(26.18,17.05) v2(26.25,42.95) v2(26.22,5.99) v2(26.38,45.12) v2(26.44,46.02) v2(26.45,42.62) v2(26.5,42.14) v2(26.5,17.05) v2(26.57,43.12) v2(26.57,5.82) v2(26.71,19.81) v2(26.83,17.05) v2(26.87,6.94) v2(26.82,6.63) v2(26.85,3.62) v2(26.98,55.23) v2(26.98,54.83) v2(27,44.87) v2(26.91,42.49) v2(26.98,5.77) v2(27.04,54.03) v2(27.16,47.26) v2(27.16,17.04) v2(27.14,5.08) v2(27.23,52.78) v2(27.23,52.38) v2(27.23,52.03) v2(27.23,51.73) v2(27.23,51.43) v2(27.3,45.54) v2(27.23,43.48) v2(27.27,14.38) v2(27.3,7.32) v2(27.25,7.02) v2(27.32,42.31) v2(27.4,8.49) v2(27.4,7.67) v2(27.39,5.77) v2(27.48,17.04) v2(27.48,16.7) v2(27.48,16.39) v2(27.48,16.11) v2(27.5,15.49) v2(27.59,45.93) v2(27.55,44.69) v2(27.52,42.64) v2(27.52,15.14) v2(27.55,6.92) v2(27.64,46.43) v2(27.7,43.03) v2(27.68,14.83) v2(27.7,6.62) v2(27.7,5.73) v2(27.79,49.63) v2(27.79,49.23) v2(27.79,48.83) v2(27.79,48.43) v2(27.73,46.88) v2(27.75,45.55) v2(27.73,42.36) v2(27.74,4.77) v2(27.89,55.48) v2(27.88,47.33) v2(27.84,22.46) v2(27.89,17.04) v2(27.93,44.12) v2(27.93,42.9) v2(27.91,31.26) v2(27.96,30.51) v2(27.98,14.69) v2(28.09,46.21) v2(28.04,42.56) v2(28.05,16.39) v2(28.01,5.76) v2(28.18,44.55) v2(28.18,42.93) v2(28.16,42.47) v2(28.11,16.8) v2(28.27,43.85) v2(28.25,43.45) v2(28.25,42.92) v2(28.29,42.34) v2(28.26,35.36) v2(28.23,22.01) v2(28.37,46.78) v2(28.32,45.51) v2(28.36,15.86) v2(28.36,15.45) v2(28.34,15.1) v2(28.35,9.02) v2(28.33,5.73) v2(28.46,36.16) v2(28.45,7.12) v2(28.58,6.5) v2(28.6,5.52) v2(28.66,47.48) v2(28.67,44.61) v2(28.66,34.66) v2(28.65,9.02) v2(28.77,46.29) v2(28.75,28.44) v2(28.75,7.12) v2(28.84,27.88) v2(28.93,52.13) v2(28.93,51.73) v2(28.93,51.43) v2(28.98,45.62) v2(29,9.02) v2(28.95,5.52) v2(29.04,53.98) v2(29.07,45.01) v2(29.14,21.39) v2(29.25,46.51) v2(29.34,47.26) v2(29.46,45.93) v2(29.41,33.76) v2(29.68,43.28) v2(29.63,29.54) v2(29.7,5.52) v2(29.83,40.78) v2(29.98,44.23) v2(30.1,5.52) v2(30.16,33.76) v2(30.12,30.08) v2(30.5,9.22) v2(30.45,5.52) v2(30.61,21.32) v2(30.61,34.61) v2(30.75,5.52) v2(30.85,9.22) v2(31.05,5.52) v2(31.2,9.32) v2(31.22,46.83) v2(31.35,5.52) v2(31.46,29.05) v2(31.54,29.79) v2(31.54,21.3) v2(31.55,8.42) v2(31.55,7.32) v2(31.65,15.62) v2(31.65,5.52) v2(31.8,14.52) v2(31.8,7.42) v2(31.87,28.6) v2(31.86,17.47) v2(31.96,8.45) v2(31.95,5.57) v2(32.1,7.47) v2(32.14,30.39) v2(32.14,29.36) v2(32.3,28.29) v2(32.25,16.99) v2(32.35,8.45) v2(32.39,7.98) v2(32.44,29.94) v2(32.59,28.86) v2(32.55,27.41) v2(32.66,21.5) v2(32.8,7.47) v2(32.75,5.57) v2(33.09,38.42) v2(33.1,5.62) v2(33.14,4.84) v2(33.26,17.26) v2(33.34,14.11) v2(33.45,5.67) v2(33.53,28.57) v2(33.69,38.56) v2(33.62,29.5) v2(33.66,27.31) v2(33.73,30.03) v2(33.72,29.11) v2(33.8,21.54) v2(33.8,5.67) v2(33.85,33.34) v2(33.97,39.34) v2(34.15,5.67) v2(34.37,40.87) v2(34.5,5.67) v2(34.55,28.69) v2(34.55,6.92) v2(34.7,9.37) v2(34.85,6.92) v2(34.85,5.67) v2(34.98,39.5) v2(35,8.82) v2(35.2,5.67) v2(35.3,8.87) v2(35.25,7.47) v2(35.5,5.72) v2(35.6,8.87) v2(35.65,7.77) v2(35.9,8.87) v2(35.85,5.72) v2(36.04,39.36) v2(36.15,8.87) v2(36.15,5.87) v2(36.3,40.99) v2(36.28,32.97) v2(36.4,6.12) v2(36.5,21.45) v2(36.45,8.87) v2(36.54,26.86) v2(36.61,25.9) v2(36.57,24.28) v2(36.6,6.32) v2(36.7,25.88) v2(36.8,8.87) v2(36.85,6.47) v2(37.2,39.32) v2(37.15,8.87) v2(37.15,7.52) v2(37.2,6.47) v2(37.48,21.46) v2(37.45,7.52) v2(37.55,6.47) v2(37.66,22.91) v2(37.75,38.92) v2(37.75,7.52) v2(37.85,8.22) v2(38.05,7.52) v2(38.2,11.87) v2(38.37,25.09) v2(38.35,7.52) v2(38.58,40.9) v2(38.55,13.67) v2(38.7,7.52) v2(38.77,9.49) v2(38.96,27.77) v2(38.92,27.42) v2(38.96,26.97) v2(38.96,24.92) v2(38.98,24.37) v2(38.94,13.05) v2(39,7.87) v2(39,7.52) v2(39.05,8.12) v2(39.1,6.42) v2(39.11,26.59) v2(39.18,25.87) v2(39.3,21.41) v2(39.3,8.27) v2(39.38,41) v2(39.39,24.6) v2(39.4,6.42) v2(39.47,37.7) v2(39.49,26.42) v2(39.6,24.13) v2(39.65,26.93) v2(39.64,25.28) v2(39.66,24.46) v2(39.65,8.32) v2(39.75,20.61) v2(39.77,11.96) v2(39.78,6.58) v2(39.87,26.04) v2(39.85,25.62) v2(40,8.22) v2(40.05,5.66) v2(40.15,7.12) v2(40.26,12.99) v2(40.86,37.77) v2(40.92,40.77) v2(41.11,8.9) v2(41.36,38.6) v2(41.39,33.19) v2(41.68,33.77) v2(41.69,5.11) v2(41.85,23.53) v2(68.29,23.98) v2(68.6,23.97) v3(5.23,41.08) v3(5.58,42.48) v3(5.88,33.68) v3(5.88,31.73) v3(5.88,30.43) v3(5.83,24.73) v3(5.93,41.58) v3(5.93,36.73) v3(5.93,35.78) v3(5.93,34.73) v3(5.93,32.58) v3(5.98,29.28) v3(5.93,12.63) v3(6.01,44.06) v3(6.11,39.51) v3(6.06,11.41) v3(6.18,22.03) v3(6.13,18.08) v3(6.38,21.48) v3(6.56,41.96) v3(6.68,8.28) v3(6.76,26.56) v3(6.88,20.13) v3(7.31,7.36) v3(7.46,44.26) v3(7.68,43.38) v3(7.63,8.53) v3(8.16,27.21) v3(8.16,25.91) v3(8.58,30.88) v3(8.56,28.16) v3(8.53,19.28) v3(8.78,43.63) v3(9.08,25.78) v3(9.23,42.13) v3(9.31,33.91) v3(9.31,33.16) v3(9.21,24.11) v3(9.31,5.16) v3(9.36,34.96) v3(9.36,28.06) v3(9.41,26.56) v3(9.53,30.48) v3(9.73,42.68) v3(9.76,24.76) v3(10.4,5.97) v3(10.51,23.06) v3(10.96,43.81) v3(11.01,34.76) v3(10.96,24.71) v3(11.21,33.61) v3(11.21,28.31) v3(11.56,43.91) v3(11.61,21.61) v3(11.81,27.51) v3(11.86,23.61) v3(12.31,30.48) v3(13.03,32.28) v3(13.16,21.41) v3(13.26,23.46) v3(13.36,45.61) v3(13.48,33.68) v3(13.53,35.08) v3(13.66,40.06) v3(14.16,39.66) v3(14.23,37.83) v3(14.58,36.43) v3(14.73,31.28) v3(14.78,26.53) v3(14.88,32.23) v3(14.81,21.61) v3(14.96,34.41) v3(15.01,33.06) v3(15.08,36.93) v3(15.26,38.16) v3(15.21,35.11) v3(15.51,28.51) v3(15.48,27.73) v3(15.6,23.12) v3(15.91,44.06) v3(15.88,37.78) v3(15.96,21.66) v3(16.18,26.68) v3(16.48,38.33) v3(16.46,35.16) v3(16.52,36.66) v3(16.76,44.21) v3(16.78,40.43) v3(16.86,10.06) v3(16.96,33.36) v3(17,28.91) v3(17,27.91) v3(16.96,21.36) v3(17.26,40.11) v3(17.21,36.61) v3(17.21,34.61) v3(17.33,39.28) v3(17.86,45.46) v3(17.88,39.78) v3(18.21,46.11) v3(19.01,31.01) v3(19.06,34.11) v3(19.11,34.91) v3(19.19,32.29) v3(19.15,27.64) v3(19.26,44.91) v3(19.56,30.46) v3(19.71,45.41) v3(20.01,36.61) v3(20.86,30.51) v3(20.96,44.06) v3(21.01,28.91) v3(21.21,36.61) v3(21.46,34.86) v3(21.91,35.21) v3(22.21,33.46) v3(22.36,28.21) v3(22.43,40.38) v3(22.86,27.06) v3(23.33,40.38) v3(24.03,33.63) v3(24.11,32.91) v3(24.36,30.46) v3(24.46,26.71) v3(24.68,40.38) v3(24.63,31.03) v3(24.88,33.43) v3(24.86,32.41) v3(25.76,44.41) v3(25.73,37.68) v3(25.73,26.93) v3(25.83,28.08) v3(26.48,40.33) v3(26.68,37.73) v3(27.08,34.38) v3(27.36,44.21) v3(27.38,33.23) v3(27.46,36.46) v3(27.98,34.33) v3(28.03,35.93) v3(28.23,32.23) v3(28.23,30.83) v3(28.28,30.13) v3(28.71,36.71) v3(28.68,32.43) v3(28.66,31.06) v3(28.91,30.21) v3(34.73,29.83) v3(34.73,29.18) v3(35.33,25.83) v3(35.88,25.13) v3(36.08,29.98) v3(63.76,25.79) v3(91.14,37.91) v4(12.18,25.22) v4(19.21,13.3) v4(19.41,12.04) v4(20.26,13.18) v4(20.34,11.99) v4(20.38,10.92) v4(20.43,14.23) v4(23.87,9.34) v4(23.9,8.4) v4(23.95,7.27) v4(24.47,8.52) v4(25.35,9.07) v4(25.59,8.83) v4(26.09,9.82) v4(26.58,10.81) v4(27.08,9.82) v4(27.08,9.32) v4(28.96,25.06) v4(29.87,12.08) v4(30.01,10.28) v4(30.67,10.43) v4(31.24,12.96) v4(31.27,12.34) v4(31.31,11.08) v4(31.87,10.3) v4(31.85,7.67) v4(32.07,9.92) v4(32.1,9.34) v4(32.69,9.7) v4(32.85,9.19) v4(33.25,9.22) v4(33.58,16.4) v4(33.75,9.5) v4(33.91,24.79) v4(69.14,23.53) v4(69.14,23.03) v5(2.73,11.74) v5(2.86,12.05) v5(3.16,12.27) v5(3.16,11.69) v5(3.39,12.05) v5(3.52,11.74) v5(4.1,11.57) v5(4.32,12.5) v5(4.63,12.28) v5(4.87,12.53) v5(4.9,12.08) v5(5.2,14.24) v5(5.26,11.15) v5(5.4,15.35) v5(5.57,19.9) v5(5.62,19.57) v5(5.65,14.22) v5(5.75,15.34) v5(5.79,8.26) v5(6.16,15.33) v5(6.12,14.17) v5(6.26,9.26) v5(6.5,15.31) v5(6.5,14.19) v5(6.41,7.26) v5(6.63,10.68) v5(6.86,7.21) v5(7.21,9.36) v5(7.43,10.28) v5(7.68,10.88) v5(7.83,9.18) v5(7.81,7.41) v5(7.88,6.63) v5(7.88,6.03) v5(7.93,9.93) v5(8.13,9.18) v5(8.16,7.41) v5(8.37,13.95) v5(8.34,13.51) v5(8.48,9.13) v5(8.58,7.38) v5(8.63,5.08) v5(8.86,8.81) v5(8.88,6.38) v5(8.96,7.41) v5(9.31,8.91) v5(9.31,7.41) v5(9.43,9.63) v5(9.66,8.91) v5(9.66,7.41) v5(9.78,10.33) v5(9.78,6.28) v5(9.83,5.63) v5(9.96,8.91) v5(10.06,7.41) v5(10.23,9.73) v5(10.26,8.91) v5(10.41,7.41) v5(10.58,10.93) v5(10.58,6.68) v5(10.66,8.81) v5(10.81,7.41) v5(11.06,8.96) v5(11.13,10.03) v5(11.41,8.96) v5(11.53,9.58) v5(11.68,13.83) v5(11.68,8.98) v5(11.71,15.6) v5(11.78,10.63) v5(11.73,7.43) v5(12.01,8.96) v5(12.03,7.23) v5(12.2,41.63) v5(12.38,9.83) v5(12.33,7.03) v5(12.46,8.86) v5(12.68,10.58) v5(12.73,10.88) v5(12.73,6.93) v5(12.88,8.93) v5(12.93,10.33) v5(13.03,9.98) v5(13.18,9.63) v5(13.13,6.93) v5(13.31,9.26) v5(13.35,8.81) v5(13.38,6.48) v5(13.63,6.93) v5(13.8,15.66) v5(13.8,13.98) v5(14.03,6.88) v5(14.53,10.93) v5(14.58,10.63) v5(14.88,10.38) v5(15.01,9.11) v5(15.01,8.61) v5(15.13,10.58) v5(15.28,7.08) v5(15.38,8.08) v5(15.38,7.73) v5(15.33,7.43) v5(15.58,10.48) v5(15.63,9.83) v5(15.68,8.93) v5(15.68,8.53) v5(15.83,15.76) v5(15.88,13.8) v5(15.89,12.16) v5(15.83,7.08) v5(16.13,8.43) v5(16.48,10.73) v5(16.44,10.03) v5(16.44,9.11) v5(16.58,9.53) v5(16.88,9.13) v5(17.18,10.63) v5(17.18,9.48) v5(17.59,9.23) v5(17.79,10.13) v5(17.98,13.91) v5(17.97,12.07) v5(18.08,9.58) v5(18.22,15.75) v5(18.33,9.13) v5(18.55,18.2) v5(18.68,9.43) v5(18.73,10.28) v5(18.95,21.62) v5(18.98,10.68) v5(19.18,9.38) v5(19.46,10.66) v5(19.51,10.21) v5(19.61,9.86) v5(19.76,9.51) v5(19.86,41.29) v5(19.96,9.11) v5(20.15,15.63) v5(20.11,13.89) v5(20.16,8.71) v5(20.25,41.74) v5(20.26,8.31) v5(20.48,6.63) v5(20.53,18.31) v5(20.54,8.03) v5(20.68,7.68) v5(20.85,22.56) v5(20.88,7.28) v5(20.88,6.83) v5(20.88,5.88) v5(20.93,6.38) v5(21.01,10.71) v5(21.08,7.58) v5(21.11,10.36) v5(21.18,5.53) v5(21.21,7.96) v5(21.29,7.03) v5(21.29,6.53) v5(21.28,4.23) v5(21.28,2.68) v5(21.32,12.49) v5(21.37,11.86) v5(21.38,11.49) v5(21.31,9.96) v5(21.34,5.83) v5(21.39,5.13) v5(21.64,9.73) v5(21.63,5.28) v5(21.79,4.53) v5(21.78,4.18) v5(21.89,3.68) v5(21.88,2.98) v5(21.91,10.61) v5(22.01,8.01) v5(22.04,42.71) v5(22.4,11.87) v5(22.48,42.63) v5(22.44,17.87) v5(22.44,12.47) v5(22.47,11.42) v5(22.76,9.71) v5(22.71,7.86) v5(22.87,22.27) v5(23.06,7.76) v5(23.16,10.56) v5(23.16,9.66) v5(23.14,4.28) v5(23.38,25.12) v5(23.45,27.82) v5(23.45,11.78) v5(23.46,9.51) v5(23.41,7.56) v5(23.52,20.07) v5(23.78,12.68) v5(23.73,10.08) v5(23.83,10.88) v5(23.89,9.48) v5(23.93,3.43) v5(24.07,11.75) v5(24.18,9.98) v5(24.28,12.83) v5(24.29,3.78) v5(24.36,9.21) v5(24.31,7.56) v5(24.57,21.08) v5(24.53,9.78) v5(24.61,10.31) v5(24.66,7.51) v5(24.71,9.21) v5(25,22.56) v5(25.06,9.21) v5(25.06,7.51) v5(25.09,3.68) v5(25.23,6.93) v5(25.34,4.33) v5(25.45,13.78) v5(25.41,13.13) v5(25.46,7.51) v5(25.58,10.23) v5(25.61,9.01) v5(25.64,3.83) v5(25.73,9.68) v5(25.86,7.56) v5(25.88,6.73) v5(26.11,10.36) v5(26.16,9.11) v5(26.26,7.56) v5(26.48,3.53) v5(26.58,10.93) v5(26.51,9.11) v5(26.54,4.28) v5(26.61,7.56) v5(26.79,11.91) v5(26.73,10.43) v5(26.73,9.73) v5(26.86,9.11) v5(27.01,7.56) v5(27.13,10.98) v5(27.33,3.58) v5(27.44,11.87) v5(27.41,8.91) v5(27.41,7.51) v5(27.59,4.38) v5(27.72,14.21) v5(27.79,9.18) v5(27.86,7.51) v5(28.04,4.38) v5(28.28,12.28) v5(28.21,10.56) v5(28.23,9.28) v5(28.26,7.51) v5(28.52,14.21) v5(28.54,4.38) v5(28.58,3.73) v5(28.71,9.36) v5(28.79,7.18) v5(28.89,4.68) v5(28.91,11.56) v5(29.18,12.53) v5(29.26,9.36) v5(29.38,11.98) v5(29.76,9.36) v5(29.84,7.18) v5(30.01,36.91) v5(30.08,11.23) v5(30.29,8.36) v5(30.71,35.21) v5(31.31,24.11) v5(31.23,7.28) v5(31.34,31.01) v5(31.71,22.92) v5(31.81,28.11) v5(31.83,7.28) v5(32.27,26.81) v5(32.3,26.41) v5(32.5,24.8) v5(32.55,25.11) v5(32.59,16.73) v5(32.58,16.41) v5(33.08,32.65) v5(33.09,32.31) v5(33.27,24.66) v5(33.39,31.42) v5(34.19,43.39) v5(34.3,30.82) v5(34.35,33.82) v5(34.4,28.42) v5(34.4,21.32) v5(34.5,32.72) v5(34.5,31.57) v5(34.45,29.42) v5(34.5,26.97) v5(34.5,25.92) v5(34.5,22.32) v5(34.45,20.22) v5(34.45,17.47) v5(34.55,30.22) v5(34.58,19.61) v5(34.58,7.23) v5(34.66,41.91) v5(34.65,24.62) v5(35,17.52) v5(35.4,21.77) v5(35.52,44.58) v5(35.62,33.33) v5(35.62,28.51) v5(35.76,24.81) v5(35.81,42.86) v5(36.1,17.52) v5(36.29,19.82) v5(36.4,21.69) v5(36.46,43.72) v5(36.57,23.43) v5(36.67,32.09) v5(36.77,26.95) v5(36.8,17.57) v5(36.86,8.96) v5(36.95,28) v5(36.96,8.51) v5(36.96,6.61) v5(37.11,18.51) v5(37.26,25.51) v5(37.26,8.21) v5(37.36,9.91) v5(37.43,48.29) v5(37.58,23.85) v5(37.66,8.26) v5(37.66,6.66) v5(37.76,9.51) v5(37.81,11.76) v5(38,27.46) v5(37.92,22.5) v5(37.98,19.84) v5(37.91,12.31) v5(38.01,8.86) v5(38.06,8.41) v5(38.26,6.71) v5(38.5,27.46) v5(38.5,26.46) v5(38.5,24.96) v5(38.46,12.51) v5(38.56,7.06) v5(39,28.46) v5(39,27.46) v5(39,26.46) v5(39,25.46) v5(38.96,10.91) v5(38.91,10.36) v5(39.11,17.18) v5(39.01,12.51) v5(39.11,7.81) v5(39.21,9.11) v5(39.21,8.66) v5(39.21,8.26) v5(39.26,7.11) v5(39.5,30.96) v5(39.5,29.96) v5(39.5,29.46) v5(39.5,26.96) v5(39.5,25.96) v5(39.5,24.96) v5(39.53,15.59) v5(39.74,17.18) v5(39.71,8.66) v5(39.86,7.11) v5(40,28.96) v5(40,28.46) v5(40,26.96) v5(40,25.96) v5(39.94,24.92) v5(39.91,11.26) v5(40.06,12.41) v5(40.16,9.46) v5(40.26,10.56) v5(40.21,10.06) v5(40.26,7.76) v5(40.36,17.18) v5(40.5,26.46) v5(40.41,12.31) v5(40.46,8.06) v5(40.57,40.91) v5(40.76,12.26) v5(40.71,8.36) v5(40.86,8.76) v5(40.97,17.18) v5(40.91,9.21) v5(41.01,11.11) v5(41.01,10.66) v5(41.01,10.21) v5(41.01,9.71) v5(41.21,13.31) v5(41.32,15) v5(41.45,15.57) v5(41.65,17.16) v5(41.91,13.96) v5(46.91,18.54) v5(47.15,18.93) v5(47.15,14.97) v5(47.95,14.97) v5(49.25,32.52) v5(49.95,21.26) v5(50.19,21.51) v5(50.19,21.02) v5(50.44,26.21) v5(50.44,21.76) v5(50.69,22.01) v5(51.18,21.51) v5(51.18,21.02) v5(51.4,15.02) v5(51.43,21.76) v5(51.68,22.01) v5(51.93,22.25) v5(52.42,23.24) v5(54.2,20.07) v5(54.45,20.52) v5(55.3,19.57) v5(56.13,29.93) v5(56.88,29.18) v5(56.88,28.69) v5(56.88,28.19) v5(57.37,28.69) v5(57.37,28.19) v5(57.37,27.7) v5(57.6,25.97) v5(57.62,25.47) v5(57.62,23.99) v5(57.87,30.17) v5(57.87,26.21) v5(58.11,30.42) v5(58.11,28.94) v5(58.11,26.46) v5(58.11,25.47) v5(58.36,26.21) v5(58.36,25.22) v5(58.61,24.98) v5(59.1,30.92) v5(59.1,30.42) v5(59.1,29.43) v5(59.1,24.98) v5(59.1,23.99) v5(59.11,31.41) v5(59.19,21.1) v5(59.47,31.63) v5(59.47,21.09) v5(59.59,30.8) v5(59.57,30.34) v5(59.57,29.93) v5(59.57,29.55) v5(59.87,32.84) v5(60.12,30.24) v5(60.39,28.98) v5(63.3,25.68) v5(63.66,25.78) v6(2.73,11.74) v6(3.16,12.27) v6(3.52,11.74) v6(4.1,11.57) v6(4.32,12.5) v6(4.63,12.28) v6(4.87,12.53) v6(4.9,12.08) v6(5.26,11.15) v6(5.79,8.26) v6(6.26,9.26) v6(6.41,7.26) v6(6.63,10.68) v6(6.86,7.21) v6(7.21,9.36) v6(7.43,10.28) v6(7.68,10.88) v6(7.83,9.18) v6(7.81,7.41) v6(7.88,6.63) v6(7.88,6.03) v6(7.93,9.93) v6(8.16,7.41) v6(8.58,7.38) v6(8.63,5.08) v6(8.88,6.38) v6(8.96,7.41) v6(9.31,8.91) v6(9.31,7.41) v6(9.43,9.63) v6(9.66,8.91) v6(9.66,7.41) v6(9.78,10.33) v6(9.78,6.28) v6(9.83,5.63) v6(9.96,8.91) v6(10.06,7.41) v6(10.23,9.73) v6(10.26,8.91) v6(10.41,7.41) v6(10.58,10.93) v6(10.58,6.68) v6(10.81,7.41) v6(11.06,8.96) v6(11.13,10.03) v6(11.41,8.96) v6(11.53,9.58) v6(11.68,8.98) v6(11.78,10.63) v6(11.73,7.43) v6(12.01,8.96) v6(12.03,7.23) v6(12.38,9.83) v6(12.33,7.03) v6(12.46,8.86) v6(12.68,10.58) v6(12.73,10.88) v6(12.73,6.93) v6(12.88,8.93) v6(12.93,10.33) v6(13.03,9.98) v6(13.18,9.63) v6(13.13,6.93) v6(13.31,9.26) v6(13.35,8.81) v6(13.38,6.48) v6(13.63,6.93) v6(14.03,6.88) v6(14.53,10.93) v6(14.58,10.63) v6(14.88,10.38) v6(15.01,9.11) v6(15.01,8.61) v6(15.13,10.58) v6(15.28,7.08) v6(15.38,8.08) v6(15.38,7.73) v6(15.33,7.43) v6(15.63,9.83) v6(15.68,8.93) v6(15.68,8.53) v6(15.83,7.08) v6(16.44,9.11) v6(17.18,10.63) v6(18.08,9.58) v6(18.33,9.13) v6(18.98,10.68) v6(19.18,9.38) v6(20.03,42.42) v6(20.48,6.63) v6(20.68,7.68) v6(20.88,7.28) v6(20.88,6.83) v6(20.88,5.88) v6(20.93,6.38) v6(21.08,7.58) v6(21.18,5.53) v6(21.28,4.23) v6(21.28,2.68) v6(21.63,5.28) v6(21.73,41.97) v6(21.78,4.18) v6(21.88,2.98) v6(22.01,8.01) v6(22.54,44.43) v6(22.94,41.16) v6(23.39,45.79) v6(23.64,45.53) v6(23.78,12.68) v6(23.73,10.08) v6(23.9,41.56) v6(23.83,10.88) v6(23.93,3.43) v6(24.11,43.44) v6(24.18,9.98) v6(24.28,12.83) v6(24.53,9.78) v6(24.83,44.38) v6(25.23,6.93) v6(25.58,10.23) v6(25.61,9.01) v6(25.73,9.68) v6(25.88,6.73) v6(26.01,45.53) v6(26.06,41.01) v6(26.48,3.53) v6(26.53,42.02) v6(26.58,10.93) v6(26.73,10.43) v6(26.73,9.73) v6(27,46.45) v6(27.13,10.98) v6(27.33,3.58) v6(27.93,47.63) v6(28.28,12.28) v6(28.58,3.73) v6(29.18,12.53) v6(29.38,11.98) v6(30.01,36.91) v6(30.01,47.26) v6(30.08,11.23) v6(31.23,7.28) v6(31.83,7.28) v6(32.35,47.34) v6(34.58,47.28) v6(34.58,7.23) v6(36.97,19.91) v6(37.11,20.8) v6(37.36,21.61) v6(37.53,31.65) v6(37.8,30.7) v6(37.8,20.89) v6(37.86,29.75) v6(37.85,29.05) v6(38,23.21) v6(38.19,21.7) v6(38.41,32.51) v6(38.5,27.46) v6(38.58,20.35) v6(38.61,19.63) v6(39,27.46) v6(39.05,31.56) v6(39.27,33.58) v6(39.5,30.96) v6(39.5,25.96) v6(39.5,24.96) v6(39.5,19.82) v6(39.52,24.37) v6(39.53,18.73) v6(39.53,15.59) v6(39.62,20.97) v6(40,25.96) v6(39.94,24.92) v6(40.02,32.84) v6(40.08,19.27) v6(40.41,20.97) v6(40.48,19.78) v6(40.58,31.86) v6(40.8,33.38) v6(40.77,31.02) v6(41.14,32.71) v6(41.17,31.86) v6(41.2,30.64) v6(41.28,25.85) v6(41.27,25.07) v6(41.26,20.1) v6(41.45,21.97) v6(41.45,15.57) v6(41.59,28.05) v6(41.53,24.4) v6(41.64,24.74) v6(41.89,31.81) v6(46.91,18.54) v6(50.19,30.42) v6(53.91,23.74) v6(57.12,29.93) v6(72.36,24.27) v7(4.01,12.96) v7(5.41,12.31) v7(5.56,10.71) v7(5.81,9.56) v7(5.81,8.81) v7(6.86,9.11) v7(7.03,19.68) v7(7.08,18.48) v7(7.18,12.83) v7(7.61,42.7) v7(7.63,16.58) v7(8.11,36.21) v7(8.19,17.51) v7(8.31,45.96) v7(8.45,25.23) v7(8.43,6.78) v7(8.43,5.93) v7(8.58,8.58) v7(8.63,17.93) v7(9.26,31.06) v7(9.56,44.65) v7(9.96,45.6) v7(10.41,21.51) v7(11.03,21.75) v7(11.18,30.92) v7(11.31,26.66) v7(11.26,25.26) v7(11.69,44.47) v7(11.91,45.86) v7(11.86,25.21) v7(12.05,24.4) v7(12.81,44.51) v7(13.06,28.97) v7(13.11,28.28) v7(13.01,25.39) v7(13.07,24.41) v7(13.08,19.23) v7(13.03,12.83) v7(13.43,12.63) v7(13.43,11.73) v7(13.88,9.08) v7(13.93,7.73) v7(14.45,24.58) v7(14.43,9.08) v7(14.48,8.03) v7(14.76,27.41) v7(14.87,37.74) v7(14.98,25.24) v7(15.27,25.02) v7(15.35,26.87) v7(15.54,39.46) v7(15.58,21.13) v7(16.12,27.81) v7(16.33,24.83) v7(16.48,21.58) v7(16.56,34.1) v7(16.66,32.7) v7(17,26.71) v7(17.08,9.28) v7(17.26,35.27) v7(17.49,29.7) v7(17.44,24.22) v7(17.67,44.16) v7(17.66,26.56) v7(18.55,13.74) v7(18.65,53.93) v7(18.96,14.88) v7(19.12,50.08) v7(19.13,41.13) v7(19.77,52.2) v7(19.88,41.88) v7(19.88,8.13) v7(19.91,54.11) v7(19.98,7.73) v7(20.2,55.3) v7(20.18,6.98) v7(20.18,6.43) v7(20.25,46.05) v7(20.23,43.82) v7(20.23,7.43) v7(20.51,51.52) v7(20.56,50.68) v7(20.53,6.03) v7(20.58,5.48) v7(20.87,52.62) v7(20.88,5.13) v7(20.88,4.43) v7(20.99,28.3) v7(21.04,12.27) v7(21.08,3.78) v7(21.12,47.01) v7(21.18,43.18) v7(21.18,22.98) v7(21.18,10.89) v7(21.39,52.02) v7(21.39,50.98) v7(21.54,54.05) v7(21.58,4.78) v7(21.71,44.96) v7(21.96,3.62) v7(22.19,49.56) v7(22.14,46.88) v7(22.23,44.13) v7(22.41,4.28) v7(22.78,44.78) v7(22.78,42.88) v7(22.86,37.74) v7(22.96,48.11) v7(23.03,45.13) v7(23.33,43.43) v7(23.74,28.08) v7(23.72,4.26) v7(23.88,21.13) v7(23.98,26.32) v7(24.13,44.18) v7(24.37,37.71) v7(24.35,4.39) v7(24.42,46.52) v7(24.7,14.61) v7(24.84,4.26) v7(24.98,44.98) v7(25.21,13.09) v7(25.58,47.58) v7(25.67,3.1) v7(25.75,42.83) v7(25.83,4.26) v7(26.08,48.08) v7(26.58,46.53) v7(26.63,48.58) v7(26.68,43.81) v7(26.71,44.42) v7(26.83,50.53) v7(26.83,49.38) v7(27.11,42.96) v7(27.13,4.13) v7(27.48,47.48) v7(27.41,12.4) v7(27.52,37.72) v7(27.68,53.48) v7(27.67,43.57) v7(27.86,48) v7(28,44.96) v7(28.06,36.62) v7(28.18,50.68) v7(28.28,14.33) v7(28.42,29.26) v7(28.64,40.52) v7(28.8,16.48) v7(28.94,52.59) v7(28.99,43.39) v7(29.12,31.83) v7(29.21,29.06) v7(29.12,13.49) v7(29.27,52.96) v7(29.23,42.92) v7(29.57,4.87) v7(29.69,33.24) v7(29.61,30.26) v7(29.69,26.77) v7(29.76,22.26) v7(29.82,49.41) v7(29.81,48.05) v7(29.95,43.73) v7(30.34,46.48) v7(30.36,27.09) v7(30.62,30.44) v7(30.92,4.85) v7(31.17,33.06) v7(31.3,6.36) v7(31.78,45.02) v7(31.78,22.19) v7(31.83,23.02) v7(31.91,6.74) v7(32.1,25.02) v7(32.15,44.32) v7(32.12,8.7) v7(32.31,4.81) v7(32.51,30.39) v7(32.74,22.77) v7(32.87,8.89) v7(33,48.91) v7(32.99,22.18) v7(33,6.36) v7(33.25,43) v7(33.47,8.7) v7(33.94,48.08) v7(34.01,43.22) v7(34.08,8.63) v7(34.19,49.2) v7(34.23,30.38) v7(34.27,29.57) v7(34.27,4.79) v7(34.42,6.44) v7(34.58,47.88) v7(34.63,33.08) v7(34.79,50.86) v7(35.08,30.33) v7(35.35,6.47) v7(35.45,41.12) v7(35.56,43.01) v7(35.9,4.79) v7(35.95,26.63) v7(35.98,7.36) v7(36.17,28.68) v7(36.24,7.91) v7(36.56,44.26) v7(36.53,29.28) v7(36.89,40.95) v7(36.92,7.15) v7(37.05,44.3) v7(37.03,6.36) v7(37.11,4.84) v7(37.54,41.04) v7(37.65,48.84) v7(37.69,7.88) v7(37.99,45.07) v7(37.93,7.21) v7(38.07,42.54) v7(38.07,40.95) v7(38.04,33.83) v7(38.06,12.75) v7(38.08,6.36) v7(38.44,33.49) v7(38.56,7.9) v7(38.79,7.15) v7(39.04,32.34) v7(39.35,42.58) v7(39.4,7.12) v7(39.46,45.02) v7(39.65,24.77) v7(39.73,47.94) v7(39.79,40.87) v7(39.73,6.36) v7(40.25,7.58) v7(40.24,6.63) v7(40.37,41.04) v7(40.48,37.38) v7(40.64,47.97) v7(40.86,50.08) v7(40.99,7.43) v7(41,6.86) v7(41.16,12.02) v7(41.24,21.67) v7(41.22,3.37) v7(41.36,48.82) v7(41.49,30.92) v7(41.53,30.35) v7(41.61,7.88) v7(41.53,6.54) v7(41.59,2.79) v7(41.66,47.81) v7(41.76,11.97) v7(43.48,13.5) v7(46.26,13.5) v7(49.05,7.34) v7(49.5,7.34) v7(51.61,28.93) v7(51.6,28.43) v7(51.62,27.95) v7(51.82,13.5) v7(51.96,40.04) v7(52.23,29.46) v7(52.59,28.92) v7(52.77,2.18) v7(53.99,4.47) v7(56.08,24.98) v7(56.08,24.48) v7(56.47,4.65) v7(60.93,4.58) v7(62.16,4.23) v7(62.11,3.1) v7(65.22,13.97) v7(65.32,21.5) v7(65.45,21.97) v7(65.54,15.92) v7(65.64,20.31) v7(65.7,16.42) v7(65.84,40.27) v7(67.1,39.5) v7(67.59,18.85) v7(67.51,15.61) v7(67.61,17.94) v7(67.73,40.02) v7(69.18,16.21) v7(70.45,16.8) v7(70.57,16.24) v7(72.9,14.57) v7(73.78,8.96) v7(73.94,21) v7(74.52,19.9) v7(75.55,21.06) v7(75.92,32.29) v7(76.28,6.59) v7(79.06,36.32) v7(79.73,35.63) v7(81.14,39.67) v7(81.36,39.07) v7(82.85,35.22) v8(5.36,22.06) v8(5.87,25.31) v8(6.17,24.29) v8(6.19,23.91) v8(6.19,23.72) v8(6.3,28.92) v8(7.03,24.64) v8(7.57,27.78) v8(11.18,30.33) v8(11.58,24.33) v8(11.62,31.35) v8(11.72,26.05) v8(11.84,31.51) v8(12.6,25.74) v8(12.55,24.92) v8(12.65,26.37) v8(12.77,23.78) v8(12.76,20.26) v8(13.31,24.81) v8(13.75,28.32) v8(13.75,28.07) v8(14.05,31.17) v8(14.23,25.3) v8(14.5,31.02) v8(14.45,30.48) v8(14.47,24.2) v8(14.59,26.17) v8(14.58,23.01) v8(14.62,30.29) v8(15.33,30.05) v8(15.94,30.7) v8(18.01,46.91) v8(18.11,47.56) v8(19.56,47.14) v8(20.58,47.14) v8(22,52.09) v8(22.03,51.73) v8(22.03,51.26) v8(24.05,6.92) v8(24.79,9.11) v8(25.84,11.55) v8(26.09,10.81) v8(26.35,10.05) v8(26.35,9.57) v8(27.57,8.82) v8(28.05,31.93) v8(28.22,32.62) v8(28.99,32.7) v8(29.29,17.02) v8(29.56,32.46) v8(29.81,15.67) v8(29.96,32.61) v8(29.96,15.91) v8(30.21,32.96) v8(30.34,32.75) v8(30.42,16.74) v8(30.91,32.66) v8(31.31,32.66) v8(31.63,32.82) v8(32.01,32.91) v8(32.16,32.66) v8(32.46,32.66) v8(32.86,32.71) v8(33.89,26.16) v8(34.61,25.4) v8(34.67,26.73) v8(34.66,26.24) v8(34.62,25.13) v8(34.92,26.06) v8(35.19,25.32) v8(35.81,24.21) v8(39.51,32.76) v8(39.71,33.05) v8(40.03,33.55) v8(40.31,44.76) v8(41.44,37.93) v8(41.72,41.71) v8(42,41.76) v8(58.55,28.2) v8(59.1,26.05) v8(59.16,26.33) v8(59.42,25.85) v8(59.51,27.55) v8(59.75,25.94) v8(61.05,40.87) v8(61.63,27.82) v8(61.64,27.43) v8(62.23,26.35) v8(62.34,28.05) v8(62.38,26.61) v8(62.44,27.39) v8(62.54,27.71) v8(62.83,28.06) v8(62.98,30.63) v8(63.05,27.88) v8(63.31,30.82) v8(63.31,28.03) v8(63.78,26.55) v8(63.75,26.27) v8(63.79,20.21) v8(63.87,27.12) v8(64.1,27.37) v8(64.05,26.87) v8(64.1,26.52) v8(64.09,20.16) v8(64.18,27.09) v8(64.15,26.02) v8(64.29,26.27) v8(64.23,25.72) v8(64.24,21.34) v8(64.33,21.02) v8(64.42,20.59) v8(64.53,20.21) v8(64.75,38.67) v8(65,38.12) v8(65.11,29) v8(65.03,20.14) v8(65.55,37.87) v8(65.6,37.27) v8(65.58,29.76) v8(65.51,29.14) v8(65.59,28.69) v8(65.7,38.27) v8(65.84,23.94) v8(65.93,23.55) v8(66.16,24.26) v8(66.31,23.9) v8(67.3,37.27) v8(67.35,36.67) v8(67.36,33.11) v8(67.8,36.97) v8(67.91,33.03) v8(68.25,36.77) v8(68.35,33.08) v8(68.75,33.37) v8(68.83,33.08) v8(68.95,34.47) v8(69,34.02) v8(69.09,24.16) v8(69.3,36.07) v8(69.3,34.42) v8(69.3,33.47) v8(69.4,34.02) v8(69.5,35.37) v8(69.8,37.62) v8(69.8,36.07) v8(69.9,35.37) v8(69.95,34.62) v8(70,34.27) v8(70.1,33.97) v8(70.2,34.57) v8(70.3,36.07) v8(70.3,35.37) v9(5.41,44.11) v9(6.66,37.21) v9(16.86,44.96) v9(19.11,15.26) v9(19.69,13.31) v9(20.04,13.55) v9(20.04,11.46) v9(20.05,10.36) v9(20.06,9.28) v9(20.07,8.6) v9(20.13,14.64) v9(21.29,48.06) v9(21.28,46.44) v9(21.24,44.75) v9(21.31,47.66) v9(21.34,45.72) v9(21.34,5.63) v9(21.45,4.46) v9(21.59,5.11) v9(21.93,44.53) v9(21.95,4.14) v9(23.01,5.08) v9(23.09,4.32) v9(23.57,5.08) v9(24.49,5.19) v9(25.1,5.73) v9(25.38,4.3) v9(25.53,5.67) v9(26.29,4.32) v9(26.56,4.97) v9(26.94,14.11) v9(27.06,37.61) v9(27.51,34.46) v9(27.65,14.24) v9(28.02,9.04) v9(28.29,5.12) v9(28.68,3.78) v9(28.71,31.95) v9(28.88,29.16) v9(28.96,4.88) v9(29.3,33.31) v9(29.36,37.26) v9(29.4,5.58) v9(29.58,29.16) v9(30.1,4.9) v9(30.19,9.61) v9(30.3,33.27) v9(30.47,5.19) v9(30.56,9.59) v9(30.7,33.07) v9(30.69,9.92) v9(30.78,33.31) v9(30.9,30.05) v9(30.9,29.68) v9(31.07,16.3) v9(31.09,15.51) v9(31.14,33.78) v9(31.11,14.48) v9(31.15,10.11) v9(31.13,9.68) v9(31.24,15.89) v9(31.29,11.78) v9(31.24,10.49) v9(31.35,13.82) v9(31.34,5.02) v9(31.5,9.8) v9(31.56,34.66) v9(31.51,13.37) v9(31.81,33.8) v9(31.95,33.19) v9(32.08,11.83) v9(32.08,10.93) v9(32.08,5.35) v9(32.12,12.66) v9(32.52,10.53) v9(32.52,5.26) v9(32.87,11.71) v9(32.95,10.01) v9(32.93,5.26) v9(33.01,37.71) v9(33.28,9.68) v9(33.29,5.26) v9(33.39,11.36) v9(33.46,32.66) v9(33.56,37.31) v9(33.57,10.68) v9(33.64,5.24) v9(33.98,5.24) v9(34.13,10.76) v9(34.13,9.85) v9(34.31,32.71) v9(34.39,5.25) v9(34.7,33.67) v9(34.65,9.85) v9(34.74,5.26) v9(35.05,9.26) v9(35.06,5.26) v9(35.39,5.27) v9(35.48,9.82) v9(35.54,33.68) v9(35.72,5.26) v9(35.88,11.83) v9(36.01,33.67) v9(36.01,9.15) v9(36.04,5.26) v9(36.38,9.83) v9(36.37,5.26) v9(36.59,33.64) v9(36.77,9.1) v9(36.72,5.26) v9(37.09,5.3) v9(37.11,11.7) v9(37.28,9.84) v9(37.44,5.83) v9(37.5,5.47) v9(37.99,9.04) v9(37.97,5.53) v9(38,4.9) v9(38.17,9.87) v9(38.26,8.59) v9(38.66,4.9) v9(38.82,12.19) v9(38.9,5.56) v9(38.96,11.61) v9(39.3,5.69) v9(39.38,5.12) v9(39.48,10.11) v9(39.49,9.65) v9(39.88,9.26) v9(39.97,42.48) v9(40.46,12.24) v9(40.42,9.92) v9(40.47,9.18) v9(40.48,7.02) v9(40.55,8.11) v9(40.62,11.48) v9(40.61,6.07) v9(40.76,4.79) v9(40.95,12.91) v9(41.23,3.9) v9(41.39,4.8) v9(41.74,3.53) v9(41.97,8.68) v10(3.03,18.85) v10(3.04,18.56) v10(3.05,18.26) v10(3.03,17.96) v10(3.03,17.65) v10(3.02,17.36) v10(3.03,17.07) v10(3.03,16.72) v10(3.05,16.42) v10(3.18,15.88) v10(3.54,15.85) v10(5.1,19.54) v10(5.11,19.89) v10(6.08,19.91) v10(6.07,19.49) v10(6.41,11.86) v10(6.51,19.92) v10(6.53,19.48) v10(6.71,45.21) v10(6.98,43.35) v10(6.98,17.98) v10(7.21,45.16) v10(7.21,11.81) v10(8.29,40.63) v10(8.36,43.96) v10(8.31,43.26) v10(8.38,13.01) v10(8.48,38.58) v10(8.46,31.61) v10(8.51,37.44) v10(8.56,32.51) v10(8.63,39.58) v10(8.79,41.73) v10(8.71,27.56) v10(9.09,40.78) v10(9.11,20.96) v10(9.14,29.55) v10(9.11,28.61) v10(9.27,27.59) v10(9.34,36.22) v10(9.56,36.83) v10(9.61,45.26) v10(9.78,34.66) v10(9.78,33.31) v10(9.78,32.06) v10(9.88,41.78) v10(10.2,11.87) v10(10.23,22.23) v10(10.31,45.11) v10(10.48,39.28) v10(10.6,37.51) v10(10.58,11.78) v10(10.83,20.98) v10(10.92,22.56) v10(11.06,39.79) v10(11.16,28.86) v10(11.16,27.71) v10(11.21,35.46) v10(11.36,32.36) v10(11.46,34.21) v10(11.44,32.88) v10(11.41,30.41) v10(11.46,12.33) v10(11.41,11.66) v10(11.51,34.66) v10(11.56,26.06) v10(11.56,24.71) v10(11.51,24.31) v10(11.51,22.51) v10(11.61,43.16) v10(11.66,39.91) v10(11.68,39.33) v10(11.71,22.91) v10(11.76,17.26) v10(11.86,41.11) v10(11.85,38.17) v10(11.82,28.15) v10(11.96,26.46) v10(12.01,42.86) v10(12.31,38.21) v10(12.46,29.56) v10(12.46,11.56) v10(12.53,40.27) v10(12.53,39.95) v10(12.53,39.32) v10(12.53,38.37) v10(12.69,43.28) v10(12.63,32.88) v10(12.66,18.56) v10(12.66,12.41) v10(12.85,31.93) v10(13.26,17.04) v10(13.38,32.63) v10(13.33,30.78) v10(13.36,17.76) v10(13.46,43.41) v10(13.48,33.21) v10(13.58,35.48) v10(13.54,34.71) v10(13.54,34.28) v10(13.51,24.71) v10(13.51,22.81) v10(13.61,41.11) v10(13.69,30.53) v10(13.73,31.98) v10(13.73,29.73) v10(13.73,18.68) v10(13.86,41.61) v10(13.87,35.75) v10(13.99,30.77) v10(13.91,24.31) v10(13.91,22.56) v10(13.98,20.68) v10(14.11,42.81) v10(14.2,36.07) v10(14.19,34.63) v10(14.19,33.98) v10(14.19,33.38) v10(14.19,32.73) v10(14.14,21.03) v10(14.28,36.68) v10(14.21,31.26) v10(14.23,19.58) v10(14.36,31.61) v10(14.33,30.77) v10(14.38,29.88) v10(14.44,42.23) v10(14.58,29.28) v10(14.59,16.92) v10(14.7,31.92) v10(14.69,30.33) v10(14.66,12.66) v10(14.71,11.41) v10(14.83,36.68) v10(14.83,23.18) v10(14.94,34.79) v10(14.95,33.99) v10(14.96,33.57) v10(14.96,32.6) v10(14.96,16.11) v10(15.04,21.08) v10(15.23,31.78) v10(15.38,37.18) v10(15.43,35.44) v10(15.51,43.41) v10(15.54,36.53) v10(15.58,29.88) v10(15.66,41.26) v10(15.63,37.43) v10(15.62,35.72) v10(15.63,31.38) v10(15.63,29.23) v10(15.71,34.01) v10(15.76,32.36) v10(15.73,19.53) v10(15.73,18.88) v10(15.86,42.96) v10(15.81,11.41) v10(15.95,35.96) v10(15.91,34.61) v10(15.91,24.46) v10(15.93,12.83) v10(16.09,37.08) v10(16.01,32.86) v10(16.09,31.38) v10(16.01,22.61) v10(16.11,41.66) v10(16.18,38.08) v10(16.23,39.13) v10(16.24,38.64) v10(16.29,36.25) v10(16.38,30.58) v10(16.59,37.58) v10(16.63,19.49) v10(16.81,49.99) v10(16.82,39.22) v10(16.88,38.69) v10(16.96,36.94) v10(16.98,23.48) v10(17.08,38.88) v10(17.09,31.33) v10(17.29,47.38) v10(17.23,38.23) v10(17.27,37.17) v10(17.44,49.08) v10(17.56,37.46) v10(17.62,39.5) v10(17.76,32.41) v10(17.81,43.36) v10(17.81,41.56) v10(17.82,40.22) v10(17.89,37.78) v10(17.81,32.86) v10(17.86,24.76) v10(17.86,22.41) v10(17.98,47.78) v10(17.98,38.98) v10(17.91,34.36) v10(17.91,22.96) v10(17.91,12.66) v10(18.06,48.32) v10(18.01,43.06) v10(18.06,24.11) v10(18.06,11.51) v10(18.18,40.03) v10(18.3,50.15) v10(18.21,41.26) v10(18.21,38.1) v10(18.26,37.1) v10(18.36,43.41) v10(18.46,40.27) v10(18.56,38.4) v10(18.87,40.65) v10(18.93,49.28) v10(18.93,38.87) v10(18.98,23.48) v10(19.06,11.36) v10(19.15,39.17) v10(19.11,12.16) v10(19.28,41.83) v10(19.23,41.53) v10(19.3,33.48) v10(19.29,29.03) v10(19.52,39.51) v10(19.74,54.68) v10(19.8,50.07) v10(19.79,37.89) v10(19.78,31.44) v10(19.75,26.01) v10(19.82,39.84) v10(19.86,22.86) v10(19.96,43.36) v10(19.96,24.61) v10(19.91,24.16) v10(19.91,22.41) v10(19.91,14.68) v10(20.05,36.02) v10(20.02,34.16) v10(20.06,32.92) v10(20.01,32.36) v10(20.18,40.16) v10(20.21,29.53) v10(20.34,49.18) v10(20.36,43.06) v10(20.31,34.61) v10(20.43,42.23) v10(20.47,40.45) v10(20.5,39.07) v10(20.5,38.43) v10(20.5,37.05) v10(20.43,27.48) v10(20.46,25.11) v10(20.58,54.65) v10(20.59,40.82) v10(20.79,41.73) v10(20.79,26.01) v10(20.94,42.72) v10(20.93,25.78) v10(21.07,41.14) v10(21.14,46.48) v10(21.11,35.41) v10(21.14,23.53) v10(21.31,49.85) v10(21.34,47.73) v10(21.41,41.44) v10(21.56,43.44) v10(21.64,42.58) v10(21.7,26.49) v10(21.84,37.93) v10(21.83,27.8) v10(21.95,43.71) v10(21.91,26.11) v10(21.96,24.76) v10(21.96,24.36) v10(21.96,22.81) v10(22.01,42.12) v10(22.01,41.11) v10(22.06,39.36) v10(22.06,34.26) v10(22.06,32.46) v10(22.11,30.66) v10(22.28,47.46) v10(22.26,34.66) v10(22.26,32.81) v10(22.31,42.29) v10(22.36,41.56) v10(22.36,39.76) v10(22.35,31.77) v10(22.35,28.9) v10(22.31,26.41) v10(22.48,36.7) v10(22.5,35.89) v10(22.41,31.01) v10(22.46,24.66) v10(22.59,43.53) v10(22.51,22.76) v10(22.6,2.4) v10(23.04,43.18) v10(23.05,42.65) v10(23.09,15.8) v10(23.14,34.47) v10(23.31,45.36) v10(23.43,46.68) v10(23.48,43.03) v10(23.43,31.38) v10(23.43,29.63) v10(23.45,23.95) v10(23.56,48.02) v10(23.58,43.73) v10(23.58,42.73) v10(23.55,36.34) v10(23.68,44.63) v10(23.78,43.93) v10(23.76,16.51) v10(23.82,45.82) v10(23.83,34.74) v10(23.84,7.48) v10(23.98,23.03) v10(23.93,2.53) v10(24.14,47.38) v10(24.18,46.1) v10(24.28,48.93) v10(24.23,45.18) v10(24.23,42.28) v10(24.28,13.66) v10(24.39,39.28) v10(24.43,44.53) v10(24.58,44.81) v10(24.59,24.73) v10(24.79,48.83) v10(24.77,46.77) v10(24.93,29.68) v10(25.09,47.08) v10(25.09,31.03) v10(25.14,40.58) v10(25.18,36.78) v10(25.18,35.38) v10(25.14,28.03) v10(25.11,23.98) v10(25.2,15.45) v10(25.28,2.8) v10(25.38,48.48) v10(25.33,47.33) v10(25.34,33.83) v10(25.48,49.13) v10(25.46,43.51) v10(25.43,26.08) v10(25.56,43.96) v10(25.68,32.53) v10(25.79,48.73) v10(25.8,15.27) v10(25.84,46.78) v10(25.97,46.06) v10(25.98,38.53) v10(26.05,7.18) v10(26.18,46.28) v10(26.29,30.08) v10(26.64,7.12) v10(26.79,52.08) v10(26.88,50.98) v10(26.83,50.13) v10(26.84,49.78) v10(26.83,48.93) v10(26.88,47.02) v10(26.81,45.21) v10(27.07,46.8) v10(27.11,14.43) v10(27.48,52.03) v10(27.48,51.28) v10(27.48,50.58) v10(27.48,49.73) v10(27.48,49.03) v10(27.46,45.26) v10(27.46,7.16) v10(27.6,53.07) v10(27.58,46.86) v10(27.74,55) v10(27.99,54.69) v10(28.12,51.05) v10(28.13,50.25) v10(28.27,52.79) v10(28.43,53.43) v10(28.46,13.76) v10(28.6,51.84) v10(28.68,54.87) v10(28.68,50.58) v10(28.73,46.48) v10(29,53.56) v10(28.93,52.93) v10(29.21,7.21) v10(29.39,39.98) v10(29.41,41.7) v10(29.52,19.44) v10(29.66,53.51) v10(29.68,38.38) v10(29.82,20.49) v10(29.95,34.36) v10(29.94,15.11) v10(29.97,13.02) v10(30.16,21.36) v10(30.2,19.69) v10(30.39,41.33) v10(30.32,31.93) v10(30.38,15.69) v10(30.49,39.1) v10(30.53,21.78) v10(30.69,7.07) v10(30.76,15.71) v10(30.98,37.83) v10(31.39,11.01) v10(31.56,45.98) v10(31.65,41.1) v10(31.72,13.66) v10(32.06,15.78) v10(32.21,25.81) v10(32.3,14.35) v10(32.23,13.08) v10(32.35,39.44) v10(32.46,45.21) v10(32.53,7.18) v10(32.61,22.19) v10(32.79,20.48) v10(32.83,13.34) v10(32.95,28.02) v10(33.09,48) v10(33.11,21.5) v10(33.26,31.91) v10(33.28,12.08) v10(33.33,23.17) v10(33.34,12.73) v10(33.41,13.81) v10(33.54,46.04) v10(33.73,12.3) v10(33.81,38.91) v10(33.81,35.71) v10(33.88,9.14) v10(34.22,18.8) v10(34.39,40) v10(34.47,35.14) v10(34.5,23.54) v10(34.53,32.23) v10(34.62,12.29) v10(34.72,17.92) v10(34.92,20.2) v10(35.08,18.46) v10(35.23,32.73) v10(35.39,48.36) v10(35.36,31.47) v10(35.36,28.97) v10(35.36,20.76) v10(35.44,30.98) v10(35.44,29.54) v10(35.44,26.79) v10(35.45,20.01) v10(35.59,45.84) v10(35.56,34.47) v10(35.58,32.28) v10(35.56,26.26) v10(35.54,23.57) v10(35.53,18.93) v10(35.53,17.55) v10(35.69,40.09) v10(35.64,30.17) v10(35.7,25.61) v10(35.63,7.23) v10(35.89,31.59) v10(35.97,49.12) v10(35.98,47.08) v10(35.95,29.1) v10(36.09,41.76) v10(36.01,27.53) v10(36.06,18.2) v10(36.18,34.62) v10(36.13,18.94) v10(36.22,26.11) v10(36.28,16.98) v10(36.33,33.98) v10(36.33,23.83) v10(36.33,20.76) v10(36.36,7.34) v10(36.47,41.06) v10(36.47,31.09) v10(36.47,24.98) v10(36.59,33.47) v10(36.61,27.53) v10(36.54,24.24) v10(36.58,12.16) v10(36.67,30.31) v10(36.69,26.33) v10(36.7,25.64) v10(36.69,19.03) v10(36.64,18.33) v10(36.71,39.95) v10(36.73,22.11) v10(36.83,16.78) v10(36.82,7.15) v10(36.98,31.36) v10(36.94,24.16) v10(36.91,23.21) v10(37.05,24.65) v10(37.21,34.93) v10(37.11,34.16) v10(37.14,29.97) v10(37.14,28.9) v10(37.17,22.93) v10(37.29,46.83) v10(37.25,33.44) v10(37.28,23.51) v10(37.39,42.28) v10(37.34,30.63) v10(37.33,29.28) v10(37.34,16.47) v10(37.42,22.43) v10(37.59,47.64) v10(37.55,18.3) v10(37.54,17.64) v10(37.81,46.13) v10(37.72,35.2) v10(37.89,34.68) v10(37.88,33.22) v10(38,23.7) v10(37.94,17.1) v10(37.94,16.33) v10(38.08,17.78) v10(38.09,7.96) v10(38.25,35.27) v10(38.24,15.94) v10(38.34,47.13) v10(38.39,44.47) v10(38.33,43.55) v10(38.34,39.08) v10(38.4,34.27) v10(38.44,45.48) v10(38.41,40.05) v10(38.47,34.86) v10(38.55,46.47) v10(38.61,35.84) v10(38.69,42.73) v10(38.77,38.51) v10(38.72,16.4) v10(38.72,10.09) v10(38.93,41.43) v10(38.94,15.73) v10(39,15.08) v10(38.94,13.83) v10(39.11,36.57) v10(39.23,37.71) v10(39.27,35.9) v10(39.3,35.28) v10(39.24,10.19) v10(39.38,39.61) v10(39.5,46.21) v10(39.48,16.33) v10(39.48,14.88) v10(39.61,47.12) v10(39.55,43.38) v10(39.68,44.07) v10(39.68,38.72) v10(39.69,10.74) v10(39.77,36.63) v10(39.79,9.2) v10(39.87,15.82) v10(39.98,41.89) v10(39.94,38.02) v10(39.92,35.28) v10(39.92,16.22) v10(39.99,15.04) v10(39.94,10.32) v10(40.05,13.08) v10(40.01,10.8) v10(40.14,39.88) v10(40.14,35.9) v10(40.17,16.26) v10(40.26,45.73) v10(40.26,13.74) v10(40.25,11.26) v10(40.33,46.83) v10(40.36,39.01) v10(40.33,36.61) v10(40.46,49.01) v10(40.45,15.46) v10(40.44,14.71) v10(40.53,35.28) v10(40.54,16.03) v10(40.59,7.24) v10(40.69,13.83) v10(40.69,7.86) v10(40.72,35.83) v10(40.89,36.58) v10(40.84,11.7) v10(40.94,43.62) v10(41.09,38.36) v10(41.03,15.49) v10(41.1,11.46) v10(41.11,2.87) v10(41.21,35.28) v10(41.39,41.72) v10(41.39,41.21) v10(41.48,43.81) v10(41.41,39.68) v10(41.48,39) v10(41.49,36.68) v10(41.42,35.93) v10(41.44,12.38) v10(41.49,7.34) v10(41.53,45.64) v10(41.58,10.22) v10(41.58,9.33) v10(41.56,2.18) v10(41.64,46.48) v10(41.72,50.62) v10(41.75,12.84) v10(41.89,36.62) v10(41.83,35.28) v10(41.97,40.28) v10(41.91,35.83) v10(42.27,38.98) v10(42.28,36.61) v10(42.28,14.23) v10(42.34,47.15) v10(42.39,13.83) v10(42.46,35.28) v10(42.53,44.16) v10(42.7,36.63) v10(42.86,35.91) v10(43.09,36.69) v10(43.09,35.28) v10(43.45,14.37) v10(43.67,35.93) v10(43.72,35.27) v10(43.72,14.78) v10(43.78,10.48) v10(43.86,39.42) v10(44.08,11.43) v10(44.14,36.77) v10(44.11,15.14) v10(44.27,40.27) v10(44.37,35.27) v10(44.32,9.14) v10(44.55,36.61) v10(44.67,35.94) v10(45,46.91) v10(44.98,35.27) v10(44.94,11.38) v10(45.03,46.01) v10(45.19,36.57) v10(45.2,35.88) v10(45.33,10.63) v10(45.58,35.26) v10(45.76,33.29) v10(45.88,35.86) v10(46.08,10.83) v10(46.21,35.27) v10(46.14,11.43) v10(46.35,35.93) v10(46.48,33.83) v10(46.7,43.88) v10(46.82,35.27) v10(47.03,43.11) v10(47.03,35.89) v10(47.22,36.57) v10(47.44,35.5) v10(47.45,33.37) v10(47.51,35.97) v10(47.55,34.92) v10(47.55,15.06) v10(47.62,34.13) v10(47.74,33.55) v10(47.94,35.28) v10(48.17,36.08) v10(48.52,46.14) v10(48.91,42.74) v10(49.17,31.72) v10(49.2,31.41) v10(49.22,35.08) v10(49.31,34.39) v10(49.33,33.7) v10(49.45,31.16) v10(49.56,42.35) v10(49.58,32.19) v10(50.28,43.85) v10(50.48,3.68) v10(50.61,48.78) v10(50.62,47.17) v10(50.64,36.18) v10(50.64,35.81) v10(50.64,35.04) v10(51.09,42.74) v10(51.28,41.02) v10(51.66,8.52) v10(52.19,47.9) v10(52.19,46.66) v10(52.19,42.71) v10(52.14,32.89) v10(52.24,15.02) v10(52.25,4.25) v10(52.6,15.5) v10(52.52,2.95) v10(52.64,15.03) v10(52.66,9.18) v10(53.01,14.12) v10(53.22,3.13) v10(53.34,32.18) v10(53.56,36.27) v10(53.52,35.48) v10(53.94,44.98) v10(54,36.02) v10(53.92,8.55) v10(54.86,14.75) v10(55.08,4.27) v10(55.36,8.48) v10(55.72,46.45) v10(56.25,14.76) v10(56.42,14.01) v10(56.98,8.79) v10(57.78,43.65) v10(58.14,41.58) v10(58.39,8.63) v10(58.89,45.28) v10(58.84,40.51) v10(58.92,38.61) v10(59.67,41.15) v10(60.19,8.79) v10(60.31,10.18) v10(60.41,10.77) v10(60.84,39.68) v10(60.97,38.61) v10(61.05,19.39) v10(61.33,9.75) v10(61.48,9.17) v10(61.67,10.26) v10(61.72,40.35) v10(61.97,10.55) v10(61.94,9.66) v10(62.03,43.65) v10(62.06,30.55) v10(62.06,11.7) v10(62.23,41.75) v10(62.22,35.98) v10(62.25,9.21) v10(62.42,25.7) v10(62.47,20.8) v10(62.43,20.45) v10(62.44,8.64) v10(62.51,21.15) v10(62.61,36.38) v10(62.62,35.26) v10(62.73,32.2) v10(62.8,12.49) v10(62.81,40.32) v10(62.96,29.97) v10(62.92,21.66) v10(62.92,13.41) v10(63.08,44.3) v10(63.08,30.61) v10(63.02,15.03) v10(63.19,35.78) v10(63.15,8.96) v10(63.25,37) v10(63.38,10) v10(63.31,9.53) v10(63.44,30.64) v10(63.41,17.32) v10(63.47,14.92) v10(63.56,36.18) v10(63.7,37.4) v10(63.68,33.11) v10(63.63,16.84) v10(63.72,34.38) v10(63.75,11.87) v10(63.91,30.61) v10(64.07,30.09) v10(64.06,14.88) v10(64.11,41.41) v10(64.11,17.16) v10(64.39,33.82) v10(64.42,17.84) v10(64.41,17.39) v10(64.47,15.39) v10(64.63,14.9) v10(64.73,34.17) v10(64.81,35.43) v10(64.94,37.72) v10(65,14.75) v10(65.01,34.42) v10(65.26,34.67) v10(65.58,42.15) v10(65.56,15.47) v10(65.64,35.02) v10(65.86,33.91) v10(66.08,37.71) v10(66.06,34.23) v10(66.15,33.89) v10(66.4,34.11) v10(66.48,34.47) v10(66.52,33.49) v10(66.88,34.26) v10(66.83,14.7) v10(67.08,37.67) v10(67.33,34.05) v10(67.36,14.77) v10(67.61,34.29) v10(67.8,15.02) v10(68.08,44.98) v10(68.08,43.98) v10(68.08,43.23) v10(68.08,42.23) v10(68.17,18.87) v10(68.18,15.63) v10(68.3,37.68) v10(68.28,19.18) v10(68.29,14.84) v10(68.36,4.9) v10(68.58,48.98) v10(68.78,15.06) v10(68.83,45.98) v10(68.83,44.98) v10(68.83,43.98) v10(68.83,43.23) v10(68.83,42.23) v10(68.95,4.79) v10(69.02,15.62) v10(69.24,14.87) v10(69.58,54.73) v10(69.58,53.98) v10(69.58,52.98) v10(69.58,51.98) v10(69.58,50.98) v10(69.58,49.98) v10(69.58,48.98) v10(69.58,47.98) v10(69.58,46.98) v10(69.58,45.98) v10(69.58,44.98) v10(69.58,43.98) v10(69.58,43.23) v10(69.53,37.68) v10(69.7,16.31) v10(69.74,15.68) v10(69.83,39.65) v10(70.01,34.51) v10(70.04,14.95) v10(70.58,53.98) v10(70.58,52.98) v10(70.58,51.98) v10(70.58,50.98) v10(70.58,49.98) v10(70.58,48.98) v10(70.58,46.98) v10(70.58,45.98) v10(70.58,44.98) v10(70.58,43.98) v10(70.58,43.23) v10(70.58,42.23) v10(70.77,39.14) v10(71.08,54.98) v10(71.19,40.32) v10(71.23,41.8) v10(71.49,37.76) v10(71.41,7.6) v10(71.58,53.98) v10(71.58,52.98) v10(71.58,51.98) v10(71.58,50.98) v10(71.58,49.98) v10(71.58,48.98) v10(71.58,46.98) v10(71.58,45.98) v10(71.58,44.98) v10(71.58,43.98) v10(71.58,43.23) v10(71.58,42.23) v10(71.6,40.97) v10(71.57,40.1) v10(71.52,6.11) v10(72.08,54.98) v10(72.05,42.63) v10(72.06,5.18) v10(72.58,53.98) v10(72.58,52.98) v10(72.58,51.98) v10(72.58,50.98) v10(72.58,49.98) v10(72.58,48.98) v10(72.58,47.73) v10(72.58,46.98) v10(72.58,45.98) v10(72.58,44.98) v10(72.58,43.23) v10(72.58,42.23) v10(72.67,40.55) v10(72.81,40.9) v10(72.97,42.8) v10(73.08,54.98) v10(73.33,45.98) v10(73.33,43.23) v10(73.33,42.23) v10(73.33,41.38) v10(73.58,53.98) v10(73.58,52.98) v10(73.58,51.98) v10(73.58,50.98) v10(73.58,49.98) v10(73.58,48.98) v10(73.58,47.73) v10(73.56,40.96) v10(73.83,43.98) v10(73.83,43.23) v10(73.83,42.23) v10(74.08,54.98) v10(74.08,45.98) v10(74.08,44.98) v10(74.02,42.63) v10(74.03,10.37) v10(74.11,41.06) v10(74.38,52.56) v10(74.34,6.24) v10(74.48,53.88) v10(74.44,53.2) v10(74.41,41.67) v10(74.58,48.48) v10(74.58,47.73) v10(74.58,46.98) v10(74.63,39.63) v10(74.8,13.31) v10(74.91,40.45) v10(74.91,50.86) v10(74.94,50.58) v10(74.92,41.09) v10(74.96,39.93) v10(74.96,13.78) v10(75.08,54.98) v10(75.03,50.28) v10(75.16,51.91) v10(75.16,51.21) v10(75.2,6.97) v10(75.26,51.61) v10(75.3,10.35) v10(75.38,50.28) v10(75.31,49.41) v10(75.38,45.36) v10(75.44,50.73) v10(75.49,45.88) v10(75.44,40.47) v10(75.56,46.61) v10(75.58,41.98) v10(75.69,50.28) v10(75.69,49.68) v10(75.66,48.36) v10(75.66,48.01) v10(75.64,44.67) v10(75.62,44.23) v10(75.63,43.87) v10(75.63,43.52) v10(75.68,43.14) v10(75.61,42.67) v10(75.68,12.22) v10(75.71,44.96) v10(75.83,46.29) v10(75.91,41.27) v10(76.08,54.98) v10(76.16,44.16) v10(76.12,34.19) v10(76.34,13.58) v10(76.37,11.81) v10(76.46,43.91) v10(76.48,42.7) v10(76.63,13.91) v10(76.86,45.06) v10(76.86,43.91) v10(76.91,50.76) v10(76.96,50.46) v10(76.96,50.06) v10(76.96,49.66) v10(76.96,49.21) v10(76.96,48.81) v10(76.96,48.36) v10(76.96,47.91) v10(76.96,46.76) v10(76.91,43.63) v10(76.94,42.64) v10(77.08,54.98) v10(77.06,51.96) v10(77.01,47.56) v10(77.01,47.16) v10(77.03,44.83) v10(77.1,27.22) v10(77.07,14.13) v10(77.13,45.88) v10(77.15,45.46) v10(77.26,43.91) v10(77.3,43.58) v10(77.28,27.51) v10(77.36,44.71) v10(77.33,42.5) v10(77.34,34.48) v10(77.31,25.41) v10(77.41,41.95) v10(77.49,14.97) v10(77.51,52.7) v10(77.58,49.98) v10(77.56,43.86) v10(77.52,41.39) v10(77.59,24.32) v10(77.61,53.85) v10(77.66,44.66) v10(77.79,53.33) v10(77.79,26.95) v10(77.8,26.57) v10(77.85,40.64) v10(77.91,43.86) v10(77.96,40.07) v10(77.96,33.6) v10(77.96,24.98) v10(77.97,24.21) v10(78.08,54.98) v10(78.08,46.73) v10(78.01,44.66) v10(78.08,41.78) v10(78.02,41.18) v10(78.21,43.86) v10(78.25,14.92) v10(78.33,50.98) v10(78.33,47.98) v10(78.36,44.66) v10(78.58,53.98) v10(78.58,53.23) v10(78.58,52.23) v10(78.58,49.98) v10(78.58,48.98) v10(78.56,43.86) v10(78.58,40.81) v10(78.66,44.66) v10(78.7,42.95) v10(78.76,39.71) v10(78.76,38.96) v10(78.71,38.41) v10(78.75,30.62) v10(78.75,12.97) v10(78.81,43.46) v10(78.81,40.36) v10(78.96,45.91) v10(78.96,43.81) v10(78.91,40.92) v10(79.08,54.98) v10(79.01,44.66) v10(79.16,38.21) v10(79.26,43.81) v10(79.33,52.23) v10(79.31,44.66) v10(79.41,39.96) v10(79.33,39.14) v10(79.58,53.98) v10(79.58,53.23) v10(79.58,51.48) v10(79.58,50.98) v10(79.58,49.98) v10(79.58,48.98) v10(79.51,45.96) v10(79.66,44.66) v10(79.61,43.81) v10(79.64,40.48) v10(79.87,10.88) v10(79.91,45.34) v10(79.91,43.81) v10(79.96,13.77) v10(80,10.46) v10(80.01,44.76) v10(80.11,37.3) v10(80.21,46.01) v10(80.21,43.81) v10(80.27,10.91) v10(80.36,44.76) v10(80.42,35.58) v10(80.58,54.73) v10(80.58,53.98) v10(80.58,49.98) v10(80.58,48.98) v10(80.51,43.81) v10(80.51,36.12) v10(80.71,44.76) v10(80.81,43.81) v10(80.92,45.75) v10(80.96,38.26) v10(80.93,14.1) v10(81.06,44.76) v10(81.03,34.45) v10(81.11,43.76) v10(81.36,46.01) v10(81.31,44.91) v10(81.38,34.75) v10(81.33,34.09) v10(81.46,43.51) v10(81.46,36.46) v10(81.46,29.51) v10(81.5,11.56) v10(81.58,54.73) v10(81.58,53.98) v10(81.58,48.98) v10(81.58,47.98) v10(81.51,45.16) v10(81.56,35.11) v10(81.56,34.41) v10(81.51,30.51) v10(81.51,30.26) v10(81.6,9.58) v10(81.61,37.31) v10(81.61,36.11) v10(81.8,41.62) v10(81.71,35.51) v10(81.71,33.86) v10(81.86,45.69) v10(81.86,45.26) v10(81.94,46.33) v10(81.96,39.97) v10(82.1,9.33) v10(82.16,45.26) v10(82.16,37.31) v10(82.12,9.74) v10(82.23,41.78) v10(82.21,36.36) v10(82.26,35.36) v10(82.21,34.46) v10(82.36,43.31) v10(82.31,33.76) v10(82.36,33.26) v10(82.36,30.51) v10(82.34,21.64) v10(82.39,21.19) v10(82.41,30.96) v10(82.42,12.03) v10(82.58,54.73) v10(82.58,49.98) v10(82.58,48.98) v10(82.58,47.98) v10(82.51,45.26) v10(82.56,11.08) v10(82.7,41.73) v10(82.66,32.86) v10(82.63,12.62) v10(82.63,11.71) v10(82.71,43.26) v10(82.77,39.87) v10(82.71,37.46) v10(82.77,9.27) v10(82.83,52.98) v10(82.83,51.98) v10(82.83,50.98) v10(82.91,45.26) v10(82.91,43.56) v10(82.95,38.37) v10(83.01,32.46) v10(83.16,33.01) v10(83.21,46.06) v10(83.26,45.11) v10(83.21,39.57) v10(83.26,38.12) v10(83.26,30.06) v10(83.58,48.98) v10(83.58,47.98) v10(83.55,45.7) v10(83.51,44.16) v10(83.56,39.31) v10(83.51,32.51) v10(83.61,45.11) v10(83.61,32.01) v10(83.8,39.69) v10(83.83,49.98) v10(83.84,49.51) v10(83.96,45.11) v10(83.91,44.16) v10(83.91,32.71) v10(84.06,50.65) v10(84.12,42.37) v10(84.11,30.01) v10(84.26,45.11) v10(84.41,28.71) v10(84.56,43.66) v10(84.57,36.77) v10(84.66,46.11) v10(84.71,45.31) v10(84.8,42.44) v10(84.73,10.61) v10(84.74,10.21) v10(84.73,9.65) v10(84.96,43.71) v10(85.06,45.31) v10(85.15,46.89) v10(85.26,38.21) v10(85.31,43.81) v10(85.46,46.11) v10(85.41,45.36) v10(85.56,37.17) v10(85.76,45.36) v10(85.76,30.11) v10(85.71,19.98) v10(85.74,8.37) v10(85.81,35.96) v10(85.86,29.01) v10(85.96,33.86) v10(85.93,26) v10(86.07,46.86) v10(86.06,38.16) v10(86.11,45.36) v10(86.2,20.03) v10(86.27,42.57) v10(86.33,26.06) v10(86.46,45.36) v10(86.41,35.21) v10(86.51,46.06) v10(86.66,44.46) v10(86.61,33.86) v10(86.76,37.81) v10(86.76,28.01) v10(86.86,45.31) v10(86.84,43.03) v10(86.82,37.16) v10(86.86,31.81) v10(86.94,46.87) v10(86.91,31.26) v10(86.96,30.01) v10(87.01,44.41) v10(87.01,29.11) v10(87.19,42.46) v10(87.2,37.18) v10(87.21,45.21) v10(87.27,43.85) v10(87.3,41.92) v10(87.36,44.31) v10(87.36,40.1) v10(87.31,28.06) v10(87.41,46.11) v10(87.44,43.01) v10(87.5,37.19) v10(87.42,17.27) v10(87.51,45.16) v10(87.67,45.5) v10(87.66,44.16) v10(87.66,30.06) v10(87.76,41.96) v10(87.71,30.91) v10(87.81,45.01) v10(87.81,41.56) v10(87.96,44.01) v10(87.91,42.51) v10(88.01,46.11) v10(88.08,40.88) v10(88.16,44.86) v10(88.11,43.66) v10(88.11,43.31) v10(88.11,42.91) v10(88.13,40.15) v10(88.11,35.01) v10(88.15,10.7) v10(88.14,10.38) v10(88.13,9.91) v10(88.13,9.57) v10(88.32,45.45) v10(88.34,40.44) v10(88.36,38.26) v10(88.46,44.71) v10(88.41,41.26) v10(88.46,34.61) v10(88.71,46.06) v10(88.87,45.3) v10(88.81,44.51) v10(88.86,41.21) v10(88.86,40.81) v10(88.86,40.41) v10(88.86,40.06) v10(88.81,34.11) v10(89.11,44.26) v10(89.11,39.76) v10(89.27,44.9) v10(89.21,43.91) v10(89.21,43.56) v10(89.21,43.21) v10(89.21,42.86) v10(89.26,42.51) v10(89.26,35.21) v10(89.31,33.71) v10(89.46,46.01) v10(89.46,38.16) v10(89.57,45.45) v10(89.51,42.21) v10(89.66,41.76) v10(89.61,19.58) v10(89.7,18.95) v10(89.72,44.2) v10(89.72,43.35) v10(89.72,37.7) v10(89.71,30.16) v10(89.74,18.34) v10(89.86,44.91) v10(89.92,42.75) v10(89.96,40.96) v10(90.07,42.15) v10(90.01,40.56) v10(90.11,40.16) v10(90.21,46.01) v10(90.21,39.76) v10(90.26,30.01) v10(90.41,39.41) v10(90.41,38.96) v10(90.57,45.5) v10(90.67,46.28) v10(90.72,40.45) v10(90.87,39.7) v10(90.81,31.56) v10(90.86,31.01) v10(90.91,32.16) v10(90.96,28.51) v10(91.01,45.96) v10(91.07,39.2) v10(91.12,40.9) v10(91.13,37.21) v10(91.22,40.15) v10(91.27,38.5) v10(91.57,37.2) v10(91.78,40.58) v10(91.78,39.38) v10(91.78,38.08) v10(91.86,42.11) v10(91.86,41.01) v10(91.86,38.61) v10(91.83,37.63) v10(91.83,36.78) v10(91.88,32.68) v10(91.96,45.96) v10(91.96,44.56) v10(91.97,44.15) v10(91.91,43.21) v10(91.99,37.18) v10(91.94,35.33) v10(92.01,39.76) v10(92.03,34.03) v10(92.01,32.31) v10(92.06,31.26) v10(92.03,30.78) v10(92.4,37.18) v11(4.11,12.06) v11(4.61,12.91) v11(4.66,11.66) v11(5.51,45.41) v11(6.01,46.01) v11(6.26,10.01) v11(6.81,46.01) v11(6.9,5.96) v11(7.11,6.56) v11(7.16,5.31) v11(7.61,46.06) v11(7.86,5.16) v11(9.33,21.11) v11(10.06,46.06) v11(10.26,5.11) v11(10.56,46.36) v11(11.06,5.36) v11(11.21,6.21) v11(11.36,46.41) v11(12.16,46.41) v11(12.88,6.43) v11(12.96,46.41) v11(13.71,46.41) v11(13.78,28.78) v11(13.88,6.48) v11(14.46,46.41) v11(14.58,6.68) v11(15.11,46.91) v11(15.15,30.78) v11(15.66,47.46) v11(16.13,7.68) v11(16.31,48.66) v11(16.26,48.01) v11(16.36,50.26) v11(16.36,49.41) v11(16.47,55.71) v11(16.66,52.86) v11(16.7,51.2) v11(16.78,8.28) v11(16.85,51.97) v11(17.26,50.86) v11(17.38,8.53) v11(17.66,52.76) v11(17.97,55.71) v11(18.08,8.53) v11(18.47,54.87) v11(18.51,48.2) v11(18.93,8.63) v11(19.26,53.34) v11(19.47,55.71) v11(19.48,8.63) v11(20.67,53.47) v11(20.97,55.71) v11(22.08,50.48) v11(22.32,48.18) v11(22.47,55.71) v11(22.58,54.98) v11(22.58,53.98) v11(22.58,52.98) v11(23.08,50.48) v11(23.08,49.48) v11(23.58,52.98) v11(23.97,55.71) v11(24.08,50.48) v11(24.58,52.48) v11(24.58,51.48) v11(25.08,50.48) v11(25.47,55.71) v11(25.58,52.98) v11(25.58,51.98) v11(25.58,50.98) v11(26.08,50.48) v11(26.58,55.48) v11(26.58,54.48) v11(26.58,53.48) v11(26.58,52.48) v11(26.58,51.48) v11(27.4,55.69) v11(27.93,54.13) v11(28.33,49.53) v11(28.33,48.63) v11(28.58,54.18) v11(29.08,50.98) v11(29.08,49.98) v11(29.08,48.98) v11(29.08,47.98) v11(29.58,50.48) v11(30.58,50.48) v11(31.08,55.48) v11(31.08,54.98) v11(31.08,51.48) v11(31.58,50.48) v11(32.58,53.48) v11(32.58,50.48) v11(33.58,54.48) v11(33.58,53.48) v11(33.58,52.48) v11(33.58,51.48) v11(33.58,50.48) v11(34.46,55.56) v11(34.48,13.62) v11(34.58,54.48) v11(34.58,53.48) v11(34.58,52.48) v11(35.06,13.03) v11(35.58,53.98) v11(35.58,52.98) v11(35.58,51.98) v11(35.58,49.98) v11(35.86,12.82) v11(36.58,53.98) v11(36.58,52.98) v11(36.58,51.98) v11(36.58,50.98) v11(36.58,49.98) v11(36.66,15.81) v11(37.25,15.22) v11(37.25,13.62) v11(37.46,14.42) v11(37.58,53.98) v11(37.58,52.98) v11(37.58,51.98) v11(37.58,50.98) v11(37.58,49.98) v11(38.58,53.98) v11(38.58,52.98) v11(38.58,51.98) v11(38.58,50.98) v11(38.58,49.98) v11(38.58,48.98) v11(39.58,53.98) v11(39.58,52.98) v11(39.58,51.98) v11(39.58,50.98) v11(39.58,49.98) v11(39.58,48.98) v11(40.05,55.71) v11(40.08,54.98) v11(40.61,54.03) v11(40.61,53.03) v11(40.61,52.03) v11(40.58,50.98) v11(40.79,42.63) v11(40.89,44.75) v11(41.08,54.98) v11(41.49,1.5) v11(41.55,55.71) v11(41.61,54.03) v11(41.61,53.03) v11(41.61,52.03) v11(41.71,42.7) v11(42.61,53.03) v11(42.61,52.03) v11(43.61,53.03) v11(43.61,52.03) v11(44.61,53.03) v11(44.61,52.03) v11(45.61,53.03) v11(45.61,52.03) v11(46.61,53.03) v11(46.61,52.03) v11(61.78,55.58) v11(65.08,55.73) v11(83.98,51.18) v11(84.73,51.18) v11(88.43,51.18) v11(89.33,50.18) v11(89.58,49.28) v11(90.13,48.53) v11(90.83,48.18) v11(91.53,48.03) v11(92.26,47.76) v12(52.92,23.24) v12(53.91,25.22) v12(53.91,24.73) v12(54.39,25.19) v12(54.4,24.73) v12(55.39,23.74) v12(55.89,25.22) v12(55.89,24.73) v12(55.89,24.23) v12(55.89,23.74) v12(55.89,23.24) v12(56.38,23.24) v12(56.88,23.24) v12(59.1,22.01) v12(59.38,21.98) v13(51.17,31.41) v13(51.37,34.07) v13(51.99,31.98) v13(52.5,32.18) v13(52.42,27.71) v13(52.89,30.66) v13(52.91,27.7) v13(53.08,32.4) v13(53.16,31.42) v13(54.15,31.42) v13(54.4,26.71) v13(55.39,28.77) v14(20.85,14.39) v14(21.64,11.9) v14(21.88,8.69) v14(21.94,10.87) v14(21.97,5.45) v14(22.46,8.94) v14(23.67,5.51) v14(24.82,16.59) v14(25.16,5.21) v14(28.6,13.02) v14(28.79,13.26) v14(29.93,16.53) v14(30.17,16.17) v14(30.63,16.17) v14(37.07,33.39)
